VERSION 5.8 ;
BUSBITCHARS "[]" ;
DIVIDERCHAR "/" ;
UNITS
    DATABASE MICRONS 1000 ;
END UNITS

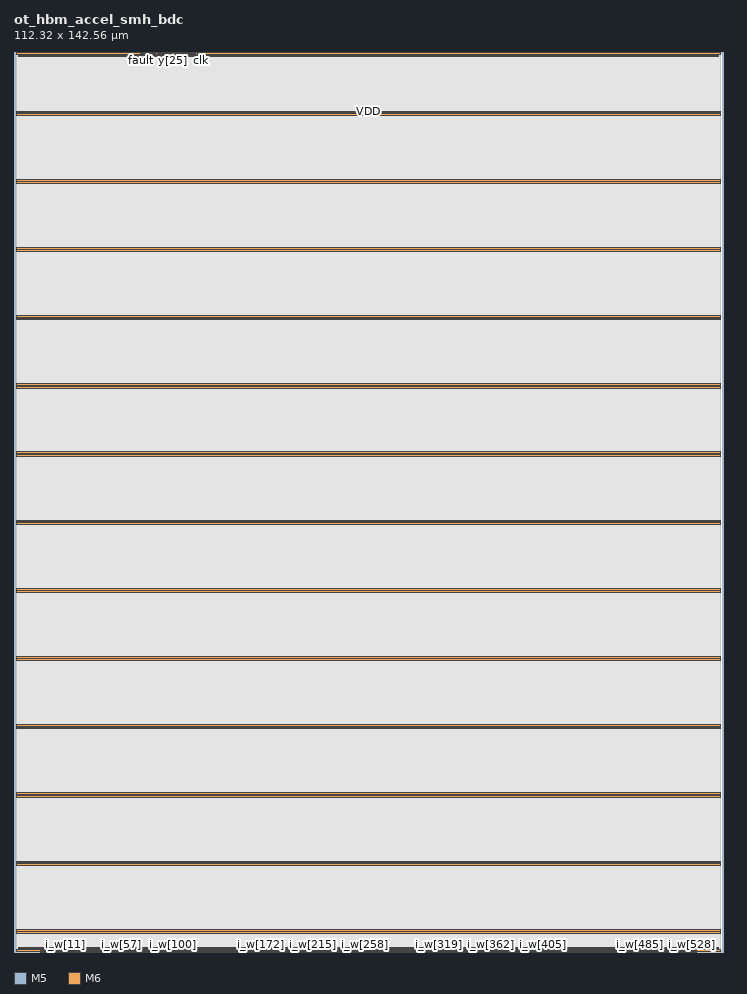
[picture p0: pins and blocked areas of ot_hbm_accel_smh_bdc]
MACRO ot_hbm_accel_smh_bdc
  FOREIGN ot_hbm_accel_smh_bdc 0 0 ;
  CLASS BLOCK ;
  SIZE 112.32 BY 142.56 ;
  PIN clk
    DIRECTION INPUT ;
    USE SIGNAL ;
    PORT
      LAYER M5 ;
        RECT  29.568 142.368 29.592 142.56 ;
    END
  END clk
  PIN fault
    DIRECTION OUTPUT ;
    USE SIGNAL ;
    PORT
      LAYER M5 ;
        RECT  20.16 142.368 20.184 142.56 ;
    END
  END fault
  PIN i_first
    DIRECTION INPUT ;
    USE SIGNAL ;
    PORT
      LAYER M5 ;
        RECT  4.224 0 4.248 0.192 ;
    END
  END i_first
  PIN i_fp4
    DIRECTION INPUT ;
    USE SIGNAL ;
    PORT
      LAYER M5 ;
        RECT  4.416 0 4.44 0.192 ;
    END
  END i_fp4
  PIN i_last
    DIRECTION INPUT ;
    USE SIGNAL ;
    PORT
      LAYER M5 ;
        RECT  4.32 0 4.344 0.192 ;
    END
  END i_last
  PIN i_tag[0]
    DIRECTION INPUT ;
    USE SIGNAL ;
    PORT
      LAYER M5 ;
        RECT  4.512 0 4.536 0.192 ;
    END
  END i_tag[0]
  PIN i_tag[10]
    DIRECTION INPUT ;
    USE SIGNAL ;
    PORT
      LAYER M5 ;
        RECT  5.472 0 5.496 0.192 ;
    END
  END i_tag[10]
  PIN i_tag[11]
    DIRECTION INPUT ;
    USE SIGNAL ;
    PORT
      LAYER M5 ;
        RECT  5.568 0 5.592 0.192 ;
    END
  END i_tag[11]
  PIN i_tag[12]
    DIRECTION INPUT ;
    USE SIGNAL ;
    PORT
      LAYER M5 ;
        RECT  5.664 0 5.688 0.192 ;
    END
  END i_tag[12]
  PIN i_tag[13]
    DIRECTION INPUT ;
    USE SIGNAL ;
    PORT
      LAYER M5 ;
        RECT  5.76 0 5.784 0.192 ;
    END
  END i_tag[13]
  PIN i_tag[14]
    DIRECTION INPUT ;
    USE SIGNAL ;
    PORT
      LAYER M5 ;
        RECT  5.856 0 5.88 0.192 ;
    END
  END i_tag[14]
  PIN i_tag[15]
    DIRECTION INPUT ;
    USE SIGNAL ;
    PORT
      LAYER M5 ;
        RECT  5.952 0 5.976 0.192 ;
    END
  END i_tag[15]
  PIN i_tag[1]
    DIRECTION INPUT ;
    USE SIGNAL ;
    PORT
      LAYER M5 ;
        RECT  4.608 0 4.632 0.192 ;
    END
  END i_tag[1]
  PIN i_tag[2]
    DIRECTION INPUT ;
    USE SIGNAL ;
    PORT
      LAYER M5 ;
        RECT  4.704 0 4.728 0.192 ;
    END
  END i_tag[2]
  PIN i_tag[3]
    DIRECTION INPUT ;
    USE SIGNAL ;
    PORT
      LAYER M5 ;
        RECT  4.8 0 4.824 0.192 ;
    END
  END i_tag[3]
  PIN i_tag[4]
    DIRECTION INPUT ;
    USE SIGNAL ;
    PORT
      LAYER M5 ;
        RECT  4.896 0 4.92 0.192 ;
    END
  END i_tag[4]
  PIN i_tag[5]
    DIRECTION INPUT ;
    USE SIGNAL ;
    PORT
      LAYER M5 ;
        RECT  4.992 0 5.016 0.192 ;
    END
  END i_tag[5]
  PIN i_tag[6]
    DIRECTION INPUT ;
    USE SIGNAL ;
    PORT
      LAYER M5 ;
        RECT  5.088 0 5.112 0.192 ;
    END
  END i_tag[6]
  PIN i_tag[7]
    DIRECTION INPUT ;
    USE SIGNAL ;
    PORT
      LAYER M5 ;
        RECT  5.184 0 5.208 0.192 ;
    END
  END i_tag[7]
  PIN i_tag[8]
    DIRECTION INPUT ;
    USE SIGNAL ;
    PORT
      LAYER M5 ;
        RECT  5.28 0 5.304 0.192 ;
    END
  END i_tag[8]
  PIN i_tag[9]
    DIRECTION INPUT ;
    USE SIGNAL ;
    PORT
      LAYER M5 ;
        RECT  5.376 0 5.4 0.192 ;
    END
  END i_tag[9]
  PIN i_v
    DIRECTION INPUT ;
    USE SIGNAL ;
    PORT
      LAYER M5 ;
        RECT  4.128 0 4.152 0.192 ;
    END
  END i_v
  PIN i_w[0]
    DIRECTION INPUT ;
    USE SIGNAL ;
    PORT
      LAYER M5 ;
        RECT  6.048 0 6.072 0.192 ;
    END
  END i_w[0]
  PIN i_w[100]
    DIRECTION INPUT ;
    USE SIGNAL ;
    PORT
      LAYER M5 ;
        RECT  25.248 0 25.272 0.192 ;
    END
  END i_w[100]
  PIN i_w[101]
    DIRECTION INPUT ;
    USE SIGNAL ;
    PORT
      LAYER M5 ;
        RECT  25.44 0 25.464 0.192 ;
    END
  END i_w[101]
  PIN i_w[102]
    DIRECTION INPUT ;
    USE SIGNAL ;
    PORT
      LAYER M5 ;
        RECT  25.632 0 25.656 0.192 ;
    END
  END i_w[102]
  PIN i_w[103]
    DIRECTION INPUT ;
    USE SIGNAL ;
    PORT
      LAYER M5 ;
        RECT  25.824 0 25.848 0.192 ;
    END
  END i_w[103]
  PIN i_w[104]
    DIRECTION INPUT ;
    USE SIGNAL ;
    PORT
      LAYER M5 ;
        RECT  26.016 0 26.04 0.192 ;
    END
  END i_w[104]
  PIN i_w[105]
    DIRECTION INPUT ;
    USE SIGNAL ;
    PORT
      LAYER M5 ;
        RECT  26.208 0 26.232 0.192 ;
    END
  END i_w[105]
  PIN i_w[106]
    DIRECTION INPUT ;
    USE SIGNAL ;
    PORT
      LAYER M5 ;
        RECT  26.4 0 26.424 0.192 ;
    END
  END i_w[106]
  PIN i_w[107]
    DIRECTION INPUT ;
    USE SIGNAL ;
    PORT
      LAYER M5 ;
        RECT  26.592 0 26.616 0.192 ;
    END
  END i_w[107]
  PIN i_w[108]
    DIRECTION INPUT ;
    USE SIGNAL ;
    PORT
      LAYER M5 ;
        RECT  26.784 0 26.808 0.192 ;
    END
  END i_w[108]
  PIN i_w[109]
    DIRECTION INPUT ;
    USE SIGNAL ;
    PORT
      LAYER M5 ;
        RECT  26.976 0 27 0.192 ;
    END
  END i_w[109]
  PIN i_w[10]
    DIRECTION INPUT ;
    USE SIGNAL ;
    PORT
      LAYER M5 ;
        RECT  7.968 0 7.992 0.192 ;
    END
  END i_w[10]
  PIN i_w[110]
    DIRECTION INPUT ;
    USE SIGNAL ;
    PORT
      LAYER M5 ;
        RECT  27.168 0 27.192 0.192 ;
    END
  END i_w[110]
  PIN i_w[111]
    DIRECTION INPUT ;
    USE SIGNAL ;
    PORT
      LAYER M5 ;
        RECT  27.36 0 27.384 0.192 ;
    END
  END i_w[111]
  PIN i_w[112]
    DIRECTION INPUT ;
    USE SIGNAL ;
    PORT
      LAYER M5 ;
        RECT  27.552 0 27.576 0.192 ;
    END
  END i_w[112]
  PIN i_w[113]
    DIRECTION INPUT ;
    USE SIGNAL ;
    PORT
      LAYER M5 ;
        RECT  27.744 0 27.768 0.192 ;
    END
  END i_w[113]
  PIN i_w[114]
    DIRECTION INPUT ;
    USE SIGNAL ;
    PORT
      LAYER M5 ;
        RECT  27.936 0 27.96 0.192 ;
    END
  END i_w[114]
  PIN i_w[115]
    DIRECTION INPUT ;
    USE SIGNAL ;
    PORT
      LAYER M5 ;
        RECT  28.128 0 28.152 0.192 ;
    END
  END i_w[115]
  PIN i_w[116]
    DIRECTION INPUT ;
    USE SIGNAL ;
    PORT
      LAYER M5 ;
        RECT  28.32 0 28.344 0.192 ;
    END
  END i_w[116]
  PIN i_w[117]
    DIRECTION INPUT ;
    USE SIGNAL ;
    PORT
      LAYER M5 ;
        RECT  28.512 0 28.536 0.192 ;
    END
  END i_w[117]
  PIN i_w[118]
    DIRECTION INPUT ;
    USE SIGNAL ;
    PORT
      LAYER M5 ;
        RECT  28.704 0 28.728 0.192 ;
    END
  END i_w[118]
  PIN i_w[119]
    DIRECTION INPUT ;
    USE SIGNAL ;
    PORT
      LAYER M5 ;
        RECT  28.896 0 28.92 0.192 ;
    END
  END i_w[119]
  PIN i_w[11]
    DIRECTION INPUT ;
    USE SIGNAL ;
    PORT
      LAYER M5 ;
        RECT  8.16 0 8.184 0.192 ;
    END
  END i_w[11]
  PIN i_w[120]
    DIRECTION INPUT ;
    USE SIGNAL ;
    PORT
      LAYER M5 ;
        RECT  29.088 0 29.112 0.192 ;
    END
  END i_w[120]
  PIN i_w[121]
    DIRECTION INPUT ;
    USE SIGNAL ;
    PORT
      LAYER M5 ;
        RECT  29.28 0 29.304 0.192 ;
    END
  END i_w[121]
  PIN i_w[122]
    DIRECTION INPUT ;
    USE SIGNAL ;
    PORT
      LAYER M5 ;
        RECT  29.472 0 29.496 0.192 ;
    END
  END i_w[122]
  PIN i_w[123]
    DIRECTION INPUT ;
    USE SIGNAL ;
    PORT
      LAYER M5 ;
        RECT  29.664 0 29.688 0.192 ;
    END
  END i_w[123]
  PIN i_w[124]
    DIRECTION INPUT ;
    USE SIGNAL ;
    PORT
      LAYER M5 ;
        RECT  29.856 0 29.88 0.192 ;
    END
  END i_w[124]
  PIN i_w[125]
    DIRECTION INPUT ;
    USE SIGNAL ;
    PORT
      LAYER M5 ;
        RECT  30.048 0 30.072 0.192 ;
    END
  END i_w[125]
  PIN i_w[126]
    DIRECTION INPUT ;
    USE SIGNAL ;
    PORT
      LAYER M5 ;
        RECT  30.24 0 30.264 0.192 ;
    END
  END i_w[126]
  PIN i_w[127]
    DIRECTION INPUT ;
    USE SIGNAL ;
    PORT
      LAYER M5 ;
        RECT  30.432 0 30.456 0.192 ;
    END
  END i_w[127]
  PIN i_w[128]
    DIRECTION INPUT ;
    USE SIGNAL ;
    PORT
      LAYER M5 ;
        RECT  30.624 0 30.648 0.192 ;
    END
  END i_w[128]
  PIN i_w[129]
    DIRECTION INPUT ;
    USE SIGNAL ;
    PORT
      LAYER M5 ;
        RECT  30.816 0 30.84 0.192 ;
    END
  END i_w[129]
  PIN i_w[12]
    DIRECTION INPUT ;
    USE SIGNAL ;
    PORT
      LAYER M5 ;
        RECT  8.352 0 8.376 0.192 ;
    END
  END i_w[12]
  PIN i_w[130]
    DIRECTION INPUT ;
    USE SIGNAL ;
    PORT
      LAYER M5 ;
        RECT  31.008 0 31.032 0.192 ;
    END
  END i_w[130]
  PIN i_w[131]
    DIRECTION INPUT ;
    USE SIGNAL ;
    PORT
      LAYER M5 ;
        RECT  31.2 0 31.224 0.192 ;
    END
  END i_w[131]
  PIN i_w[132]
    DIRECTION INPUT ;
    USE SIGNAL ;
    PORT
      LAYER M5 ;
        RECT  31.392 0 31.416 0.192 ;
    END
  END i_w[132]
  PIN i_w[133]
    DIRECTION INPUT ;
    USE SIGNAL ;
    PORT
      LAYER M5 ;
        RECT  31.584 0 31.608 0.192 ;
    END
  END i_w[133]
  PIN i_w[134]
    DIRECTION INPUT ;
    USE SIGNAL ;
    PORT
      LAYER M5 ;
        RECT  31.776 0 31.8 0.192 ;
    END
  END i_w[134]
  PIN i_w[135]
    DIRECTION INPUT ;
    USE SIGNAL ;
    PORT
      LAYER M5 ;
        RECT  31.968 0 31.992 0.192 ;
    END
  END i_w[135]
  PIN i_w[136]
    DIRECTION INPUT ;
    USE SIGNAL ;
    PORT
      LAYER M5 ;
        RECT  32.16 0 32.184 0.192 ;
    END
  END i_w[136]
  PIN i_w[137]
    DIRECTION INPUT ;
    USE SIGNAL ;
    PORT
      LAYER M5 ;
        RECT  32.352 0 32.376 0.192 ;
    END
  END i_w[137]
  PIN i_w[138]
    DIRECTION INPUT ;
    USE SIGNAL ;
    PORT
      LAYER M5 ;
        RECT  32.544 0 32.568 0.192 ;
    END
  END i_w[138]
  PIN i_w[139]
    DIRECTION INPUT ;
    USE SIGNAL ;
    PORT
      LAYER M5 ;
        RECT  32.736 0 32.76 0.192 ;
    END
  END i_w[139]
  PIN i_w[13]
    DIRECTION INPUT ;
    USE SIGNAL ;
    PORT
      LAYER M5 ;
        RECT  8.544 0 8.568 0.192 ;
    END
  END i_w[13]
  PIN i_w[140]
    DIRECTION INPUT ;
    USE SIGNAL ;
    PORT
      LAYER M5 ;
        RECT  32.928 0 32.952 0.192 ;
    END
  END i_w[140]
  PIN i_w[141]
    DIRECTION INPUT ;
    USE SIGNAL ;
    PORT
      LAYER M5 ;
        RECT  33.12 0 33.144 0.192 ;
    END
  END i_w[141]
  PIN i_w[142]
    DIRECTION INPUT ;
    USE SIGNAL ;
    PORT
      LAYER M5 ;
        RECT  33.312 0 33.336 0.192 ;
    END
  END i_w[142]
  PIN i_w[143]
    DIRECTION INPUT ;
    USE SIGNAL ;
    PORT
      LAYER M5 ;
        RECT  33.504 0 33.528 0.192 ;
    END
  END i_w[143]
  PIN i_w[144]
    DIRECTION INPUT ;
    USE SIGNAL ;
    PORT
      LAYER M5 ;
        RECT  33.696 0 33.72 0.192 ;
    END
  END i_w[144]
  PIN i_w[145]
    DIRECTION INPUT ;
    USE SIGNAL ;
    PORT
      LAYER M5 ;
        RECT  33.888 0 33.912 0.192 ;
    END
  END i_w[145]
  PIN i_w[146]
    DIRECTION INPUT ;
    USE SIGNAL ;
    PORT
      LAYER M5 ;
        RECT  34.08 0 34.104 0.192 ;
    END
  END i_w[146]
  PIN i_w[147]
    DIRECTION INPUT ;
    USE SIGNAL ;
    PORT
      LAYER M5 ;
        RECT  34.272 0 34.296 0.192 ;
    END
  END i_w[147]
  PIN i_w[148]
    DIRECTION INPUT ;
    USE SIGNAL ;
    PORT
      LAYER M5 ;
        RECT  34.464 0 34.488 0.192 ;
    END
  END i_w[148]
  PIN i_w[149]
    DIRECTION INPUT ;
    USE SIGNAL ;
    PORT
      LAYER M5 ;
        RECT  34.656 0 34.68 0.192 ;
    END
  END i_w[149]
  PIN i_w[14]
    DIRECTION INPUT ;
    USE SIGNAL ;
    PORT
      LAYER M5 ;
        RECT  8.736 0 8.76 0.192 ;
    END
  END i_w[14]
  PIN i_w[150]
    DIRECTION INPUT ;
    USE SIGNAL ;
    PORT
      LAYER M5 ;
        RECT  34.848 0 34.872 0.192 ;
    END
  END i_w[150]
  PIN i_w[151]
    DIRECTION INPUT ;
    USE SIGNAL ;
    PORT
      LAYER M5 ;
        RECT  35.04 0 35.064 0.192 ;
    END
  END i_w[151]
  PIN i_w[152]
    DIRECTION INPUT ;
    USE SIGNAL ;
    PORT
      LAYER M5 ;
        RECT  35.232 0 35.256 0.192 ;
    END
  END i_w[152]
  PIN i_w[153]
    DIRECTION INPUT ;
    USE SIGNAL ;
    PORT
      LAYER M5 ;
        RECT  35.424 0 35.448 0.192 ;
    END
  END i_w[153]
  PIN i_w[154]
    DIRECTION INPUT ;
    USE SIGNAL ;
    PORT
      LAYER M5 ;
        RECT  35.616 0 35.64 0.192 ;
    END
  END i_w[154]
  PIN i_w[155]
    DIRECTION INPUT ;
    USE SIGNAL ;
    PORT
      LAYER M5 ;
        RECT  35.808 0 35.832 0.192 ;
    END
  END i_w[155]
  PIN i_w[156]
    DIRECTION INPUT ;
    USE SIGNAL ;
    PORT
      LAYER M5 ;
        RECT  36 0 36.024 0.192 ;
    END
  END i_w[156]
  PIN i_w[157]
    DIRECTION INPUT ;
    USE SIGNAL ;
    PORT
      LAYER M5 ;
        RECT  36.192 0 36.216 0.192 ;
    END
  END i_w[157]
  PIN i_w[158]
    DIRECTION INPUT ;
    USE SIGNAL ;
    PORT
      LAYER M5 ;
        RECT  36.384 0 36.408 0.192 ;
    END
  END i_w[158]
  PIN i_w[159]
    DIRECTION INPUT ;
    USE SIGNAL ;
    PORT
      LAYER M5 ;
        RECT  36.576 0 36.6 0.192 ;
    END
  END i_w[159]
  PIN i_w[15]
    DIRECTION INPUT ;
    USE SIGNAL ;
    PORT
      LAYER M5 ;
        RECT  8.928 0 8.952 0.192 ;
    END
  END i_w[15]
  PIN i_w[160]
    DIRECTION INPUT ;
    USE SIGNAL ;
    PORT
      LAYER M5 ;
        RECT  36.768 0 36.792 0.192 ;
    END
  END i_w[160]
  PIN i_w[161]
    DIRECTION INPUT ;
    USE SIGNAL ;
    PORT
      LAYER M5 ;
        RECT  36.96 0 36.984 0.192 ;
    END
  END i_w[161]
  PIN i_w[162]
    DIRECTION INPUT ;
    USE SIGNAL ;
    PORT
      LAYER M5 ;
        RECT  37.152 0 37.176 0.192 ;
    END
  END i_w[162]
  PIN i_w[163]
    DIRECTION INPUT ;
    USE SIGNAL ;
    PORT
      LAYER M5 ;
        RECT  37.344 0 37.368 0.192 ;
    END
  END i_w[163]
  PIN i_w[164]
    DIRECTION INPUT ;
    USE SIGNAL ;
    PORT
      LAYER M5 ;
        RECT  37.536 0 37.56 0.192 ;
    END
  END i_w[164]
  PIN i_w[165]
    DIRECTION INPUT ;
    USE SIGNAL ;
    PORT
      LAYER M5 ;
        RECT  37.728 0 37.752 0.192 ;
    END
  END i_w[165]
  PIN i_w[166]
    DIRECTION INPUT ;
    USE SIGNAL ;
    PORT
      LAYER M5 ;
        RECT  37.92 0 37.944 0.192 ;
    END
  END i_w[166]
  PIN i_w[167]
    DIRECTION INPUT ;
    USE SIGNAL ;
    PORT
      LAYER M5 ;
        RECT  38.112 0 38.136 0.192 ;
    END
  END i_w[167]
  PIN i_w[168]
    DIRECTION INPUT ;
    USE SIGNAL ;
    PORT
      LAYER M5 ;
        RECT  38.304 0 38.328 0.192 ;
    END
  END i_w[168]
  PIN i_w[169]
    DIRECTION INPUT ;
    USE SIGNAL ;
    PORT
      LAYER M5 ;
        RECT  38.496 0 38.52 0.192 ;
    END
  END i_w[169]
  PIN i_w[16]
    DIRECTION INPUT ;
    USE SIGNAL ;
    PORT
      LAYER M5 ;
        RECT  9.12 0 9.144 0.192 ;
    END
  END i_w[16]
  PIN i_w[170]
    DIRECTION INPUT ;
    USE SIGNAL ;
    PORT
      LAYER M5 ;
        RECT  38.688 0 38.712 0.192 ;
    END
  END i_w[170]
  PIN i_w[171]
    DIRECTION INPUT ;
    USE SIGNAL ;
    PORT
      LAYER M5 ;
        RECT  38.88 0 38.904 0.192 ;
    END
  END i_w[171]
  PIN i_w[172]
    DIRECTION INPUT ;
    USE SIGNAL ;
    PORT
      LAYER M5 ;
        RECT  39.072 0 39.096 0.192 ;
    END
  END i_w[172]
  PIN i_w[173]
    DIRECTION INPUT ;
    USE SIGNAL ;
    PORT
      LAYER M5 ;
        RECT  39.264 0 39.288 0.192 ;
    END
  END i_w[173]
  PIN i_w[174]
    DIRECTION INPUT ;
    USE SIGNAL ;
    PORT
      LAYER M5 ;
        RECT  39.456 0 39.48 0.192 ;
    END
  END i_w[174]
  PIN i_w[175]
    DIRECTION INPUT ;
    USE SIGNAL ;
    PORT
      LAYER M5 ;
        RECT  39.648 0 39.672 0.192 ;
    END
  END i_w[175]
  PIN i_w[176]
    DIRECTION INPUT ;
    USE SIGNAL ;
    PORT
      LAYER M5 ;
        RECT  39.84 0 39.864 0.192 ;
    END
  END i_w[176]
  PIN i_w[177]
    DIRECTION INPUT ;
    USE SIGNAL ;
    PORT
      LAYER M5 ;
        RECT  40.032 0 40.056 0.192 ;
    END
  END i_w[177]
  PIN i_w[178]
    DIRECTION INPUT ;
    USE SIGNAL ;
    PORT
      LAYER M5 ;
        RECT  40.224 0 40.248 0.192 ;
    END
  END i_w[178]
  PIN i_w[179]
    DIRECTION INPUT ;
    USE SIGNAL ;
    PORT
      LAYER M5 ;
        RECT  40.416 0 40.44 0.192 ;
    END
  END i_w[179]
  PIN i_w[17]
    DIRECTION INPUT ;
    USE SIGNAL ;
    PORT
      LAYER M5 ;
        RECT  9.312 0 9.336 0.192 ;
    END
  END i_w[17]
  PIN i_w[180]
    DIRECTION INPUT ;
    USE SIGNAL ;
    PORT
      LAYER M5 ;
        RECT  40.608 0 40.632 0.192 ;
    END
  END i_w[180]
  PIN i_w[181]
    DIRECTION INPUT ;
    USE SIGNAL ;
    PORT
      LAYER M5 ;
        RECT  40.8 0 40.824 0.192 ;
    END
  END i_w[181]
  PIN i_w[182]
    DIRECTION INPUT ;
    USE SIGNAL ;
    PORT
      LAYER M5 ;
        RECT  40.992 0 41.016 0.192 ;
    END
  END i_w[182]
  PIN i_w[183]
    DIRECTION INPUT ;
    USE SIGNAL ;
    PORT
      LAYER M5 ;
        RECT  41.184 0 41.208 0.192 ;
    END
  END i_w[183]
  PIN i_w[184]
    DIRECTION INPUT ;
    USE SIGNAL ;
    PORT
      LAYER M5 ;
        RECT  41.376 0 41.4 0.192 ;
    END
  END i_w[184]
  PIN i_w[185]
    DIRECTION INPUT ;
    USE SIGNAL ;
    PORT
      LAYER M5 ;
        RECT  41.568 0 41.592 0.192 ;
    END
  END i_w[185]
  PIN i_w[186]
    DIRECTION INPUT ;
    USE SIGNAL ;
    PORT
      LAYER M5 ;
        RECT  41.76 0 41.784 0.192 ;
    END
  END i_w[186]
  PIN i_w[187]
    DIRECTION INPUT ;
    USE SIGNAL ;
    PORT
      LAYER M5 ;
        RECT  41.952 0 41.976 0.192 ;
    END
  END i_w[187]
  PIN i_w[188]
    DIRECTION INPUT ;
    USE SIGNAL ;
    PORT
      LAYER M5 ;
        RECT  42.144 0 42.168 0.192 ;
    END
  END i_w[188]
  PIN i_w[189]
    DIRECTION INPUT ;
    USE SIGNAL ;
    PORT
      LAYER M5 ;
        RECT  42.336 0 42.36 0.192 ;
    END
  END i_w[189]
  PIN i_w[18]
    DIRECTION INPUT ;
    USE SIGNAL ;
    PORT
      LAYER M5 ;
        RECT  9.504 0 9.528 0.192 ;
    END
  END i_w[18]
  PIN i_w[190]
    DIRECTION INPUT ;
    USE SIGNAL ;
    PORT
      LAYER M5 ;
        RECT  42.528 0 42.552 0.192 ;
    END
  END i_w[190]
  PIN i_w[191]
    DIRECTION INPUT ;
    USE SIGNAL ;
    PORT
      LAYER M5 ;
        RECT  42.72 0 42.744 0.192 ;
    END
  END i_w[191]
  PIN i_w[192]
    DIRECTION INPUT ;
    USE SIGNAL ;
    PORT
      LAYER M5 ;
        RECT  42.912 0 42.936 0.192 ;
    END
  END i_w[192]
  PIN i_w[193]
    DIRECTION INPUT ;
    USE SIGNAL ;
    PORT
      LAYER M5 ;
        RECT  43.104 0 43.128 0.192 ;
    END
  END i_w[193]
  PIN i_w[194]
    DIRECTION INPUT ;
    USE SIGNAL ;
    PORT
      LAYER M5 ;
        RECT  43.296 0 43.32 0.192 ;
    END
  END i_w[194]
  PIN i_w[195]
    DIRECTION INPUT ;
    USE SIGNAL ;
    PORT
      LAYER M5 ;
        RECT  43.488 0 43.512 0.192 ;
    END
  END i_w[195]
  PIN i_w[196]
    DIRECTION INPUT ;
    USE SIGNAL ;
    PORT
      LAYER M5 ;
        RECT  43.68 0 43.704 0.192 ;
    END
  END i_w[196]
  PIN i_w[197]
    DIRECTION INPUT ;
    USE SIGNAL ;
    PORT
      LAYER M5 ;
        RECT  43.872 0 43.896 0.192 ;
    END
  END i_w[197]
  PIN i_w[198]
    DIRECTION INPUT ;
    USE SIGNAL ;
    PORT
      LAYER M5 ;
        RECT  44.064 0 44.088 0.192 ;
    END
  END i_w[198]
  PIN i_w[199]
    DIRECTION INPUT ;
    USE SIGNAL ;
    PORT
      LAYER M5 ;
        RECT  44.256 0 44.28 0.192 ;
    END
  END i_w[199]
  PIN i_w[19]
    DIRECTION INPUT ;
    USE SIGNAL ;
    PORT
      LAYER M5 ;
        RECT  9.696 0 9.72 0.192 ;
    END
  END i_w[19]
  PIN i_w[1]
    DIRECTION INPUT ;
    USE SIGNAL ;
    PORT
      LAYER M5 ;
        RECT  6.24 0 6.264 0.192 ;
    END
  END i_w[1]
  PIN i_w[200]
    DIRECTION INPUT ;
    USE SIGNAL ;
    PORT
      LAYER M5 ;
        RECT  44.448 0 44.472 0.192 ;
    END
  END i_w[200]
  PIN i_w[201]
    DIRECTION INPUT ;
    USE SIGNAL ;
    PORT
      LAYER M5 ;
        RECT  44.64 0 44.664 0.192 ;
    END
  END i_w[201]
  PIN i_w[202]
    DIRECTION INPUT ;
    USE SIGNAL ;
    PORT
      LAYER M5 ;
        RECT  44.832 0 44.856 0.192 ;
    END
  END i_w[202]
  PIN i_w[203]
    DIRECTION INPUT ;
    USE SIGNAL ;
    PORT
      LAYER M5 ;
        RECT  45.024 0 45.048 0.192 ;
    END
  END i_w[203]
  PIN i_w[204]
    DIRECTION INPUT ;
    USE SIGNAL ;
    PORT
      LAYER M5 ;
        RECT  45.216 0 45.24 0.192 ;
    END
  END i_w[204]
  PIN i_w[205]
    DIRECTION INPUT ;
    USE SIGNAL ;
    PORT
      LAYER M5 ;
        RECT  45.408 0 45.432 0.192 ;
    END
  END i_w[205]
  PIN i_w[206]
    DIRECTION INPUT ;
    USE SIGNAL ;
    PORT
      LAYER M5 ;
        RECT  45.6 0 45.624 0.192 ;
    END
  END i_w[206]
  PIN i_w[207]
    DIRECTION INPUT ;
    USE SIGNAL ;
    PORT
      LAYER M5 ;
        RECT  45.792 0 45.816 0.192 ;
    END
  END i_w[207]
  PIN i_w[208]
    DIRECTION INPUT ;
    USE SIGNAL ;
    PORT
      LAYER M5 ;
        RECT  45.984 0 46.008 0.192 ;
    END
  END i_w[208]
  PIN i_w[209]
    DIRECTION INPUT ;
    USE SIGNAL ;
    PORT
      LAYER M5 ;
        RECT  46.176 0 46.2 0.192 ;
    END
  END i_w[209]
  PIN i_w[20]
    DIRECTION INPUT ;
    USE SIGNAL ;
    PORT
      LAYER M5 ;
        RECT  9.888 0 9.912 0.192 ;
    END
  END i_w[20]
  PIN i_w[210]
    DIRECTION INPUT ;
    USE SIGNAL ;
    PORT
      LAYER M5 ;
        RECT  46.368 0 46.392 0.192 ;
    END
  END i_w[210]
  PIN i_w[211]
    DIRECTION INPUT ;
    USE SIGNAL ;
    PORT
      LAYER M5 ;
        RECT  46.56 0 46.584 0.192 ;
    END
  END i_w[211]
  PIN i_w[212]
    DIRECTION INPUT ;
    USE SIGNAL ;
    PORT
      LAYER M5 ;
        RECT  46.752 0 46.776 0.192 ;
    END
  END i_w[212]
  PIN i_w[213]
    DIRECTION INPUT ;
    USE SIGNAL ;
    PORT
      LAYER M5 ;
        RECT  46.944 0 46.968 0.192 ;
    END
  END i_w[213]
  PIN i_w[214]
    DIRECTION INPUT ;
    USE SIGNAL ;
    PORT
      LAYER M5 ;
        RECT  47.136 0 47.16 0.192 ;
    END
  END i_w[214]
  PIN i_w[215]
    DIRECTION INPUT ;
    USE SIGNAL ;
    PORT
      LAYER M5 ;
        RECT  47.328 0 47.352 0.192 ;
    END
  END i_w[215]
  PIN i_w[216]
    DIRECTION INPUT ;
    USE SIGNAL ;
    PORT
      LAYER M5 ;
        RECT  47.52 0 47.544 0.192 ;
    END
  END i_w[216]
  PIN i_w[217]
    DIRECTION INPUT ;
    USE SIGNAL ;
    PORT
      LAYER M5 ;
        RECT  47.712 0 47.736 0.192 ;
    END
  END i_w[217]
  PIN i_w[218]
    DIRECTION INPUT ;
    USE SIGNAL ;
    PORT
      LAYER M5 ;
        RECT  47.904 0 47.928 0.192 ;
    END
  END i_w[218]
  PIN i_w[219]
    DIRECTION INPUT ;
    USE SIGNAL ;
    PORT
      LAYER M5 ;
        RECT  48.096 0 48.12 0.192 ;
    END
  END i_w[219]
  PIN i_w[21]
    DIRECTION INPUT ;
    USE SIGNAL ;
    PORT
      LAYER M5 ;
        RECT  10.08 0 10.104 0.192 ;
    END
  END i_w[21]
  PIN i_w[220]
    DIRECTION INPUT ;
    USE SIGNAL ;
    PORT
      LAYER M5 ;
        RECT  48.288 0 48.312 0.192 ;
    END
  END i_w[220]
  PIN i_w[221]
    DIRECTION INPUT ;
    USE SIGNAL ;
    PORT
      LAYER M5 ;
        RECT  48.48 0 48.504 0.192 ;
    END
  END i_w[221]
  PIN i_w[222]
    DIRECTION INPUT ;
    USE SIGNAL ;
    PORT
      LAYER M5 ;
        RECT  48.672 0 48.696 0.192 ;
    END
  END i_w[222]
  PIN i_w[223]
    DIRECTION INPUT ;
    USE SIGNAL ;
    PORT
      LAYER M5 ;
        RECT  48.864 0 48.888 0.192 ;
    END
  END i_w[223]
  PIN i_w[224]
    DIRECTION INPUT ;
    USE SIGNAL ;
    PORT
      LAYER M5 ;
        RECT  49.056 0 49.08 0.192 ;
    END
  END i_w[224]
  PIN i_w[225]
    DIRECTION INPUT ;
    USE SIGNAL ;
    PORT
      LAYER M5 ;
        RECT  49.248 0 49.272 0.192 ;
    END
  END i_w[225]
  PIN i_w[226]
    DIRECTION INPUT ;
    USE SIGNAL ;
    PORT
      LAYER M5 ;
        RECT  49.44 0 49.464 0.192 ;
    END
  END i_w[226]
  PIN i_w[227]
    DIRECTION INPUT ;
    USE SIGNAL ;
    PORT
      LAYER M5 ;
        RECT  49.632 0 49.656 0.192 ;
    END
  END i_w[227]
  PIN i_w[228]
    DIRECTION INPUT ;
    USE SIGNAL ;
    PORT
      LAYER M5 ;
        RECT  49.824 0 49.848 0.192 ;
    END
  END i_w[228]
  PIN i_w[229]
    DIRECTION INPUT ;
    USE SIGNAL ;
    PORT
      LAYER M5 ;
        RECT  50.016 0 50.04 0.192 ;
    END
  END i_w[229]
  PIN i_w[22]
    DIRECTION INPUT ;
    USE SIGNAL ;
    PORT
      LAYER M5 ;
        RECT  10.272 0 10.296 0.192 ;
    END
  END i_w[22]
  PIN i_w[230]
    DIRECTION INPUT ;
    USE SIGNAL ;
    PORT
      LAYER M5 ;
        RECT  50.208 0 50.232 0.192 ;
    END
  END i_w[230]
  PIN i_w[231]
    DIRECTION INPUT ;
    USE SIGNAL ;
    PORT
      LAYER M5 ;
        RECT  50.4 0 50.424 0.192 ;
    END
  END i_w[231]
  PIN i_w[232]
    DIRECTION INPUT ;
    USE SIGNAL ;
    PORT
      LAYER M5 ;
        RECT  50.592 0 50.616 0.192 ;
    END
  END i_w[232]
  PIN i_w[233]
    DIRECTION INPUT ;
    USE SIGNAL ;
    PORT
      LAYER M5 ;
        RECT  50.784 0 50.808 0.192 ;
    END
  END i_w[233]
  PIN i_w[234]
    DIRECTION INPUT ;
    USE SIGNAL ;
    PORT
      LAYER M5 ;
        RECT  50.976 0 51 0.192 ;
    END
  END i_w[234]
  PIN i_w[235]
    DIRECTION INPUT ;
    USE SIGNAL ;
    PORT
      LAYER M5 ;
        RECT  51.168 0 51.192 0.192 ;
    END
  END i_w[235]
  PIN i_w[236]
    DIRECTION INPUT ;
    USE SIGNAL ;
    PORT
      LAYER M5 ;
        RECT  51.36 0 51.384 0.192 ;
    END
  END i_w[236]
  PIN i_w[237]
    DIRECTION INPUT ;
    USE SIGNAL ;
    PORT
      LAYER M5 ;
        RECT  51.552 0 51.576 0.192 ;
    END
  END i_w[237]
  PIN i_w[238]
    DIRECTION INPUT ;
    USE SIGNAL ;
    PORT
      LAYER M5 ;
        RECT  51.744 0 51.768 0.192 ;
    END
  END i_w[238]
  PIN i_w[239]
    DIRECTION INPUT ;
    USE SIGNAL ;
    PORT
      LAYER M5 ;
        RECT  51.936 0 51.96 0.192 ;
    END
  END i_w[239]
  PIN i_w[23]
    DIRECTION INPUT ;
    USE SIGNAL ;
    PORT
      LAYER M5 ;
        RECT  10.464 0 10.488 0.192 ;
    END
  END i_w[23]
  PIN i_w[240]
    DIRECTION INPUT ;
    USE SIGNAL ;
    PORT
      LAYER M5 ;
        RECT  52.128 0 52.152 0.192 ;
    END
  END i_w[240]
  PIN i_w[241]
    DIRECTION INPUT ;
    USE SIGNAL ;
    PORT
      LAYER M5 ;
        RECT  52.32 0 52.344 0.192 ;
    END
  END i_w[241]
  PIN i_w[242]
    DIRECTION INPUT ;
    USE SIGNAL ;
    PORT
      LAYER M5 ;
        RECT  52.512 0 52.536 0.192 ;
    END
  END i_w[242]
  PIN i_w[243]
    DIRECTION INPUT ;
    USE SIGNAL ;
    PORT
      LAYER M5 ;
        RECT  52.704 0 52.728 0.192 ;
    END
  END i_w[243]
  PIN i_w[244]
    DIRECTION INPUT ;
    USE SIGNAL ;
    PORT
      LAYER M5 ;
        RECT  52.896 0 52.92 0.192 ;
    END
  END i_w[244]
  PIN i_w[245]
    DIRECTION INPUT ;
    USE SIGNAL ;
    PORT
      LAYER M5 ;
        RECT  53.088 0 53.112 0.192 ;
    END
  END i_w[245]
  PIN i_w[246]
    DIRECTION INPUT ;
    USE SIGNAL ;
    PORT
      LAYER M5 ;
        RECT  53.28 0 53.304 0.192 ;
    END
  END i_w[246]
  PIN i_w[247]
    DIRECTION INPUT ;
    USE SIGNAL ;
    PORT
      LAYER M5 ;
        RECT  53.472 0 53.496 0.192 ;
    END
  END i_w[247]
  PIN i_w[248]
    DIRECTION INPUT ;
    USE SIGNAL ;
    PORT
      LAYER M5 ;
        RECT  53.664 0 53.688 0.192 ;
    END
  END i_w[248]
  PIN i_w[249]
    DIRECTION INPUT ;
    USE SIGNAL ;
    PORT
      LAYER M5 ;
        RECT  53.856 0 53.88 0.192 ;
    END
  END i_w[249]
  PIN i_w[24]
    DIRECTION INPUT ;
    USE SIGNAL ;
    PORT
      LAYER M5 ;
        RECT  10.656 0 10.68 0.192 ;
    END
  END i_w[24]
  PIN i_w[250]
    DIRECTION INPUT ;
    USE SIGNAL ;
    PORT
      LAYER M5 ;
        RECT  54.048 0 54.072 0.192 ;
    END
  END i_w[250]
  PIN i_w[251]
    DIRECTION INPUT ;
    USE SIGNAL ;
    PORT
      LAYER M5 ;
        RECT  54.24 0 54.264 0.192 ;
    END
  END i_w[251]
  PIN i_w[252]
    DIRECTION INPUT ;
    USE SIGNAL ;
    PORT
      LAYER M5 ;
        RECT  54.432 0 54.456 0.192 ;
    END
  END i_w[252]
  PIN i_w[253]
    DIRECTION INPUT ;
    USE SIGNAL ;
    PORT
      LAYER M5 ;
        RECT  54.624 0 54.648 0.192 ;
    END
  END i_w[253]
  PIN i_w[254]
    DIRECTION INPUT ;
    USE SIGNAL ;
    PORT
      LAYER M5 ;
        RECT  54.816 0 54.84 0.192 ;
    END
  END i_w[254]
  PIN i_w[255]
    DIRECTION INPUT ;
    USE SIGNAL ;
    PORT
      LAYER M5 ;
        RECT  55.008 0 55.032 0.192 ;
    END
  END i_w[255]
  PIN i_w[256]
    DIRECTION INPUT ;
    USE SIGNAL ;
    PORT
      LAYER M5 ;
        RECT  55.2 0 55.224 0.192 ;
    END
  END i_w[256]
  PIN i_w[257]
    DIRECTION INPUT ;
    USE SIGNAL ;
    PORT
      LAYER M5 ;
        RECT  55.392 0 55.416 0.192 ;
    END
  END i_w[257]
  PIN i_w[258]
    DIRECTION INPUT ;
    USE SIGNAL ;
    PORT
      LAYER M5 ;
        RECT  55.584 0 55.608 0.192 ;
    END
  END i_w[258]
  PIN i_w[259]
    DIRECTION INPUT ;
    USE SIGNAL ;
    PORT
      LAYER M5 ;
        RECT  55.776 0 55.8 0.192 ;
    END
  END i_w[259]
  PIN i_w[25]
    DIRECTION INPUT ;
    USE SIGNAL ;
    PORT
      LAYER M5 ;
        RECT  10.848 0 10.872 0.192 ;
    END
  END i_w[25]
  PIN i_w[260]
    DIRECTION INPUT ;
    USE SIGNAL ;
    PORT
      LAYER M5 ;
        RECT  55.968 0 55.992 0.192 ;
    END
  END i_w[260]
  PIN i_w[261]
    DIRECTION INPUT ;
    USE SIGNAL ;
    PORT
      LAYER M5 ;
        RECT  56.16 0 56.184 0.192 ;
    END
  END i_w[261]
  PIN i_w[262]
    DIRECTION INPUT ;
    USE SIGNAL ;
    PORT
      LAYER M5 ;
        RECT  56.352 0 56.376 0.192 ;
    END
  END i_w[262]
  PIN i_w[263]
    DIRECTION INPUT ;
    USE SIGNAL ;
    PORT
      LAYER M5 ;
        RECT  56.544 0 56.568 0.192 ;
    END
  END i_w[263]
  PIN i_w[264]
    DIRECTION INPUT ;
    USE SIGNAL ;
    PORT
      LAYER M5 ;
        RECT  56.736 0 56.76 0.192 ;
    END
  END i_w[264]
  PIN i_w[265]
    DIRECTION INPUT ;
    USE SIGNAL ;
    PORT
      LAYER M5 ;
        RECT  56.928 0 56.952 0.192 ;
    END
  END i_w[265]
  PIN i_w[266]
    DIRECTION INPUT ;
    USE SIGNAL ;
    PORT
      LAYER M5 ;
        RECT  57.12 0 57.144 0.192 ;
    END
  END i_w[266]
  PIN i_w[267]
    DIRECTION INPUT ;
    USE SIGNAL ;
    PORT
      LAYER M5 ;
        RECT  57.312 0 57.336 0.192 ;
    END
  END i_w[267]
  PIN i_w[268]
    DIRECTION INPUT ;
    USE SIGNAL ;
    PORT
      LAYER M5 ;
        RECT  57.504 0 57.528 0.192 ;
    END
  END i_w[268]
  PIN i_w[269]
    DIRECTION INPUT ;
    USE SIGNAL ;
    PORT
      LAYER M5 ;
        RECT  57.696 0 57.72 0.192 ;
    END
  END i_w[269]
  PIN i_w[26]
    DIRECTION INPUT ;
    USE SIGNAL ;
    PORT
      LAYER M5 ;
        RECT  11.04 0 11.064 0.192 ;
    END
  END i_w[26]
  PIN i_w[270]
    DIRECTION INPUT ;
    USE SIGNAL ;
    PORT
      LAYER M5 ;
        RECT  57.888 0 57.912 0.192 ;
    END
  END i_w[270]
  PIN i_w[271]
    DIRECTION INPUT ;
    USE SIGNAL ;
    PORT
      LAYER M5 ;
        RECT  58.08 0 58.104 0.192 ;
    END
  END i_w[271]
  PIN i_w[272]
    DIRECTION INPUT ;
    USE SIGNAL ;
    PORT
      LAYER M5 ;
        RECT  58.272 0 58.296 0.192 ;
    END
  END i_w[272]
  PIN i_w[273]
    DIRECTION INPUT ;
    USE SIGNAL ;
    PORT
      LAYER M5 ;
        RECT  58.464 0 58.488 0.192 ;
    END
  END i_w[273]
  PIN i_w[274]
    DIRECTION INPUT ;
    USE SIGNAL ;
    PORT
      LAYER M5 ;
        RECT  58.656 0 58.68 0.192 ;
    END
  END i_w[274]
  PIN i_w[275]
    DIRECTION INPUT ;
    USE SIGNAL ;
    PORT
      LAYER M5 ;
        RECT  58.848 0 58.872 0.192 ;
    END
  END i_w[275]
  PIN i_w[276]
    DIRECTION INPUT ;
    USE SIGNAL ;
    PORT
      LAYER M5 ;
        RECT  59.04 0 59.064 0.192 ;
    END
  END i_w[276]
  PIN i_w[277]
    DIRECTION INPUT ;
    USE SIGNAL ;
    PORT
      LAYER M5 ;
        RECT  59.232 0 59.256 0.192 ;
    END
  END i_w[277]
  PIN i_w[278]
    DIRECTION INPUT ;
    USE SIGNAL ;
    PORT
      LAYER M5 ;
        RECT  59.424 0 59.448 0.192 ;
    END
  END i_w[278]
  PIN i_w[279]
    DIRECTION INPUT ;
    USE SIGNAL ;
    PORT
      LAYER M5 ;
        RECT  59.616 0 59.64 0.192 ;
    END
  END i_w[279]
  PIN i_w[27]
    DIRECTION INPUT ;
    USE SIGNAL ;
    PORT
      LAYER M5 ;
        RECT  11.232 0 11.256 0.192 ;
    END
  END i_w[27]
  PIN i_w[280]
    DIRECTION INPUT ;
    USE SIGNAL ;
    PORT
      LAYER M5 ;
        RECT  59.808 0 59.832 0.192 ;
    END
  END i_w[280]
  PIN i_w[281]
    DIRECTION INPUT ;
    USE SIGNAL ;
    PORT
      LAYER M5 ;
        RECT  60 0 60.024 0.192 ;
    END
  END i_w[281]
  PIN i_w[282]
    DIRECTION INPUT ;
    USE SIGNAL ;
    PORT
      LAYER M5 ;
        RECT  60.192 0 60.216 0.192 ;
    END
  END i_w[282]
  PIN i_w[283]
    DIRECTION INPUT ;
    USE SIGNAL ;
    PORT
      LAYER M5 ;
        RECT  60.384 0 60.408 0.192 ;
    END
  END i_w[283]
  PIN i_w[284]
    DIRECTION INPUT ;
    USE SIGNAL ;
    PORT
      LAYER M5 ;
        RECT  60.576 0 60.6 0.192 ;
    END
  END i_w[284]
  PIN i_w[285]
    DIRECTION INPUT ;
    USE SIGNAL ;
    PORT
      LAYER M5 ;
        RECT  60.768 0 60.792 0.192 ;
    END
  END i_w[285]
  PIN i_w[286]
    DIRECTION INPUT ;
    USE SIGNAL ;
    PORT
      LAYER M5 ;
        RECT  60.96 0 60.984 0.192 ;
    END
  END i_w[286]
  PIN i_w[287]
    DIRECTION INPUT ;
    USE SIGNAL ;
    PORT
      LAYER M5 ;
        RECT  61.152 0 61.176 0.192 ;
    END
  END i_w[287]
  PIN i_w[288]
    DIRECTION INPUT ;
    USE SIGNAL ;
    PORT
      LAYER M5 ;
        RECT  61.344 0 61.368 0.192 ;
    END
  END i_w[288]
  PIN i_w[289]
    DIRECTION INPUT ;
    USE SIGNAL ;
    PORT
      LAYER M5 ;
        RECT  61.536 0 61.56 0.192 ;
    END
  END i_w[289]
  PIN i_w[28]
    DIRECTION INPUT ;
    USE SIGNAL ;
    PORT
      LAYER M5 ;
        RECT  11.424 0 11.448 0.192 ;
    END
  END i_w[28]
  PIN i_w[290]
    DIRECTION INPUT ;
    USE SIGNAL ;
    PORT
      LAYER M5 ;
        RECT  61.728 0 61.752 0.192 ;
    END
  END i_w[290]
  PIN i_w[291]
    DIRECTION INPUT ;
    USE SIGNAL ;
    PORT
      LAYER M5 ;
        RECT  61.92 0 61.944 0.192 ;
    END
  END i_w[291]
  PIN i_w[292]
    DIRECTION INPUT ;
    USE SIGNAL ;
    PORT
      LAYER M5 ;
        RECT  62.112 0 62.136 0.192 ;
    END
  END i_w[292]
  PIN i_w[293]
    DIRECTION INPUT ;
    USE SIGNAL ;
    PORT
      LAYER M5 ;
        RECT  62.304 0 62.328 0.192 ;
    END
  END i_w[293]
  PIN i_w[294]
    DIRECTION INPUT ;
    USE SIGNAL ;
    PORT
      LAYER M5 ;
        RECT  62.496 0 62.52 0.192 ;
    END
  END i_w[294]
  PIN i_w[295]
    DIRECTION INPUT ;
    USE SIGNAL ;
    PORT
      LAYER M5 ;
        RECT  62.688 0 62.712 0.192 ;
    END
  END i_w[295]
  PIN i_w[296]
    DIRECTION INPUT ;
    USE SIGNAL ;
    PORT
      LAYER M5 ;
        RECT  62.88 0 62.904 0.192 ;
    END
  END i_w[296]
  PIN i_w[297]
    DIRECTION INPUT ;
    USE SIGNAL ;
    PORT
      LAYER M5 ;
        RECT  63.072 0 63.096 0.192 ;
    END
  END i_w[297]
  PIN i_w[298]
    DIRECTION INPUT ;
    USE SIGNAL ;
    PORT
      LAYER M5 ;
        RECT  63.264 0 63.288 0.192 ;
    END
  END i_w[298]
  PIN i_w[299]
    DIRECTION INPUT ;
    USE SIGNAL ;
    PORT
      LAYER M5 ;
        RECT  63.456 0 63.48 0.192 ;
    END
  END i_w[299]
  PIN i_w[29]
    DIRECTION INPUT ;
    USE SIGNAL ;
    PORT
      LAYER M5 ;
        RECT  11.616 0 11.64 0.192 ;
    END
  END i_w[29]
  PIN i_w[2]
    DIRECTION INPUT ;
    USE SIGNAL ;
    PORT
      LAYER M5 ;
        RECT  6.432 0 6.456 0.192 ;
    END
  END i_w[2]
  PIN i_w[300]
    DIRECTION INPUT ;
    USE SIGNAL ;
    PORT
      LAYER M5 ;
        RECT  63.648 0 63.672 0.192 ;
    END
  END i_w[300]
  PIN i_w[301]
    DIRECTION INPUT ;
    USE SIGNAL ;
    PORT
      LAYER M5 ;
        RECT  63.84 0 63.864 0.192 ;
    END
  END i_w[301]
  PIN i_w[302]
    DIRECTION INPUT ;
    USE SIGNAL ;
    PORT
      LAYER M5 ;
        RECT  64.032 0 64.056 0.192 ;
    END
  END i_w[302]
  PIN i_w[303]
    DIRECTION INPUT ;
    USE SIGNAL ;
    PORT
      LAYER M5 ;
        RECT  64.224 0 64.248 0.192 ;
    END
  END i_w[303]
  PIN i_w[304]
    DIRECTION INPUT ;
    USE SIGNAL ;
    PORT
      LAYER M5 ;
        RECT  64.416 0 64.44 0.192 ;
    END
  END i_w[304]
  PIN i_w[305]
    DIRECTION INPUT ;
    USE SIGNAL ;
    PORT
      LAYER M5 ;
        RECT  64.608 0 64.632 0.192 ;
    END
  END i_w[305]
  PIN i_w[306]
    DIRECTION INPUT ;
    USE SIGNAL ;
    PORT
      LAYER M5 ;
        RECT  64.8 0 64.824 0.192 ;
    END
  END i_w[306]
  PIN i_w[307]
    DIRECTION INPUT ;
    USE SIGNAL ;
    PORT
      LAYER M5 ;
        RECT  64.992 0 65.016 0.192 ;
    END
  END i_w[307]
  PIN i_w[308]
    DIRECTION INPUT ;
    USE SIGNAL ;
    PORT
      LAYER M5 ;
        RECT  65.184 0 65.208 0.192 ;
    END
  END i_w[308]
  PIN i_w[309]
    DIRECTION INPUT ;
    USE SIGNAL ;
    PORT
      LAYER M5 ;
        RECT  65.376 0 65.4 0.192 ;
    END
  END i_w[309]
  PIN i_w[30]
    DIRECTION INPUT ;
    USE SIGNAL ;
    PORT
      LAYER M5 ;
        RECT  11.808 0 11.832 0.192 ;
    END
  END i_w[30]
  PIN i_w[310]
    DIRECTION INPUT ;
    USE SIGNAL ;
    PORT
      LAYER M5 ;
        RECT  65.568 0 65.592 0.192 ;
    END
  END i_w[310]
  PIN i_w[311]
    DIRECTION INPUT ;
    USE SIGNAL ;
    PORT
      LAYER M5 ;
        RECT  65.76 0 65.784 0.192 ;
    END
  END i_w[311]
  PIN i_w[312]
    DIRECTION INPUT ;
    USE SIGNAL ;
    PORT
      LAYER M5 ;
        RECT  65.952 0 65.976 0.192 ;
    END
  END i_w[312]
  PIN i_w[313]
    DIRECTION INPUT ;
    USE SIGNAL ;
    PORT
      LAYER M5 ;
        RECT  66.144 0 66.168 0.192 ;
    END
  END i_w[313]
  PIN i_w[314]
    DIRECTION INPUT ;
    USE SIGNAL ;
    PORT
      LAYER M5 ;
        RECT  66.336 0 66.36 0.192 ;
    END
  END i_w[314]
  PIN i_w[315]
    DIRECTION INPUT ;
    USE SIGNAL ;
    PORT
      LAYER M5 ;
        RECT  66.528 0 66.552 0.192 ;
    END
  END i_w[315]
  PIN i_w[316]
    DIRECTION INPUT ;
    USE SIGNAL ;
    PORT
      LAYER M5 ;
        RECT  66.72 0 66.744 0.192 ;
    END
  END i_w[316]
  PIN i_w[317]
    DIRECTION INPUT ;
    USE SIGNAL ;
    PORT
      LAYER M5 ;
        RECT  66.912 0 66.936 0.192 ;
    END
  END i_w[317]
  PIN i_w[318]
    DIRECTION INPUT ;
    USE SIGNAL ;
    PORT
      LAYER M5 ;
        RECT  67.104 0 67.128 0.192 ;
    END
  END i_w[318]
  PIN i_w[319]
    DIRECTION INPUT ;
    USE SIGNAL ;
    PORT
      LAYER M5 ;
        RECT  67.296 0 67.32 0.192 ;
    END
  END i_w[319]
  PIN i_w[31]
    DIRECTION INPUT ;
    USE SIGNAL ;
    PORT
      LAYER M5 ;
        RECT  12 0 12.024 0.192 ;
    END
  END i_w[31]
  PIN i_w[320]
    DIRECTION INPUT ;
    USE SIGNAL ;
    PORT
      LAYER M5 ;
        RECT  67.488 0 67.512 0.192 ;
    END
  END i_w[320]
  PIN i_w[321]
    DIRECTION INPUT ;
    USE SIGNAL ;
    PORT
      LAYER M5 ;
        RECT  67.68 0 67.704 0.192 ;
    END
  END i_w[321]
  PIN i_w[322]
    DIRECTION INPUT ;
    USE SIGNAL ;
    PORT
      LAYER M5 ;
        RECT  67.872 0 67.896 0.192 ;
    END
  END i_w[322]
  PIN i_w[323]
    DIRECTION INPUT ;
    USE SIGNAL ;
    PORT
      LAYER M5 ;
        RECT  68.064 0 68.088 0.192 ;
    END
  END i_w[323]
  PIN i_w[324]
    DIRECTION INPUT ;
    USE SIGNAL ;
    PORT
      LAYER M5 ;
        RECT  68.256 0 68.28 0.192 ;
    END
  END i_w[324]
  PIN i_w[325]
    DIRECTION INPUT ;
    USE SIGNAL ;
    PORT
      LAYER M5 ;
        RECT  68.448 0 68.472 0.192 ;
    END
  END i_w[325]
  PIN i_w[326]
    DIRECTION INPUT ;
    USE SIGNAL ;
    PORT
      LAYER M5 ;
        RECT  68.64 0 68.664 0.192 ;
    END
  END i_w[326]
  PIN i_w[327]
    DIRECTION INPUT ;
    USE SIGNAL ;
    PORT
      LAYER M5 ;
        RECT  68.832 0 68.856 0.192 ;
    END
  END i_w[327]
  PIN i_w[328]
    DIRECTION INPUT ;
    USE SIGNAL ;
    PORT
      LAYER M5 ;
        RECT  69.024 0 69.048 0.192 ;
    END
  END i_w[328]
  PIN i_w[329]
    DIRECTION INPUT ;
    USE SIGNAL ;
    PORT
      LAYER M5 ;
        RECT  69.216 0 69.24 0.192 ;
    END
  END i_w[329]
  PIN i_w[32]
    DIRECTION INPUT ;
    USE SIGNAL ;
    PORT
      LAYER M5 ;
        RECT  12.192 0 12.216 0.192 ;
    END
  END i_w[32]
  PIN i_w[330]
    DIRECTION INPUT ;
    USE SIGNAL ;
    PORT
      LAYER M5 ;
        RECT  69.408 0 69.432 0.192 ;
    END
  END i_w[330]
  PIN i_w[331]
    DIRECTION INPUT ;
    USE SIGNAL ;
    PORT
      LAYER M5 ;
        RECT  69.6 0 69.624 0.192 ;
    END
  END i_w[331]
  PIN i_w[332]
    DIRECTION INPUT ;
    USE SIGNAL ;
    PORT
      LAYER M5 ;
        RECT  69.792 0 69.816 0.192 ;
    END
  END i_w[332]
  PIN i_w[333]
    DIRECTION INPUT ;
    USE SIGNAL ;
    PORT
      LAYER M5 ;
        RECT  69.984 0 70.008 0.192 ;
    END
  END i_w[333]
  PIN i_w[334]
    DIRECTION INPUT ;
    USE SIGNAL ;
    PORT
      LAYER M5 ;
        RECT  70.176 0 70.2 0.192 ;
    END
  END i_w[334]
  PIN i_w[335]
    DIRECTION INPUT ;
    USE SIGNAL ;
    PORT
      LAYER M5 ;
        RECT  70.368 0 70.392 0.192 ;
    END
  END i_w[335]
  PIN i_w[336]
    DIRECTION INPUT ;
    USE SIGNAL ;
    PORT
      LAYER M5 ;
        RECT  70.56 0 70.584 0.192 ;
    END
  END i_w[336]
  PIN i_w[337]
    DIRECTION INPUT ;
    USE SIGNAL ;
    PORT
      LAYER M5 ;
        RECT  70.752 0 70.776 0.192 ;
    END
  END i_w[337]
  PIN i_w[338]
    DIRECTION INPUT ;
    USE SIGNAL ;
    PORT
      LAYER M5 ;
        RECT  70.944 0 70.968 0.192 ;
    END
  END i_w[338]
  PIN i_w[339]
    DIRECTION INPUT ;
    USE SIGNAL ;
    PORT
      LAYER M5 ;
        RECT  71.136 0 71.16 0.192 ;
    END
  END i_w[339]
  PIN i_w[33]
    DIRECTION INPUT ;
    USE SIGNAL ;
    PORT
      LAYER M5 ;
        RECT  12.384 0 12.408 0.192 ;
    END
  END i_w[33]
  PIN i_w[340]
    DIRECTION INPUT ;
    USE SIGNAL ;
    PORT
      LAYER M5 ;
        RECT  71.328 0 71.352 0.192 ;
    END
  END i_w[340]
  PIN i_w[341]
    DIRECTION INPUT ;
    USE SIGNAL ;
    PORT
      LAYER M5 ;
        RECT  71.52 0 71.544 0.192 ;
    END
  END i_w[341]
  PIN i_w[342]
    DIRECTION INPUT ;
    USE SIGNAL ;
    PORT
      LAYER M5 ;
        RECT  71.712 0 71.736 0.192 ;
    END
  END i_w[342]
  PIN i_w[343]
    DIRECTION INPUT ;
    USE SIGNAL ;
    PORT
      LAYER M5 ;
        RECT  71.904 0 71.928 0.192 ;
    END
  END i_w[343]
  PIN i_w[344]
    DIRECTION INPUT ;
    USE SIGNAL ;
    PORT
      LAYER M5 ;
        RECT  72.096 0 72.12 0.192 ;
    END
  END i_w[344]
  PIN i_w[345]
    DIRECTION INPUT ;
    USE SIGNAL ;
    PORT
      LAYER M5 ;
        RECT  72.288 0 72.312 0.192 ;
    END
  END i_w[345]
  PIN i_w[346]
    DIRECTION INPUT ;
    USE SIGNAL ;
    PORT
      LAYER M5 ;
        RECT  72.48 0 72.504 0.192 ;
    END
  END i_w[346]
  PIN i_w[347]
    DIRECTION INPUT ;
    USE SIGNAL ;
    PORT
      LAYER M5 ;
        RECT  72.672 0 72.696 0.192 ;
    END
  END i_w[347]
  PIN i_w[348]
    DIRECTION INPUT ;
    USE SIGNAL ;
    PORT
      LAYER M5 ;
        RECT  72.864 0 72.888 0.192 ;
    END
  END i_w[348]
  PIN i_w[349]
    DIRECTION INPUT ;
    USE SIGNAL ;
    PORT
      LAYER M5 ;
        RECT  73.056 0 73.08 0.192 ;
    END
  END i_w[349]
  PIN i_w[34]
    DIRECTION INPUT ;
    USE SIGNAL ;
    PORT
      LAYER M5 ;
        RECT  12.576 0 12.6 0.192 ;
    END
  END i_w[34]
  PIN i_w[350]
    DIRECTION INPUT ;
    USE SIGNAL ;
    PORT
      LAYER M5 ;
        RECT  73.248 0 73.272 0.192 ;
    END
  END i_w[350]
  PIN i_w[351]
    DIRECTION INPUT ;
    USE SIGNAL ;
    PORT
      LAYER M5 ;
        RECT  73.44 0 73.464 0.192 ;
    END
  END i_w[351]
  PIN i_w[352]
    DIRECTION INPUT ;
    USE SIGNAL ;
    PORT
      LAYER M5 ;
        RECT  73.632 0 73.656 0.192 ;
    END
  END i_w[352]
  PIN i_w[353]
    DIRECTION INPUT ;
    USE SIGNAL ;
    PORT
      LAYER M5 ;
        RECT  73.824 0 73.848 0.192 ;
    END
  END i_w[353]
  PIN i_w[354]
    DIRECTION INPUT ;
    USE SIGNAL ;
    PORT
      LAYER M5 ;
        RECT  74.016 0 74.04 0.192 ;
    END
  END i_w[354]
  PIN i_w[355]
    DIRECTION INPUT ;
    USE SIGNAL ;
    PORT
      LAYER M5 ;
        RECT  74.208 0 74.232 0.192 ;
    END
  END i_w[355]
  PIN i_w[356]
    DIRECTION INPUT ;
    USE SIGNAL ;
    PORT
      LAYER M5 ;
        RECT  74.4 0 74.424 0.192 ;
    END
  END i_w[356]
  PIN i_w[357]
    DIRECTION INPUT ;
    USE SIGNAL ;
    PORT
      LAYER M5 ;
        RECT  74.592 0 74.616 0.192 ;
    END
  END i_w[357]
  PIN i_w[358]
    DIRECTION INPUT ;
    USE SIGNAL ;
    PORT
      LAYER M5 ;
        RECT  74.784 0 74.808 0.192 ;
    END
  END i_w[358]
  PIN i_w[359]
    DIRECTION INPUT ;
    USE SIGNAL ;
    PORT
      LAYER M5 ;
        RECT  74.976 0 75 0.192 ;
    END
  END i_w[359]
  PIN i_w[35]
    DIRECTION INPUT ;
    USE SIGNAL ;
    PORT
      LAYER M5 ;
        RECT  12.768 0 12.792 0.192 ;
    END
  END i_w[35]
  PIN i_w[360]
    DIRECTION INPUT ;
    USE SIGNAL ;
    PORT
      LAYER M5 ;
        RECT  75.168 0 75.192 0.192 ;
    END
  END i_w[360]
  PIN i_w[361]
    DIRECTION INPUT ;
    USE SIGNAL ;
    PORT
      LAYER M5 ;
        RECT  75.36 0 75.384 0.192 ;
    END
  END i_w[361]
  PIN i_w[362]
    DIRECTION INPUT ;
    USE SIGNAL ;
    PORT
      LAYER M5 ;
        RECT  75.552 0 75.576 0.192 ;
    END
  END i_w[362]
  PIN i_w[363]
    DIRECTION INPUT ;
    USE SIGNAL ;
    PORT
      LAYER M5 ;
        RECT  75.744 0 75.768 0.192 ;
    END
  END i_w[363]
  PIN i_w[364]
    DIRECTION INPUT ;
    USE SIGNAL ;
    PORT
      LAYER M5 ;
        RECT  75.936 0 75.96 0.192 ;
    END
  END i_w[364]
  PIN i_w[365]
    DIRECTION INPUT ;
    USE SIGNAL ;
    PORT
      LAYER M5 ;
        RECT  76.128 0 76.152 0.192 ;
    END
  END i_w[365]
  PIN i_w[366]
    DIRECTION INPUT ;
    USE SIGNAL ;
    PORT
      LAYER M5 ;
        RECT  76.32 0 76.344 0.192 ;
    END
  END i_w[366]
  PIN i_w[367]
    DIRECTION INPUT ;
    USE SIGNAL ;
    PORT
      LAYER M5 ;
        RECT  76.512 0 76.536 0.192 ;
    END
  END i_w[367]
  PIN i_w[368]
    DIRECTION INPUT ;
    USE SIGNAL ;
    PORT
      LAYER M5 ;
        RECT  76.704 0 76.728 0.192 ;
    END
  END i_w[368]
  PIN i_w[369]
    DIRECTION INPUT ;
    USE SIGNAL ;
    PORT
      LAYER M5 ;
        RECT  76.896 0 76.92 0.192 ;
    END
  END i_w[369]
  PIN i_w[36]
    DIRECTION INPUT ;
    USE SIGNAL ;
    PORT
      LAYER M5 ;
        RECT  12.96 0 12.984 0.192 ;
    END
  END i_w[36]
  PIN i_w[370]
    DIRECTION INPUT ;
    USE SIGNAL ;
    PORT
      LAYER M5 ;
        RECT  77.088 0 77.112 0.192 ;
    END
  END i_w[370]
  PIN i_w[371]
    DIRECTION INPUT ;
    USE SIGNAL ;
    PORT
      LAYER M5 ;
        RECT  77.28 0 77.304 0.192 ;
    END
  END i_w[371]
  PIN i_w[372]
    DIRECTION INPUT ;
    USE SIGNAL ;
    PORT
      LAYER M5 ;
        RECT  77.472 0 77.496 0.192 ;
    END
  END i_w[372]
  PIN i_w[373]
    DIRECTION INPUT ;
    USE SIGNAL ;
    PORT
      LAYER M5 ;
        RECT  77.664 0 77.688 0.192 ;
    END
  END i_w[373]
  PIN i_w[374]
    DIRECTION INPUT ;
    USE SIGNAL ;
    PORT
      LAYER M5 ;
        RECT  77.856 0 77.88 0.192 ;
    END
  END i_w[374]
  PIN i_w[375]
    DIRECTION INPUT ;
    USE SIGNAL ;
    PORT
      LAYER M5 ;
        RECT  78.048 0 78.072 0.192 ;
    END
  END i_w[375]
  PIN i_w[376]
    DIRECTION INPUT ;
    USE SIGNAL ;
    PORT
      LAYER M5 ;
        RECT  78.24 0 78.264 0.192 ;
    END
  END i_w[376]
  PIN i_w[377]
    DIRECTION INPUT ;
    USE SIGNAL ;
    PORT
      LAYER M5 ;
        RECT  78.432 0 78.456 0.192 ;
    END
  END i_w[377]
  PIN i_w[378]
    DIRECTION INPUT ;
    USE SIGNAL ;
    PORT
      LAYER M5 ;
        RECT  78.624 0 78.648 0.192 ;
    END
  END i_w[378]
  PIN i_w[379]
    DIRECTION INPUT ;
    USE SIGNAL ;
    PORT
      LAYER M5 ;
        RECT  78.816 0 78.84 0.192 ;
    END
  END i_w[379]
  PIN i_w[37]
    DIRECTION INPUT ;
    USE SIGNAL ;
    PORT
      LAYER M5 ;
        RECT  13.152 0 13.176 0.192 ;
    END
  END i_w[37]
  PIN i_w[380]
    DIRECTION INPUT ;
    USE SIGNAL ;
    PORT
      LAYER M5 ;
        RECT  79.008 0 79.032 0.192 ;
    END
  END i_w[380]
  PIN i_w[381]
    DIRECTION INPUT ;
    USE SIGNAL ;
    PORT
      LAYER M5 ;
        RECT  79.2 0 79.224 0.192 ;
    END
  END i_w[381]
  PIN i_w[382]
    DIRECTION INPUT ;
    USE SIGNAL ;
    PORT
      LAYER M5 ;
        RECT  79.392 0 79.416 0.192 ;
    END
  END i_w[382]
  PIN i_w[383]
    DIRECTION INPUT ;
    USE SIGNAL ;
    PORT
      LAYER M5 ;
        RECT  79.584 0 79.608 0.192 ;
    END
  END i_w[383]
  PIN i_w[384]
    DIRECTION INPUT ;
    USE SIGNAL ;
    PORT
      LAYER M5 ;
        RECT  79.776 0 79.8 0.192 ;
    END
  END i_w[384]
  PIN i_w[385]
    DIRECTION INPUT ;
    USE SIGNAL ;
    PORT
      LAYER M5 ;
        RECT  79.968 0 79.992 0.192 ;
    END
  END i_w[385]
  PIN i_w[386]
    DIRECTION INPUT ;
    USE SIGNAL ;
    PORT
      LAYER M5 ;
        RECT  80.16 0 80.184 0.192 ;
    END
  END i_w[386]
  PIN i_w[387]
    DIRECTION INPUT ;
    USE SIGNAL ;
    PORT
      LAYER M5 ;
        RECT  80.352 0 80.376 0.192 ;
    END
  END i_w[387]
  PIN i_w[388]
    DIRECTION INPUT ;
    USE SIGNAL ;
    PORT
      LAYER M5 ;
        RECT  80.544 0 80.568 0.192 ;
    END
  END i_w[388]
  PIN i_w[389]
    DIRECTION INPUT ;
    USE SIGNAL ;
    PORT
      LAYER M5 ;
        RECT  80.736 0 80.76 0.192 ;
    END
  END i_w[389]
  PIN i_w[38]
    DIRECTION INPUT ;
    USE SIGNAL ;
    PORT
      LAYER M5 ;
        RECT  13.344 0 13.368 0.192 ;
    END
  END i_w[38]
  PIN i_w[390]
    DIRECTION INPUT ;
    USE SIGNAL ;
    PORT
      LAYER M5 ;
        RECT  80.928 0 80.952 0.192 ;
    END
  END i_w[390]
  PIN i_w[391]
    DIRECTION INPUT ;
    USE SIGNAL ;
    PORT
      LAYER M5 ;
        RECT  81.12 0 81.144 0.192 ;
    END
  END i_w[391]
  PIN i_w[392]
    DIRECTION INPUT ;
    USE SIGNAL ;
    PORT
      LAYER M5 ;
        RECT  81.312 0 81.336 0.192 ;
    END
  END i_w[392]
  PIN i_w[393]
    DIRECTION INPUT ;
    USE SIGNAL ;
    PORT
      LAYER M5 ;
        RECT  81.504 0 81.528 0.192 ;
    END
  END i_w[393]
  PIN i_w[394]
    DIRECTION INPUT ;
    USE SIGNAL ;
    PORT
      LAYER M5 ;
        RECT  81.696 0 81.72 0.192 ;
    END
  END i_w[394]
  PIN i_w[395]
    DIRECTION INPUT ;
    USE SIGNAL ;
    PORT
      LAYER M5 ;
        RECT  81.888 0 81.912 0.192 ;
    END
  END i_w[395]
  PIN i_w[396]
    DIRECTION INPUT ;
    USE SIGNAL ;
    PORT
      LAYER M5 ;
        RECT  82.08 0 82.104 0.192 ;
    END
  END i_w[396]
  PIN i_w[397]
    DIRECTION INPUT ;
    USE SIGNAL ;
    PORT
      LAYER M5 ;
        RECT  82.272 0 82.296 0.192 ;
    END
  END i_w[397]
  PIN i_w[398]
    DIRECTION INPUT ;
    USE SIGNAL ;
    PORT
      LAYER M5 ;
        RECT  82.464 0 82.488 0.192 ;
    END
  END i_w[398]
  PIN i_w[399]
    DIRECTION INPUT ;
    USE SIGNAL ;
    PORT
      LAYER M5 ;
        RECT  82.656 0 82.68 0.192 ;
    END
  END i_w[399]
  PIN i_w[39]
    DIRECTION INPUT ;
    USE SIGNAL ;
    PORT
      LAYER M5 ;
        RECT  13.536 0 13.56 0.192 ;
    END
  END i_w[39]
  PIN i_w[3]
    DIRECTION INPUT ;
    USE SIGNAL ;
    PORT
      LAYER M5 ;
        RECT  6.624 0 6.648 0.192 ;
    END
  END i_w[3]
  PIN i_w[400]
    DIRECTION INPUT ;
    USE SIGNAL ;
    PORT
      LAYER M5 ;
        RECT  82.848 0 82.872 0.192 ;
    END
  END i_w[400]
  PIN i_w[401]
    DIRECTION INPUT ;
    USE SIGNAL ;
    PORT
      LAYER M5 ;
        RECT  83.04 0 83.064 0.192 ;
    END
  END i_w[401]
  PIN i_w[402]
    DIRECTION INPUT ;
    USE SIGNAL ;
    PORT
      LAYER M5 ;
        RECT  83.232 0 83.256 0.192 ;
    END
  END i_w[402]
  PIN i_w[403]
    DIRECTION INPUT ;
    USE SIGNAL ;
    PORT
      LAYER M5 ;
        RECT  83.424 0 83.448 0.192 ;
    END
  END i_w[403]
  PIN i_w[404]
    DIRECTION INPUT ;
    USE SIGNAL ;
    PORT
      LAYER M5 ;
        RECT  83.616 0 83.64 0.192 ;
    END
  END i_w[404]
  PIN i_w[405]
    DIRECTION INPUT ;
    USE SIGNAL ;
    PORT
      LAYER M5 ;
        RECT  83.808 0 83.832 0.192 ;
    END
  END i_w[405]
  PIN i_w[406]
    DIRECTION INPUT ;
    USE SIGNAL ;
    PORT
      LAYER M5 ;
        RECT  84 0 84.024 0.192 ;
    END
  END i_w[406]
  PIN i_w[407]
    DIRECTION INPUT ;
    USE SIGNAL ;
    PORT
      LAYER M5 ;
        RECT  84.192 0 84.216 0.192 ;
    END
  END i_w[407]
  PIN i_w[408]
    DIRECTION INPUT ;
    USE SIGNAL ;
    PORT
      LAYER M5 ;
        RECT  84.384 0 84.408 0.192 ;
    END
  END i_w[408]
  PIN i_w[409]
    DIRECTION INPUT ;
    USE SIGNAL ;
    PORT
      LAYER M5 ;
        RECT  84.576 0 84.6 0.192 ;
    END
  END i_w[409]
  PIN i_w[40]
    DIRECTION INPUT ;
    USE SIGNAL ;
    PORT
      LAYER M5 ;
        RECT  13.728 0 13.752 0.192 ;
    END
  END i_w[40]
  PIN i_w[410]
    DIRECTION INPUT ;
    USE SIGNAL ;
    PORT
      LAYER M5 ;
        RECT  84.768 0 84.792 0.192 ;
    END
  END i_w[410]
  PIN i_w[411]
    DIRECTION INPUT ;
    USE SIGNAL ;
    PORT
      LAYER M5 ;
        RECT  84.96 0 84.984 0.192 ;
    END
  END i_w[411]
  PIN i_w[412]
    DIRECTION INPUT ;
    USE SIGNAL ;
    PORT
      LAYER M5 ;
        RECT  85.152 0 85.176 0.192 ;
    END
  END i_w[412]
  PIN i_w[413]
    DIRECTION INPUT ;
    USE SIGNAL ;
    PORT
      LAYER M5 ;
        RECT  85.344 0 85.368 0.192 ;
    END
  END i_w[413]
  PIN i_w[414]
    DIRECTION INPUT ;
    USE SIGNAL ;
    PORT
      LAYER M5 ;
        RECT  85.536 0 85.56 0.192 ;
    END
  END i_w[414]
  PIN i_w[415]
    DIRECTION INPUT ;
    USE SIGNAL ;
    PORT
      LAYER M5 ;
        RECT  85.728 0 85.752 0.192 ;
    END
  END i_w[415]
  PIN i_w[416]
    DIRECTION INPUT ;
    USE SIGNAL ;
    PORT
      LAYER M5 ;
        RECT  85.92 0 85.944 0.192 ;
    END
  END i_w[416]
  PIN i_w[417]
    DIRECTION INPUT ;
    USE SIGNAL ;
    PORT
      LAYER M5 ;
        RECT  86.112 0 86.136 0.192 ;
    END
  END i_w[417]
  PIN i_w[418]
    DIRECTION INPUT ;
    USE SIGNAL ;
    PORT
      LAYER M5 ;
        RECT  86.304 0 86.328 0.192 ;
    END
  END i_w[418]
  PIN i_w[419]
    DIRECTION INPUT ;
    USE SIGNAL ;
    PORT
      LAYER M5 ;
        RECT  86.496 0 86.52 0.192 ;
    END
  END i_w[419]
  PIN i_w[41]
    DIRECTION INPUT ;
    USE SIGNAL ;
    PORT
      LAYER M5 ;
        RECT  13.92 0 13.944 0.192 ;
    END
  END i_w[41]
  PIN i_w[420]
    DIRECTION INPUT ;
    USE SIGNAL ;
    PORT
      LAYER M5 ;
        RECT  86.688 0 86.712 0.192 ;
    END
  END i_w[420]
  PIN i_w[421]
    DIRECTION INPUT ;
    USE SIGNAL ;
    PORT
      LAYER M5 ;
        RECT  86.88 0 86.904 0.192 ;
    END
  END i_w[421]
  PIN i_w[422]
    DIRECTION INPUT ;
    USE SIGNAL ;
    PORT
      LAYER M5 ;
        RECT  87.072 0 87.096 0.192 ;
    END
  END i_w[422]
  PIN i_w[423]
    DIRECTION INPUT ;
    USE SIGNAL ;
    PORT
      LAYER M5 ;
        RECT  87.264 0 87.288 0.192 ;
    END
  END i_w[423]
  PIN i_w[424]
    DIRECTION INPUT ;
    USE SIGNAL ;
    PORT
      LAYER M5 ;
        RECT  87.456 0 87.48 0.192 ;
    END
  END i_w[424]
  PIN i_w[425]
    DIRECTION INPUT ;
    USE SIGNAL ;
    PORT
      LAYER M5 ;
        RECT  87.648 0 87.672 0.192 ;
    END
  END i_w[425]
  PIN i_w[426]
    DIRECTION INPUT ;
    USE SIGNAL ;
    PORT
      LAYER M5 ;
        RECT  87.84 0 87.864 0.192 ;
    END
  END i_w[426]
  PIN i_w[427]
    DIRECTION INPUT ;
    USE SIGNAL ;
    PORT
      LAYER M5 ;
        RECT  88.032 0 88.056 0.192 ;
    END
  END i_w[427]
  PIN i_w[428]
    DIRECTION INPUT ;
    USE SIGNAL ;
    PORT
      LAYER M5 ;
        RECT  88.224 0 88.248 0.192 ;
    END
  END i_w[428]
  PIN i_w[429]
    DIRECTION INPUT ;
    USE SIGNAL ;
    PORT
      LAYER M5 ;
        RECT  88.416 0 88.44 0.192 ;
    END
  END i_w[429]
  PIN i_w[42]
    DIRECTION INPUT ;
    USE SIGNAL ;
    PORT
      LAYER M5 ;
        RECT  14.112 0 14.136 0.192 ;
    END
  END i_w[42]
  PIN i_w[430]
    DIRECTION INPUT ;
    USE SIGNAL ;
    PORT
      LAYER M5 ;
        RECT  88.608 0 88.632 0.192 ;
    END
  END i_w[430]
  PIN i_w[431]
    DIRECTION INPUT ;
    USE SIGNAL ;
    PORT
      LAYER M5 ;
        RECT  88.8 0 88.824 0.192 ;
    END
  END i_w[431]
  PIN i_w[432]
    DIRECTION INPUT ;
    USE SIGNAL ;
    PORT
      LAYER M5 ;
        RECT  88.992 0 89.016 0.192 ;
    END
  END i_w[432]
  PIN i_w[433]
    DIRECTION INPUT ;
    USE SIGNAL ;
    PORT
      LAYER M5 ;
        RECT  89.184 0 89.208 0.192 ;
    END
  END i_w[433]
  PIN i_w[434]
    DIRECTION INPUT ;
    USE SIGNAL ;
    PORT
      LAYER M5 ;
        RECT  89.376 0 89.4 0.192 ;
    END
  END i_w[434]
  PIN i_w[435]
    DIRECTION INPUT ;
    USE SIGNAL ;
    PORT
      LAYER M5 ;
        RECT  89.568 0 89.592 0.192 ;
    END
  END i_w[435]
  PIN i_w[436]
    DIRECTION INPUT ;
    USE SIGNAL ;
    PORT
      LAYER M5 ;
        RECT  89.76 0 89.784 0.192 ;
    END
  END i_w[436]
  PIN i_w[437]
    DIRECTION INPUT ;
    USE SIGNAL ;
    PORT
      LAYER M5 ;
        RECT  89.952 0 89.976 0.192 ;
    END
  END i_w[437]
  PIN i_w[438]
    DIRECTION INPUT ;
    USE SIGNAL ;
    PORT
      LAYER M5 ;
        RECT  90.144 0 90.168 0.192 ;
    END
  END i_w[438]
  PIN i_w[439]
    DIRECTION INPUT ;
    USE SIGNAL ;
    PORT
      LAYER M5 ;
        RECT  90.336 0 90.36 0.192 ;
    END
  END i_w[439]
  PIN i_w[43]
    DIRECTION INPUT ;
    USE SIGNAL ;
    PORT
      LAYER M5 ;
        RECT  14.304 0 14.328 0.192 ;
    END
  END i_w[43]
  PIN i_w[440]
    DIRECTION INPUT ;
    USE SIGNAL ;
    PORT
      LAYER M5 ;
        RECT  90.528 0 90.552 0.192 ;
    END
  END i_w[440]
  PIN i_w[441]
    DIRECTION INPUT ;
    USE SIGNAL ;
    PORT
      LAYER M5 ;
        RECT  90.72 0 90.744 0.192 ;
    END
  END i_w[441]
  PIN i_w[442]
    DIRECTION INPUT ;
    USE SIGNAL ;
    PORT
      LAYER M5 ;
        RECT  90.912 0 90.936 0.192 ;
    END
  END i_w[442]
  PIN i_w[443]
    DIRECTION INPUT ;
    USE SIGNAL ;
    PORT
      LAYER M5 ;
        RECT  91.104 0 91.128 0.192 ;
    END
  END i_w[443]
  PIN i_w[444]
    DIRECTION INPUT ;
    USE SIGNAL ;
    PORT
      LAYER M5 ;
        RECT  91.296 0 91.32 0.192 ;
    END
  END i_w[444]
  PIN i_w[445]
    DIRECTION INPUT ;
    USE SIGNAL ;
    PORT
      LAYER M5 ;
        RECT  91.488 0 91.512 0.192 ;
    END
  END i_w[445]
  PIN i_w[446]
    DIRECTION INPUT ;
    USE SIGNAL ;
    PORT
      LAYER M5 ;
        RECT  91.68 0 91.704 0.192 ;
    END
  END i_w[446]
  PIN i_w[447]
    DIRECTION INPUT ;
    USE SIGNAL ;
    PORT
      LAYER M5 ;
        RECT  91.872 0 91.896 0.192 ;
    END
  END i_w[447]
  PIN i_w[448]
    DIRECTION INPUT ;
    USE SIGNAL ;
    PORT
      LAYER M5 ;
        RECT  92.064 0 92.088 0.192 ;
    END
  END i_w[448]
  PIN i_w[449]
    DIRECTION INPUT ;
    USE SIGNAL ;
    PORT
      LAYER M5 ;
        RECT  92.256 0 92.28 0.192 ;
    END
  END i_w[449]
  PIN i_w[44]
    DIRECTION INPUT ;
    USE SIGNAL ;
    PORT
      LAYER M5 ;
        RECT  14.496 0 14.52 0.192 ;
    END
  END i_w[44]
  PIN i_w[450]
    DIRECTION INPUT ;
    USE SIGNAL ;
    PORT
      LAYER M5 ;
        RECT  92.448 0 92.472 0.192 ;
    END
  END i_w[450]
  PIN i_w[451]
    DIRECTION INPUT ;
    USE SIGNAL ;
    PORT
      LAYER M5 ;
        RECT  92.64 0 92.664 0.192 ;
    END
  END i_w[451]
  PIN i_w[452]
    DIRECTION INPUT ;
    USE SIGNAL ;
    PORT
      LAYER M5 ;
        RECT  92.832 0 92.856 0.192 ;
    END
  END i_w[452]
  PIN i_w[453]
    DIRECTION INPUT ;
    USE SIGNAL ;
    PORT
      LAYER M5 ;
        RECT  93.024 0 93.048 0.192 ;
    END
  END i_w[453]
  PIN i_w[454]
    DIRECTION INPUT ;
    USE SIGNAL ;
    PORT
      LAYER M5 ;
        RECT  93.216 0 93.24 0.192 ;
    END
  END i_w[454]
  PIN i_w[455]
    DIRECTION INPUT ;
    USE SIGNAL ;
    PORT
      LAYER M5 ;
        RECT  93.408 0 93.432 0.192 ;
    END
  END i_w[455]
  PIN i_w[456]
    DIRECTION INPUT ;
    USE SIGNAL ;
    PORT
      LAYER M5 ;
        RECT  93.6 0 93.624 0.192 ;
    END
  END i_w[456]
  PIN i_w[457]
    DIRECTION INPUT ;
    USE SIGNAL ;
    PORT
      LAYER M5 ;
        RECT  93.792 0 93.816 0.192 ;
    END
  END i_w[457]
  PIN i_w[458]
    DIRECTION INPUT ;
    USE SIGNAL ;
    PORT
      LAYER M5 ;
        RECT  93.984 0 94.008 0.192 ;
    END
  END i_w[458]
  PIN i_w[459]
    DIRECTION INPUT ;
    USE SIGNAL ;
    PORT
      LAYER M5 ;
        RECT  94.176 0 94.2 0.192 ;
    END
  END i_w[459]
  PIN i_w[45]
    DIRECTION INPUT ;
    USE SIGNAL ;
    PORT
      LAYER M5 ;
        RECT  14.688 0 14.712 0.192 ;
    END
  END i_w[45]
  PIN i_w[460]
    DIRECTION INPUT ;
    USE SIGNAL ;
    PORT
      LAYER M5 ;
        RECT  94.368 0 94.392 0.192 ;
    END
  END i_w[460]
  PIN i_w[461]
    DIRECTION INPUT ;
    USE SIGNAL ;
    PORT
      LAYER M5 ;
        RECT  94.56 0 94.584 0.192 ;
    END
  END i_w[461]
  PIN i_w[462]
    DIRECTION INPUT ;
    USE SIGNAL ;
    PORT
      LAYER M5 ;
        RECT  94.752 0 94.776 0.192 ;
    END
  END i_w[462]
  PIN i_w[463]
    DIRECTION INPUT ;
    USE SIGNAL ;
    PORT
      LAYER M5 ;
        RECT  94.944 0 94.968 0.192 ;
    END
  END i_w[463]
  PIN i_w[464]
    DIRECTION INPUT ;
    USE SIGNAL ;
    PORT
      LAYER M5 ;
        RECT  95.136 0 95.16 0.192 ;
    END
  END i_w[464]
  PIN i_w[465]
    DIRECTION INPUT ;
    USE SIGNAL ;
    PORT
      LAYER M5 ;
        RECT  95.328 0 95.352 0.192 ;
    END
  END i_w[465]
  PIN i_w[466]
    DIRECTION INPUT ;
    USE SIGNAL ;
    PORT
      LAYER M5 ;
        RECT  95.52 0 95.544 0.192 ;
    END
  END i_w[466]
  PIN i_w[467]
    DIRECTION INPUT ;
    USE SIGNAL ;
    PORT
      LAYER M5 ;
        RECT  95.712 0 95.736 0.192 ;
    END
  END i_w[467]
  PIN i_w[468]
    DIRECTION INPUT ;
    USE SIGNAL ;
    PORT
      LAYER M5 ;
        RECT  95.904 0 95.928 0.192 ;
    END
  END i_w[468]
  PIN i_w[469]
    DIRECTION INPUT ;
    USE SIGNAL ;
    PORT
      LAYER M5 ;
        RECT  96.096 0 96.12 0.192 ;
    END
  END i_w[469]
  PIN i_w[46]
    DIRECTION INPUT ;
    USE SIGNAL ;
    PORT
      LAYER M5 ;
        RECT  14.88 0 14.904 0.192 ;
    END
  END i_w[46]
  PIN i_w[470]
    DIRECTION INPUT ;
    USE SIGNAL ;
    PORT
      LAYER M5 ;
        RECT  96.288 0 96.312 0.192 ;
    END
  END i_w[470]
  PIN i_w[471]
    DIRECTION INPUT ;
    USE SIGNAL ;
    PORT
      LAYER M5 ;
        RECT  96.48 0 96.504 0.192 ;
    END
  END i_w[471]
  PIN i_w[472]
    DIRECTION INPUT ;
    USE SIGNAL ;
    PORT
      LAYER M5 ;
        RECT  96.672 0 96.696 0.192 ;
    END
  END i_w[472]
  PIN i_w[473]
    DIRECTION INPUT ;
    USE SIGNAL ;
    PORT
      LAYER M5 ;
        RECT  96.864 0 96.888 0.192 ;
    END
  END i_w[473]
  PIN i_w[474]
    DIRECTION INPUT ;
    USE SIGNAL ;
    PORT
      LAYER M5 ;
        RECT  97.056 0 97.08 0.192 ;
    END
  END i_w[474]
  PIN i_w[475]
    DIRECTION INPUT ;
    USE SIGNAL ;
    PORT
      LAYER M5 ;
        RECT  97.248 0 97.272 0.192 ;
    END
  END i_w[475]
  PIN i_w[476]
    DIRECTION INPUT ;
    USE SIGNAL ;
    PORT
      LAYER M5 ;
        RECT  97.44 0 97.464 0.192 ;
    END
  END i_w[476]
  PIN i_w[477]
    DIRECTION INPUT ;
    USE SIGNAL ;
    PORT
      LAYER M5 ;
        RECT  97.632 0 97.656 0.192 ;
    END
  END i_w[477]
  PIN i_w[478]
    DIRECTION INPUT ;
    USE SIGNAL ;
    PORT
      LAYER M5 ;
        RECT  97.824 0 97.848 0.192 ;
    END
  END i_w[478]
  PIN i_w[479]
    DIRECTION INPUT ;
    USE SIGNAL ;
    PORT
      LAYER M5 ;
        RECT  98.016 0 98.04 0.192 ;
    END
  END i_w[479]
  PIN i_w[47]
    DIRECTION INPUT ;
    USE SIGNAL ;
    PORT
      LAYER M5 ;
        RECT  15.072 0 15.096 0.192 ;
    END
  END i_w[47]
  PIN i_w[480]
    DIRECTION INPUT ;
    USE SIGNAL ;
    PORT
      LAYER M5 ;
        RECT  98.208 0 98.232 0.192 ;
    END
  END i_w[480]
  PIN i_w[481]
    DIRECTION INPUT ;
    USE SIGNAL ;
    PORT
      LAYER M5 ;
        RECT  98.4 0 98.424 0.192 ;
    END
  END i_w[481]
  PIN i_w[482]
    DIRECTION INPUT ;
    USE SIGNAL ;
    PORT
      LAYER M5 ;
        RECT  98.592 0 98.616 0.192 ;
    END
  END i_w[482]
  PIN i_w[483]
    DIRECTION INPUT ;
    USE SIGNAL ;
    PORT
      LAYER M5 ;
        RECT  98.784 0 98.808 0.192 ;
    END
  END i_w[483]
  PIN i_w[484]
    DIRECTION INPUT ;
    USE SIGNAL ;
    PORT
      LAYER M5 ;
        RECT  98.976 0 99 0.192 ;
    END
  END i_w[484]
  PIN i_w[485]
    DIRECTION INPUT ;
    USE SIGNAL ;
    PORT
      LAYER M5 ;
        RECT  99.168 0 99.192 0.192 ;
    END
  END i_w[485]
  PIN i_w[486]
    DIRECTION INPUT ;
    USE SIGNAL ;
    PORT
      LAYER M5 ;
        RECT  99.36 0 99.384 0.192 ;
    END
  END i_w[486]
  PIN i_w[487]
    DIRECTION INPUT ;
    USE SIGNAL ;
    PORT
      LAYER M5 ;
        RECT  99.552 0 99.576 0.192 ;
    END
  END i_w[487]
  PIN i_w[488]
    DIRECTION INPUT ;
    USE SIGNAL ;
    PORT
      LAYER M5 ;
        RECT  99.744 0 99.768 0.192 ;
    END
  END i_w[488]
  PIN i_w[489]
    DIRECTION INPUT ;
    USE SIGNAL ;
    PORT
      LAYER M5 ;
        RECT  99.936 0 99.96 0.192 ;
    END
  END i_w[489]
  PIN i_w[48]
    DIRECTION INPUT ;
    USE SIGNAL ;
    PORT
      LAYER M5 ;
        RECT  15.264 0 15.288 0.192 ;
    END
  END i_w[48]
  PIN i_w[490]
    DIRECTION INPUT ;
    USE SIGNAL ;
    PORT
      LAYER M5 ;
        RECT  100.128 0 100.152 0.192 ;
    END
  END i_w[490]
  PIN i_w[491]
    DIRECTION INPUT ;
    USE SIGNAL ;
    PORT
      LAYER M5 ;
        RECT  100.32 0 100.344 0.192 ;
    END
  END i_w[491]
  PIN i_w[492]
    DIRECTION INPUT ;
    USE SIGNAL ;
    PORT
      LAYER M5 ;
        RECT  100.512 0 100.536 0.192 ;
    END
  END i_w[492]
  PIN i_w[493]
    DIRECTION INPUT ;
    USE SIGNAL ;
    PORT
      LAYER M5 ;
        RECT  100.704 0 100.728 0.192 ;
    END
  END i_w[493]
  PIN i_w[494]
    DIRECTION INPUT ;
    USE SIGNAL ;
    PORT
      LAYER M5 ;
        RECT  100.896 0 100.92 0.192 ;
    END
  END i_w[494]
  PIN i_w[495]
    DIRECTION INPUT ;
    USE SIGNAL ;
    PORT
      LAYER M5 ;
        RECT  101.088 0 101.112 0.192 ;
    END
  END i_w[495]
  PIN i_w[496]
    DIRECTION INPUT ;
    USE SIGNAL ;
    PORT
      LAYER M5 ;
        RECT  101.28 0 101.304 0.192 ;
    END
  END i_w[496]
  PIN i_w[497]
    DIRECTION INPUT ;
    USE SIGNAL ;
    PORT
      LAYER M5 ;
        RECT  101.472 0 101.496 0.192 ;
    END
  END i_w[497]
  PIN i_w[498]
    DIRECTION INPUT ;
    USE SIGNAL ;
    PORT
      LAYER M5 ;
        RECT  101.664 0 101.688 0.192 ;
    END
  END i_w[498]
  PIN i_w[499]
    DIRECTION INPUT ;
    USE SIGNAL ;
    PORT
      LAYER M5 ;
        RECT  101.856 0 101.88 0.192 ;
    END
  END i_w[499]
  PIN i_w[49]
    DIRECTION INPUT ;
    USE SIGNAL ;
    PORT
      LAYER M5 ;
        RECT  15.456 0 15.48 0.192 ;
    END
  END i_w[49]
  PIN i_w[4]
    DIRECTION INPUT ;
    USE SIGNAL ;
    PORT
      LAYER M5 ;
        RECT  6.816 0 6.84 0.192 ;
    END
  END i_w[4]
  PIN i_w[500]
    DIRECTION INPUT ;
    USE SIGNAL ;
    PORT
      LAYER M5 ;
        RECT  102.048 0 102.072 0.192 ;
    END
  END i_w[500]
  PIN i_w[501]
    DIRECTION INPUT ;
    USE SIGNAL ;
    PORT
      LAYER M5 ;
        RECT  102.24 0 102.264 0.192 ;
    END
  END i_w[501]
  PIN i_w[502]
    DIRECTION INPUT ;
    USE SIGNAL ;
    PORT
      LAYER M5 ;
        RECT  102.432 0 102.456 0.192 ;
    END
  END i_w[502]
  PIN i_w[503]
    DIRECTION INPUT ;
    USE SIGNAL ;
    PORT
      LAYER M5 ;
        RECT  102.624 0 102.648 0.192 ;
    END
  END i_w[503]
  PIN i_w[504]
    DIRECTION INPUT ;
    USE SIGNAL ;
    PORT
      LAYER M5 ;
        RECT  102.816 0 102.84 0.192 ;
    END
  END i_w[504]
  PIN i_w[505]
    DIRECTION INPUT ;
    USE SIGNAL ;
    PORT
      LAYER M5 ;
        RECT  103.008 0 103.032 0.192 ;
    END
  END i_w[505]
  PIN i_w[506]
    DIRECTION INPUT ;
    USE SIGNAL ;
    PORT
      LAYER M5 ;
        RECT  103.2 0 103.224 0.192 ;
    END
  END i_w[506]
  PIN i_w[507]
    DIRECTION INPUT ;
    USE SIGNAL ;
    PORT
      LAYER M5 ;
        RECT  103.392 0 103.416 0.192 ;
    END
  END i_w[507]
  PIN i_w[508]
    DIRECTION INPUT ;
    USE SIGNAL ;
    PORT
      LAYER M5 ;
        RECT  103.584 0 103.608 0.192 ;
    END
  END i_w[508]
  PIN i_w[509]
    DIRECTION INPUT ;
    USE SIGNAL ;
    PORT
      LAYER M5 ;
        RECT  103.776 0 103.8 0.192 ;
    END
  END i_w[509]
  PIN i_w[50]
    DIRECTION INPUT ;
    USE SIGNAL ;
    PORT
      LAYER M5 ;
        RECT  15.648 0 15.672 0.192 ;
    END
  END i_w[50]
  PIN i_w[510]
    DIRECTION INPUT ;
    USE SIGNAL ;
    PORT
      LAYER M5 ;
        RECT  103.968 0 103.992 0.192 ;
    END
  END i_w[510]
  PIN i_w[511]
    DIRECTION INPUT ;
    USE SIGNAL ;
    PORT
      LAYER M5 ;
        RECT  104.16 0 104.184 0.192 ;
    END
  END i_w[511]
  PIN i_w[512]
    DIRECTION INPUT ;
    USE SIGNAL ;
    PORT
      LAYER M5 ;
        RECT  104.352 0 104.376 0.192 ;
    END
  END i_w[512]
  PIN i_w[513]
    DIRECTION INPUT ;
    USE SIGNAL ;
    PORT
      LAYER M5 ;
        RECT  104.544 0 104.568 0.192 ;
    END
  END i_w[513]
  PIN i_w[514]
    DIRECTION INPUT ;
    USE SIGNAL ;
    PORT
      LAYER M5 ;
        RECT  104.736 0 104.76 0.192 ;
    END
  END i_w[514]
  PIN i_w[515]
    DIRECTION INPUT ;
    USE SIGNAL ;
    PORT
      LAYER M5 ;
        RECT  104.928 0 104.952 0.192 ;
    END
  END i_w[515]
  PIN i_w[516]
    DIRECTION INPUT ;
    USE SIGNAL ;
    PORT
      LAYER M5 ;
        RECT  105.12 0 105.144 0.192 ;
    END
  END i_w[516]
  PIN i_w[517]
    DIRECTION INPUT ;
    USE SIGNAL ;
    PORT
      LAYER M5 ;
        RECT  105.312 0 105.336 0.192 ;
    END
  END i_w[517]
  PIN i_w[518]
    DIRECTION INPUT ;
    USE SIGNAL ;
    PORT
      LAYER M5 ;
        RECT  105.504 0 105.528 0.192 ;
    END
  END i_w[518]
  PIN i_w[519]
    DIRECTION INPUT ;
    USE SIGNAL ;
    PORT
      LAYER M5 ;
        RECT  105.696 0 105.72 0.192 ;
    END
  END i_w[519]
  PIN i_w[51]
    DIRECTION INPUT ;
    USE SIGNAL ;
    PORT
      LAYER M5 ;
        RECT  15.84 0 15.864 0.192 ;
    END
  END i_w[51]
  PIN i_w[520]
    DIRECTION INPUT ;
    USE SIGNAL ;
    PORT
      LAYER M5 ;
        RECT  105.888 0 105.912 0.192 ;
    END
  END i_w[520]
  PIN i_w[521]
    DIRECTION INPUT ;
    USE SIGNAL ;
    PORT
      LAYER M5 ;
        RECT  106.08 0 106.104 0.192 ;
    END
  END i_w[521]
  PIN i_w[522]
    DIRECTION INPUT ;
    USE SIGNAL ;
    PORT
      LAYER M5 ;
        RECT  106.272 0 106.296 0.192 ;
    END
  END i_w[522]
  PIN i_w[523]
    DIRECTION INPUT ;
    USE SIGNAL ;
    PORT
      LAYER M5 ;
        RECT  106.464 0 106.488 0.192 ;
    END
  END i_w[523]
  PIN i_w[524]
    DIRECTION INPUT ;
    USE SIGNAL ;
    PORT
      LAYER M5 ;
        RECT  106.656 0 106.68 0.192 ;
    END
  END i_w[524]
  PIN i_w[525]
    DIRECTION INPUT ;
    USE SIGNAL ;
    PORT
      LAYER M5 ;
        RECT  106.848 0 106.872 0.192 ;
    END
  END i_w[525]
  PIN i_w[526]
    DIRECTION INPUT ;
    USE SIGNAL ;
    PORT
      LAYER M5 ;
        RECT  107.04 0 107.064 0.192 ;
    END
  END i_w[526]
  PIN i_w[527]
    DIRECTION INPUT ;
    USE SIGNAL ;
    PORT
      LAYER M5 ;
        RECT  107.232 0 107.256 0.192 ;
    END
  END i_w[527]
  PIN i_w[528]
    DIRECTION INPUT ;
    USE SIGNAL ;
    PORT
      LAYER M5 ;
        RECT  107.424 0 107.448 0.192 ;
    END
  END i_w[528]
  PIN i_w[529]
    DIRECTION INPUT ;
    USE SIGNAL ;
    PORT
      LAYER M5 ;
        RECT  107.616 0 107.64 0.192 ;
    END
  END i_w[529]
  PIN i_w[52]
    DIRECTION INPUT ;
    USE SIGNAL ;
    PORT
      LAYER M5 ;
        RECT  16.032 0 16.056 0.192 ;
    END
  END i_w[52]
  PIN i_w[530]
    DIRECTION INPUT ;
    USE SIGNAL ;
    PORT
      LAYER M5 ;
        RECT  107.808 0 107.832 0.192 ;
    END
  END i_w[530]
  PIN i_w[531]
    DIRECTION INPUT ;
    USE SIGNAL ;
    PORT
      LAYER M5 ;
        RECT  108 0 108.024 0.192 ;
    END
  END i_w[531]
  PIN i_w[53]
    DIRECTION INPUT ;
    USE SIGNAL ;
    PORT
      LAYER M5 ;
        RECT  16.224 0 16.248 0.192 ;
    END
  END i_w[53]
  PIN i_w[54]
    DIRECTION INPUT ;
    USE SIGNAL ;
    PORT
      LAYER M5 ;
        RECT  16.416 0 16.44 0.192 ;
    END
  END i_w[54]
  PIN i_w[55]
    DIRECTION INPUT ;
    USE SIGNAL ;
    PORT
      LAYER M5 ;
        RECT  16.608 0 16.632 0.192 ;
    END
  END i_w[55]
  PIN i_w[56]
    DIRECTION INPUT ;
    USE SIGNAL ;
    PORT
      LAYER M5 ;
        RECT  16.8 0 16.824 0.192 ;
    END
  END i_w[56]
  PIN i_w[57]
    DIRECTION INPUT ;
    USE SIGNAL ;
    PORT
      LAYER M5 ;
        RECT  16.992 0 17.016 0.192 ;
    END
  END i_w[57]
  PIN i_w[58]
    DIRECTION INPUT ;
    USE SIGNAL ;
    PORT
      LAYER M5 ;
        RECT  17.184 0 17.208 0.192 ;
    END
  END i_w[58]
  PIN i_w[59]
    DIRECTION INPUT ;
    USE SIGNAL ;
    PORT
      LAYER M5 ;
        RECT  17.376 0 17.4 0.192 ;
    END
  END i_w[59]
  PIN i_w[5]
    DIRECTION INPUT ;
    USE SIGNAL ;
    PORT
      LAYER M5 ;
        RECT  7.008 0 7.032 0.192 ;
    END
  END i_w[5]
  PIN i_w[60]
    DIRECTION INPUT ;
    USE SIGNAL ;
    PORT
      LAYER M5 ;
        RECT  17.568 0 17.592 0.192 ;
    END
  END i_w[60]
  PIN i_w[61]
    DIRECTION INPUT ;
    USE SIGNAL ;
    PORT
      LAYER M5 ;
        RECT  17.76 0 17.784 0.192 ;
    END
  END i_w[61]
  PIN i_w[62]
    DIRECTION INPUT ;
    USE SIGNAL ;
    PORT
      LAYER M5 ;
        RECT  17.952 0 17.976 0.192 ;
    END
  END i_w[62]
  PIN i_w[63]
    DIRECTION INPUT ;
    USE SIGNAL ;
    PORT
      LAYER M5 ;
        RECT  18.144 0 18.168 0.192 ;
    END
  END i_w[63]
  PIN i_w[64]
    DIRECTION INPUT ;
    USE SIGNAL ;
    PORT
      LAYER M5 ;
        RECT  18.336 0 18.36 0.192 ;
    END
  END i_w[64]
  PIN i_w[65]
    DIRECTION INPUT ;
    USE SIGNAL ;
    PORT
      LAYER M5 ;
        RECT  18.528 0 18.552 0.192 ;
    END
  END i_w[65]
  PIN i_w[66]
    DIRECTION INPUT ;
    USE SIGNAL ;
    PORT
      LAYER M5 ;
        RECT  18.72 0 18.744 0.192 ;
    END
  END i_w[66]
  PIN i_w[67]
    DIRECTION INPUT ;
    USE SIGNAL ;
    PORT
      LAYER M5 ;
        RECT  18.912 0 18.936 0.192 ;
    END
  END i_w[67]
  PIN i_w[68]
    DIRECTION INPUT ;
    USE SIGNAL ;
    PORT
      LAYER M5 ;
        RECT  19.104 0 19.128 0.192 ;
    END
  END i_w[68]
  PIN i_w[69]
    DIRECTION INPUT ;
    USE SIGNAL ;
    PORT
      LAYER M5 ;
        RECT  19.296 0 19.32 0.192 ;
    END
  END i_w[69]
  PIN i_w[6]
    DIRECTION INPUT ;
    USE SIGNAL ;
    PORT
      LAYER M5 ;
        RECT  7.2 0 7.224 0.192 ;
    END
  END i_w[6]
  PIN i_w[70]
    DIRECTION INPUT ;
    USE SIGNAL ;
    PORT
      LAYER M5 ;
        RECT  19.488 0 19.512 0.192 ;
    END
  END i_w[70]
  PIN i_w[71]
    DIRECTION INPUT ;
    USE SIGNAL ;
    PORT
      LAYER M5 ;
        RECT  19.68 0 19.704 0.192 ;
    END
  END i_w[71]
  PIN i_w[72]
    DIRECTION INPUT ;
    USE SIGNAL ;
    PORT
      LAYER M5 ;
        RECT  19.872 0 19.896 0.192 ;
    END
  END i_w[72]
  PIN i_w[73]
    DIRECTION INPUT ;
    USE SIGNAL ;
    PORT
      LAYER M5 ;
        RECT  20.064 0 20.088 0.192 ;
    END
  END i_w[73]
  PIN i_w[74]
    DIRECTION INPUT ;
    USE SIGNAL ;
    PORT
      LAYER M5 ;
        RECT  20.256 0 20.28 0.192 ;
    END
  END i_w[74]
  PIN i_w[75]
    DIRECTION INPUT ;
    USE SIGNAL ;
    PORT
      LAYER M5 ;
        RECT  20.448 0 20.472 0.192 ;
    END
  END i_w[75]
  PIN i_w[76]
    DIRECTION INPUT ;
    USE SIGNAL ;
    PORT
      LAYER M5 ;
        RECT  20.64 0 20.664 0.192 ;
    END
  END i_w[76]
  PIN i_w[77]
    DIRECTION INPUT ;
    USE SIGNAL ;
    PORT
      LAYER M5 ;
        RECT  20.832 0 20.856 0.192 ;
    END
  END i_w[77]
  PIN i_w[78]
    DIRECTION INPUT ;
    USE SIGNAL ;
    PORT
      LAYER M5 ;
        RECT  21.024 0 21.048 0.192 ;
    END
  END i_w[78]
  PIN i_w[79]
    DIRECTION INPUT ;
    USE SIGNAL ;
    PORT
      LAYER M5 ;
        RECT  21.216 0 21.24 0.192 ;
    END
  END i_w[79]
  PIN i_w[7]
    DIRECTION INPUT ;
    USE SIGNAL ;
    PORT
      LAYER M5 ;
        RECT  7.392 0 7.416 0.192 ;
    END
  END i_w[7]
  PIN i_w[80]
    DIRECTION INPUT ;
    USE SIGNAL ;
    PORT
      LAYER M5 ;
        RECT  21.408 0 21.432 0.192 ;
    END
  END i_w[80]
  PIN i_w[81]
    DIRECTION INPUT ;
    USE SIGNAL ;
    PORT
      LAYER M5 ;
        RECT  21.6 0 21.624 0.192 ;
    END
  END i_w[81]
  PIN i_w[82]
    DIRECTION INPUT ;
    USE SIGNAL ;
    PORT
      LAYER M5 ;
        RECT  21.792 0 21.816 0.192 ;
    END
  END i_w[82]
  PIN i_w[83]
    DIRECTION INPUT ;
    USE SIGNAL ;
    PORT
      LAYER M5 ;
        RECT  21.984 0 22.008 0.192 ;
    END
  END i_w[83]
  PIN i_w[84]
    DIRECTION INPUT ;
    USE SIGNAL ;
    PORT
      LAYER M5 ;
        RECT  22.176 0 22.2 0.192 ;
    END
  END i_w[84]
  PIN i_w[85]
    DIRECTION INPUT ;
    USE SIGNAL ;
    PORT
      LAYER M5 ;
        RECT  22.368 0 22.392 0.192 ;
    END
  END i_w[85]
  PIN i_w[86]
    DIRECTION INPUT ;
    USE SIGNAL ;
    PORT
      LAYER M5 ;
        RECT  22.56 0 22.584 0.192 ;
    END
  END i_w[86]
  PIN i_w[87]
    DIRECTION INPUT ;
    USE SIGNAL ;
    PORT
      LAYER M5 ;
        RECT  22.752 0 22.776 0.192 ;
    END
  END i_w[87]
  PIN i_w[88]
    DIRECTION INPUT ;
    USE SIGNAL ;
    PORT
      LAYER M5 ;
        RECT  22.944 0 22.968 0.192 ;
    END
  END i_w[88]
  PIN i_w[89]
    DIRECTION INPUT ;
    USE SIGNAL ;
    PORT
      LAYER M5 ;
        RECT  23.136 0 23.16 0.192 ;
    END
  END i_w[89]
  PIN i_w[8]
    DIRECTION INPUT ;
    USE SIGNAL ;
    PORT
      LAYER M5 ;
        RECT  7.584 0 7.608 0.192 ;
    END
  END i_w[8]
  PIN i_w[90]
    DIRECTION INPUT ;
    USE SIGNAL ;
    PORT
      LAYER M5 ;
        RECT  23.328 0 23.352 0.192 ;
    END
  END i_w[90]
  PIN i_w[91]
    DIRECTION INPUT ;
    USE SIGNAL ;
    PORT
      LAYER M5 ;
        RECT  23.52 0 23.544 0.192 ;
    END
  END i_w[91]
  PIN i_w[92]
    DIRECTION INPUT ;
    USE SIGNAL ;
    PORT
      LAYER M5 ;
        RECT  23.712 0 23.736 0.192 ;
    END
  END i_w[92]
  PIN i_w[93]
    DIRECTION INPUT ;
    USE SIGNAL ;
    PORT
      LAYER M5 ;
        RECT  23.904 0 23.928 0.192 ;
    END
  END i_w[93]
  PIN i_w[94]
    DIRECTION INPUT ;
    USE SIGNAL ;
    PORT
      LAYER M5 ;
        RECT  24.096 0 24.12 0.192 ;
    END
  END i_w[94]
  PIN i_w[95]
    DIRECTION INPUT ;
    USE SIGNAL ;
    PORT
      LAYER M5 ;
        RECT  24.288 0 24.312 0.192 ;
    END
  END i_w[95]
  PIN i_w[96]
    DIRECTION INPUT ;
    USE SIGNAL ;
    PORT
      LAYER M5 ;
        RECT  24.48 0 24.504 0.192 ;
    END
  END i_w[96]
  PIN i_w[97]
    DIRECTION INPUT ;
    USE SIGNAL ;
    PORT
      LAYER M5 ;
        RECT  24.672 0 24.696 0.192 ;
    END
  END i_w[97]
  PIN i_w[98]
    DIRECTION INPUT ;
    USE SIGNAL ;
    PORT
      LAYER M5 ;
        RECT  24.864 0 24.888 0.192 ;
    END
  END i_w[98]
  PIN i_w[99]
    DIRECTION INPUT ;
    USE SIGNAL ;
    PORT
      LAYER M5 ;
        RECT  25.056 0 25.08 0.192 ;
    END
  END i_w[99]
  PIN i_w[9]
    DIRECTION INPUT ;
    USE SIGNAL ;
    PORT
      LAYER M5 ;
        RECT  7.776 0 7.8 0.192 ;
    END
  END i_w[9]
  PIN i_x[0]
    DIRECTION INPUT ;
    USE SIGNAL ;
    PORT
      LAYER M5 ;
        RECT  6.144 0 6.168 0.192 ;
    END
  END i_x[0]
  PIN i_x[100]
    DIRECTION INPUT ;
    USE SIGNAL ;
    PORT
      LAYER M5 ;
        RECT  25.344 0 25.368 0.192 ;
    END
  END i_x[100]
  PIN i_x[101]
    DIRECTION INPUT ;
    USE SIGNAL ;
    PORT
      LAYER M5 ;
        RECT  25.536 0 25.56 0.192 ;
    END
  END i_x[101]
  PIN i_x[102]
    DIRECTION INPUT ;
    USE SIGNAL ;
    PORT
      LAYER M5 ;
        RECT  25.728 0 25.752 0.192 ;
    END
  END i_x[102]
  PIN i_x[103]
    DIRECTION INPUT ;
    USE SIGNAL ;
    PORT
      LAYER M5 ;
        RECT  25.92 0 25.944 0.192 ;
    END
  END i_x[103]
  PIN i_x[104]
    DIRECTION INPUT ;
    USE SIGNAL ;
    PORT
      LAYER M5 ;
        RECT  26.112 0 26.136 0.192 ;
    END
  END i_x[104]
  PIN i_x[105]
    DIRECTION INPUT ;
    USE SIGNAL ;
    PORT
      LAYER M5 ;
        RECT  26.304 0 26.328 0.192 ;
    END
  END i_x[105]
  PIN i_x[106]
    DIRECTION INPUT ;
    USE SIGNAL ;
    PORT
      LAYER M5 ;
        RECT  26.496 0 26.52 0.192 ;
    END
  END i_x[106]
  PIN i_x[107]
    DIRECTION INPUT ;
    USE SIGNAL ;
    PORT
      LAYER M5 ;
        RECT  26.688 0 26.712 0.192 ;
    END
  END i_x[107]
  PIN i_x[108]
    DIRECTION INPUT ;
    USE SIGNAL ;
    PORT
      LAYER M5 ;
        RECT  26.88 0 26.904 0.192 ;
    END
  END i_x[108]
  PIN i_x[109]
    DIRECTION INPUT ;
    USE SIGNAL ;
    PORT
      LAYER M5 ;
        RECT  27.072 0 27.096 0.192 ;
    END
  END i_x[109]
  PIN i_x[10]
    DIRECTION INPUT ;
    USE SIGNAL ;
    PORT
      LAYER M5 ;
        RECT  8.064 0 8.088 0.192 ;
    END
  END i_x[10]
  PIN i_x[110]
    DIRECTION INPUT ;
    USE SIGNAL ;
    PORT
      LAYER M5 ;
        RECT  27.264 0 27.288 0.192 ;
    END
  END i_x[110]
  PIN i_x[111]
    DIRECTION INPUT ;
    USE SIGNAL ;
    PORT
      LAYER M5 ;
        RECT  27.456 0 27.48 0.192 ;
    END
  END i_x[111]
  PIN i_x[112]
    DIRECTION INPUT ;
    USE SIGNAL ;
    PORT
      LAYER M5 ;
        RECT  27.648 0 27.672 0.192 ;
    END
  END i_x[112]
  PIN i_x[113]
    DIRECTION INPUT ;
    USE SIGNAL ;
    PORT
      LAYER M5 ;
        RECT  27.84 0 27.864 0.192 ;
    END
  END i_x[113]
  PIN i_x[114]
    DIRECTION INPUT ;
    USE SIGNAL ;
    PORT
      LAYER M5 ;
        RECT  28.032 0 28.056 0.192 ;
    END
  END i_x[114]
  PIN i_x[115]
    DIRECTION INPUT ;
    USE SIGNAL ;
    PORT
      LAYER M5 ;
        RECT  28.224 0 28.248 0.192 ;
    END
  END i_x[115]
  PIN i_x[116]
    DIRECTION INPUT ;
    USE SIGNAL ;
    PORT
      LAYER M5 ;
        RECT  28.416 0 28.44 0.192 ;
    END
  END i_x[116]
  PIN i_x[117]
    DIRECTION INPUT ;
    USE SIGNAL ;
    PORT
      LAYER M5 ;
        RECT  28.608 0 28.632 0.192 ;
    END
  END i_x[117]
  PIN i_x[118]
    DIRECTION INPUT ;
    USE SIGNAL ;
    PORT
      LAYER M5 ;
        RECT  28.8 0 28.824 0.192 ;
    END
  END i_x[118]
  PIN i_x[119]
    DIRECTION INPUT ;
    USE SIGNAL ;
    PORT
      LAYER M5 ;
        RECT  28.992 0 29.016 0.192 ;
    END
  END i_x[119]
  PIN i_x[11]
    DIRECTION INPUT ;
    USE SIGNAL ;
    PORT
      LAYER M5 ;
        RECT  8.256 0 8.28 0.192 ;
    END
  END i_x[11]
  PIN i_x[120]
    DIRECTION INPUT ;
    USE SIGNAL ;
    PORT
      LAYER M5 ;
        RECT  29.184 0 29.208 0.192 ;
    END
  END i_x[120]
  PIN i_x[121]
    DIRECTION INPUT ;
    USE SIGNAL ;
    PORT
      LAYER M5 ;
        RECT  29.376 0 29.4 0.192 ;
    END
  END i_x[121]
  PIN i_x[122]
    DIRECTION INPUT ;
    USE SIGNAL ;
    PORT
      LAYER M5 ;
        RECT  29.568 0 29.592 0.192 ;
    END
  END i_x[122]
  PIN i_x[123]
    DIRECTION INPUT ;
    USE SIGNAL ;
    PORT
      LAYER M5 ;
        RECT  29.76 0 29.784 0.192 ;
    END
  END i_x[123]
  PIN i_x[124]
    DIRECTION INPUT ;
    USE SIGNAL ;
    PORT
      LAYER M5 ;
        RECT  29.952 0 29.976 0.192 ;
    END
  END i_x[124]
  PIN i_x[125]
    DIRECTION INPUT ;
    USE SIGNAL ;
    PORT
      LAYER M5 ;
        RECT  30.144 0 30.168 0.192 ;
    END
  END i_x[125]
  PIN i_x[126]
    DIRECTION INPUT ;
    USE SIGNAL ;
    PORT
      LAYER M5 ;
        RECT  30.336 0 30.36 0.192 ;
    END
  END i_x[126]
  PIN i_x[127]
    DIRECTION INPUT ;
    USE SIGNAL ;
    PORT
      LAYER M5 ;
        RECT  30.528 0 30.552 0.192 ;
    END
  END i_x[127]
  PIN i_x[128]
    DIRECTION INPUT ;
    USE SIGNAL ;
    PORT
      LAYER M5 ;
        RECT  30.72 0 30.744 0.192 ;
    END
  END i_x[128]
  PIN i_x[129]
    DIRECTION INPUT ;
    USE SIGNAL ;
    PORT
      LAYER M5 ;
        RECT  30.912 0 30.936 0.192 ;
    END
  END i_x[129]
  PIN i_x[12]
    DIRECTION INPUT ;
    USE SIGNAL ;
    PORT
      LAYER M5 ;
        RECT  8.448 0 8.472 0.192 ;
    END
  END i_x[12]
  PIN i_x[130]
    DIRECTION INPUT ;
    USE SIGNAL ;
    PORT
      LAYER M5 ;
        RECT  31.104 0 31.128 0.192 ;
    END
  END i_x[130]
  PIN i_x[131]
    DIRECTION INPUT ;
    USE SIGNAL ;
    PORT
      LAYER M5 ;
        RECT  31.296 0 31.32 0.192 ;
    END
  END i_x[131]
  PIN i_x[132]
    DIRECTION INPUT ;
    USE SIGNAL ;
    PORT
      LAYER M5 ;
        RECT  31.488 0 31.512 0.192 ;
    END
  END i_x[132]
  PIN i_x[133]
    DIRECTION INPUT ;
    USE SIGNAL ;
    PORT
      LAYER M5 ;
        RECT  31.68 0 31.704 0.192 ;
    END
  END i_x[133]
  PIN i_x[134]
    DIRECTION INPUT ;
    USE SIGNAL ;
    PORT
      LAYER M5 ;
        RECT  31.872 0 31.896 0.192 ;
    END
  END i_x[134]
  PIN i_x[135]
    DIRECTION INPUT ;
    USE SIGNAL ;
    PORT
      LAYER M5 ;
        RECT  32.064 0 32.088 0.192 ;
    END
  END i_x[135]
  PIN i_x[136]
    DIRECTION INPUT ;
    USE SIGNAL ;
    PORT
      LAYER M5 ;
        RECT  32.256 0 32.28 0.192 ;
    END
  END i_x[136]
  PIN i_x[137]
    DIRECTION INPUT ;
    USE SIGNAL ;
    PORT
      LAYER M5 ;
        RECT  32.448 0 32.472 0.192 ;
    END
  END i_x[137]
  PIN i_x[138]
    DIRECTION INPUT ;
    USE SIGNAL ;
    PORT
      LAYER M5 ;
        RECT  32.64 0 32.664 0.192 ;
    END
  END i_x[138]
  PIN i_x[139]
    DIRECTION INPUT ;
    USE SIGNAL ;
    PORT
      LAYER M5 ;
        RECT  32.832 0 32.856 0.192 ;
    END
  END i_x[139]
  PIN i_x[13]
    DIRECTION INPUT ;
    USE SIGNAL ;
    PORT
      LAYER M5 ;
        RECT  8.64 0 8.664 0.192 ;
    END
  END i_x[13]
  PIN i_x[140]
    DIRECTION INPUT ;
    USE SIGNAL ;
    PORT
      LAYER M5 ;
        RECT  33.024 0 33.048 0.192 ;
    END
  END i_x[140]
  PIN i_x[141]
    DIRECTION INPUT ;
    USE SIGNAL ;
    PORT
      LAYER M5 ;
        RECT  33.216 0 33.24 0.192 ;
    END
  END i_x[141]
  PIN i_x[142]
    DIRECTION INPUT ;
    USE SIGNAL ;
    PORT
      LAYER M5 ;
        RECT  33.408 0 33.432 0.192 ;
    END
  END i_x[142]
  PIN i_x[143]
    DIRECTION INPUT ;
    USE SIGNAL ;
    PORT
      LAYER M5 ;
        RECT  33.6 0 33.624 0.192 ;
    END
  END i_x[143]
  PIN i_x[144]
    DIRECTION INPUT ;
    USE SIGNAL ;
    PORT
      LAYER M5 ;
        RECT  33.792 0 33.816 0.192 ;
    END
  END i_x[144]
  PIN i_x[145]
    DIRECTION INPUT ;
    USE SIGNAL ;
    PORT
      LAYER M5 ;
        RECT  33.984 0 34.008 0.192 ;
    END
  END i_x[145]
  PIN i_x[146]
    DIRECTION INPUT ;
    USE SIGNAL ;
    PORT
      LAYER M5 ;
        RECT  34.176 0 34.2 0.192 ;
    END
  END i_x[146]
  PIN i_x[147]
    DIRECTION INPUT ;
    USE SIGNAL ;
    PORT
      LAYER M5 ;
        RECT  34.368 0 34.392 0.192 ;
    END
  END i_x[147]
  PIN i_x[148]
    DIRECTION INPUT ;
    USE SIGNAL ;
    PORT
      LAYER M5 ;
        RECT  34.56 0 34.584 0.192 ;
    END
  END i_x[148]
  PIN i_x[149]
    DIRECTION INPUT ;
    USE SIGNAL ;
    PORT
      LAYER M5 ;
        RECT  34.752 0 34.776 0.192 ;
    END
  END i_x[149]
  PIN i_x[14]
    DIRECTION INPUT ;
    USE SIGNAL ;
    PORT
      LAYER M5 ;
        RECT  8.832 0 8.856 0.192 ;
    END
  END i_x[14]
  PIN i_x[150]
    DIRECTION INPUT ;
    USE SIGNAL ;
    PORT
      LAYER M5 ;
        RECT  34.944 0 34.968 0.192 ;
    END
  END i_x[150]
  PIN i_x[151]
    DIRECTION INPUT ;
    USE SIGNAL ;
    PORT
      LAYER M5 ;
        RECT  35.136 0 35.16 0.192 ;
    END
  END i_x[151]
  PIN i_x[152]
    DIRECTION INPUT ;
    USE SIGNAL ;
    PORT
      LAYER M5 ;
        RECT  35.328 0 35.352 0.192 ;
    END
  END i_x[152]
  PIN i_x[153]
    DIRECTION INPUT ;
    USE SIGNAL ;
    PORT
      LAYER M5 ;
        RECT  35.52 0 35.544 0.192 ;
    END
  END i_x[153]
  PIN i_x[154]
    DIRECTION INPUT ;
    USE SIGNAL ;
    PORT
      LAYER M5 ;
        RECT  35.712 0 35.736 0.192 ;
    END
  END i_x[154]
  PIN i_x[155]
    DIRECTION INPUT ;
    USE SIGNAL ;
    PORT
      LAYER M5 ;
        RECT  35.904 0 35.928 0.192 ;
    END
  END i_x[155]
  PIN i_x[156]
    DIRECTION INPUT ;
    USE SIGNAL ;
    PORT
      LAYER M5 ;
        RECT  36.096 0 36.12 0.192 ;
    END
  END i_x[156]
  PIN i_x[157]
    DIRECTION INPUT ;
    USE SIGNAL ;
    PORT
      LAYER M5 ;
        RECT  36.288 0 36.312 0.192 ;
    END
  END i_x[157]
  PIN i_x[158]
    DIRECTION INPUT ;
    USE SIGNAL ;
    PORT
      LAYER M5 ;
        RECT  36.48 0 36.504 0.192 ;
    END
  END i_x[158]
  PIN i_x[159]
    DIRECTION INPUT ;
    USE SIGNAL ;
    PORT
      LAYER M5 ;
        RECT  36.672 0 36.696 0.192 ;
    END
  END i_x[159]
  PIN i_x[15]
    DIRECTION INPUT ;
    USE SIGNAL ;
    PORT
      LAYER M5 ;
        RECT  9.024 0 9.048 0.192 ;
    END
  END i_x[15]
  PIN i_x[160]
    DIRECTION INPUT ;
    USE SIGNAL ;
    PORT
      LAYER M5 ;
        RECT  36.864 0 36.888 0.192 ;
    END
  END i_x[160]
  PIN i_x[161]
    DIRECTION INPUT ;
    USE SIGNAL ;
    PORT
      LAYER M5 ;
        RECT  37.056 0 37.08 0.192 ;
    END
  END i_x[161]
  PIN i_x[162]
    DIRECTION INPUT ;
    USE SIGNAL ;
    PORT
      LAYER M5 ;
        RECT  37.248 0 37.272 0.192 ;
    END
  END i_x[162]
  PIN i_x[163]
    DIRECTION INPUT ;
    USE SIGNAL ;
    PORT
      LAYER M5 ;
        RECT  37.44 0 37.464 0.192 ;
    END
  END i_x[163]
  PIN i_x[164]
    DIRECTION INPUT ;
    USE SIGNAL ;
    PORT
      LAYER M5 ;
        RECT  37.632 0 37.656 0.192 ;
    END
  END i_x[164]
  PIN i_x[165]
    DIRECTION INPUT ;
    USE SIGNAL ;
    PORT
      LAYER M5 ;
        RECT  37.824 0 37.848 0.192 ;
    END
  END i_x[165]
  PIN i_x[166]
    DIRECTION INPUT ;
    USE SIGNAL ;
    PORT
      LAYER M5 ;
        RECT  38.016 0 38.04 0.192 ;
    END
  END i_x[166]
  PIN i_x[167]
    DIRECTION INPUT ;
    USE SIGNAL ;
    PORT
      LAYER M5 ;
        RECT  38.208 0 38.232 0.192 ;
    END
  END i_x[167]
  PIN i_x[168]
    DIRECTION INPUT ;
    USE SIGNAL ;
    PORT
      LAYER M5 ;
        RECT  38.4 0 38.424 0.192 ;
    END
  END i_x[168]
  PIN i_x[169]
    DIRECTION INPUT ;
    USE SIGNAL ;
    PORT
      LAYER M5 ;
        RECT  38.592 0 38.616 0.192 ;
    END
  END i_x[169]
  PIN i_x[16]
    DIRECTION INPUT ;
    USE SIGNAL ;
    PORT
      LAYER M5 ;
        RECT  9.216 0 9.24 0.192 ;
    END
  END i_x[16]
  PIN i_x[170]
    DIRECTION INPUT ;
    USE SIGNAL ;
    PORT
      LAYER M5 ;
        RECT  38.784 0 38.808 0.192 ;
    END
  END i_x[170]
  PIN i_x[171]
    DIRECTION INPUT ;
    USE SIGNAL ;
    PORT
      LAYER M5 ;
        RECT  38.976 0 39 0.192 ;
    END
  END i_x[171]
  PIN i_x[172]
    DIRECTION INPUT ;
    USE SIGNAL ;
    PORT
      LAYER M5 ;
        RECT  39.168 0 39.192 0.192 ;
    END
  END i_x[172]
  PIN i_x[173]
    DIRECTION INPUT ;
    USE SIGNAL ;
    PORT
      LAYER M5 ;
        RECT  39.36 0 39.384 0.192 ;
    END
  END i_x[173]
  PIN i_x[174]
    DIRECTION INPUT ;
    USE SIGNAL ;
    PORT
      LAYER M5 ;
        RECT  39.552 0 39.576 0.192 ;
    END
  END i_x[174]
  PIN i_x[175]
    DIRECTION INPUT ;
    USE SIGNAL ;
    PORT
      LAYER M5 ;
        RECT  39.744 0 39.768 0.192 ;
    END
  END i_x[175]
  PIN i_x[176]
    DIRECTION INPUT ;
    USE SIGNAL ;
    PORT
      LAYER M5 ;
        RECT  39.936 0 39.96 0.192 ;
    END
  END i_x[176]
  PIN i_x[177]
    DIRECTION INPUT ;
    USE SIGNAL ;
    PORT
      LAYER M5 ;
        RECT  40.128 0 40.152 0.192 ;
    END
  END i_x[177]
  PIN i_x[178]
    DIRECTION INPUT ;
    USE SIGNAL ;
    PORT
      LAYER M5 ;
        RECT  40.32 0 40.344 0.192 ;
    END
  END i_x[178]
  PIN i_x[179]
    DIRECTION INPUT ;
    USE SIGNAL ;
    PORT
      LAYER M5 ;
        RECT  40.512 0 40.536 0.192 ;
    END
  END i_x[179]
  PIN i_x[17]
    DIRECTION INPUT ;
    USE SIGNAL ;
    PORT
      LAYER M5 ;
        RECT  9.408 0 9.432 0.192 ;
    END
  END i_x[17]
  PIN i_x[180]
    DIRECTION INPUT ;
    USE SIGNAL ;
    PORT
      LAYER M5 ;
        RECT  40.704 0 40.728 0.192 ;
    END
  END i_x[180]
  PIN i_x[181]
    DIRECTION INPUT ;
    USE SIGNAL ;
    PORT
      LAYER M5 ;
        RECT  40.896 0 40.92 0.192 ;
    END
  END i_x[181]
  PIN i_x[182]
    DIRECTION INPUT ;
    USE SIGNAL ;
    PORT
      LAYER M5 ;
        RECT  41.088 0 41.112 0.192 ;
    END
  END i_x[182]
  PIN i_x[183]
    DIRECTION INPUT ;
    USE SIGNAL ;
    PORT
      LAYER M5 ;
        RECT  41.28 0 41.304 0.192 ;
    END
  END i_x[183]
  PIN i_x[184]
    DIRECTION INPUT ;
    USE SIGNAL ;
    PORT
      LAYER M5 ;
        RECT  41.472 0 41.496 0.192 ;
    END
  END i_x[184]
  PIN i_x[185]
    DIRECTION INPUT ;
    USE SIGNAL ;
    PORT
      LAYER M5 ;
        RECT  41.664 0 41.688 0.192 ;
    END
  END i_x[185]
  PIN i_x[186]
    DIRECTION INPUT ;
    USE SIGNAL ;
    PORT
      LAYER M5 ;
        RECT  41.856 0 41.88 0.192 ;
    END
  END i_x[186]
  PIN i_x[187]
    DIRECTION INPUT ;
    USE SIGNAL ;
    PORT
      LAYER M5 ;
        RECT  42.048 0 42.072 0.192 ;
    END
  END i_x[187]
  PIN i_x[188]
    DIRECTION INPUT ;
    USE SIGNAL ;
    PORT
      LAYER M5 ;
        RECT  42.24 0 42.264 0.192 ;
    END
  END i_x[188]
  PIN i_x[189]
    DIRECTION INPUT ;
    USE SIGNAL ;
    PORT
      LAYER M5 ;
        RECT  42.432 0 42.456 0.192 ;
    END
  END i_x[189]
  PIN i_x[18]
    DIRECTION INPUT ;
    USE SIGNAL ;
    PORT
      LAYER M5 ;
        RECT  9.6 0 9.624 0.192 ;
    END
  END i_x[18]
  PIN i_x[190]
    DIRECTION INPUT ;
    USE SIGNAL ;
    PORT
      LAYER M5 ;
        RECT  42.624 0 42.648 0.192 ;
    END
  END i_x[190]
  PIN i_x[191]
    DIRECTION INPUT ;
    USE SIGNAL ;
    PORT
      LAYER M5 ;
        RECT  42.816 0 42.84 0.192 ;
    END
  END i_x[191]
  PIN i_x[192]
    DIRECTION INPUT ;
    USE SIGNAL ;
    PORT
      LAYER M5 ;
        RECT  43.008 0 43.032 0.192 ;
    END
  END i_x[192]
  PIN i_x[193]
    DIRECTION INPUT ;
    USE SIGNAL ;
    PORT
      LAYER M5 ;
        RECT  43.2 0 43.224 0.192 ;
    END
  END i_x[193]
  PIN i_x[194]
    DIRECTION INPUT ;
    USE SIGNAL ;
    PORT
      LAYER M5 ;
        RECT  43.392 0 43.416 0.192 ;
    END
  END i_x[194]
  PIN i_x[195]
    DIRECTION INPUT ;
    USE SIGNAL ;
    PORT
      LAYER M5 ;
        RECT  43.584 0 43.608 0.192 ;
    END
  END i_x[195]
  PIN i_x[196]
    DIRECTION INPUT ;
    USE SIGNAL ;
    PORT
      LAYER M5 ;
        RECT  43.776 0 43.8 0.192 ;
    END
  END i_x[196]
  PIN i_x[197]
    DIRECTION INPUT ;
    USE SIGNAL ;
    PORT
      LAYER M5 ;
        RECT  43.968 0 43.992 0.192 ;
    END
  END i_x[197]
  PIN i_x[198]
    DIRECTION INPUT ;
    USE SIGNAL ;
    PORT
      LAYER M5 ;
        RECT  44.16 0 44.184 0.192 ;
    END
  END i_x[198]
  PIN i_x[199]
    DIRECTION INPUT ;
    USE SIGNAL ;
    PORT
      LAYER M5 ;
        RECT  44.352 0 44.376 0.192 ;
    END
  END i_x[199]
  PIN i_x[19]
    DIRECTION INPUT ;
    USE SIGNAL ;
    PORT
      LAYER M5 ;
        RECT  9.792 0 9.816 0.192 ;
    END
  END i_x[19]
  PIN i_x[1]
    DIRECTION INPUT ;
    USE SIGNAL ;
    PORT
      LAYER M5 ;
        RECT  6.336 0 6.36 0.192 ;
    END
  END i_x[1]
  PIN i_x[200]
    DIRECTION INPUT ;
    USE SIGNAL ;
    PORT
      LAYER M5 ;
        RECT  44.544 0 44.568 0.192 ;
    END
  END i_x[200]
  PIN i_x[201]
    DIRECTION INPUT ;
    USE SIGNAL ;
    PORT
      LAYER M5 ;
        RECT  44.736 0 44.76 0.192 ;
    END
  END i_x[201]
  PIN i_x[202]
    DIRECTION INPUT ;
    USE SIGNAL ;
    PORT
      LAYER M5 ;
        RECT  44.928 0 44.952 0.192 ;
    END
  END i_x[202]
  PIN i_x[203]
    DIRECTION INPUT ;
    USE SIGNAL ;
    PORT
      LAYER M5 ;
        RECT  45.12 0 45.144 0.192 ;
    END
  END i_x[203]
  PIN i_x[204]
    DIRECTION INPUT ;
    USE SIGNAL ;
    PORT
      LAYER M5 ;
        RECT  45.312 0 45.336 0.192 ;
    END
  END i_x[204]
  PIN i_x[205]
    DIRECTION INPUT ;
    USE SIGNAL ;
    PORT
      LAYER M5 ;
        RECT  45.504 0 45.528 0.192 ;
    END
  END i_x[205]
  PIN i_x[206]
    DIRECTION INPUT ;
    USE SIGNAL ;
    PORT
      LAYER M5 ;
        RECT  45.696 0 45.72 0.192 ;
    END
  END i_x[206]
  PIN i_x[207]
    DIRECTION INPUT ;
    USE SIGNAL ;
    PORT
      LAYER M5 ;
        RECT  45.888 0 45.912 0.192 ;
    END
  END i_x[207]
  PIN i_x[208]
    DIRECTION INPUT ;
    USE SIGNAL ;
    PORT
      LAYER M5 ;
        RECT  46.08 0 46.104 0.192 ;
    END
  END i_x[208]
  PIN i_x[209]
    DIRECTION INPUT ;
    USE SIGNAL ;
    PORT
      LAYER M5 ;
        RECT  46.272 0 46.296 0.192 ;
    END
  END i_x[209]
  PIN i_x[20]
    DIRECTION INPUT ;
    USE SIGNAL ;
    PORT
      LAYER M5 ;
        RECT  9.984 0 10.008 0.192 ;
    END
  END i_x[20]
  PIN i_x[210]
    DIRECTION INPUT ;
    USE SIGNAL ;
    PORT
      LAYER M5 ;
        RECT  46.464 0 46.488 0.192 ;
    END
  END i_x[210]
  PIN i_x[211]
    DIRECTION INPUT ;
    USE SIGNAL ;
    PORT
      LAYER M5 ;
        RECT  46.656 0 46.68 0.192 ;
    END
  END i_x[211]
  PIN i_x[212]
    DIRECTION INPUT ;
    USE SIGNAL ;
    PORT
      LAYER M5 ;
        RECT  46.848 0 46.872 0.192 ;
    END
  END i_x[212]
  PIN i_x[213]
    DIRECTION INPUT ;
    USE SIGNAL ;
    PORT
      LAYER M5 ;
        RECT  47.04 0 47.064 0.192 ;
    END
  END i_x[213]
  PIN i_x[214]
    DIRECTION INPUT ;
    USE SIGNAL ;
    PORT
      LAYER M5 ;
        RECT  47.232 0 47.256 0.192 ;
    END
  END i_x[214]
  PIN i_x[215]
    DIRECTION INPUT ;
    USE SIGNAL ;
    PORT
      LAYER M5 ;
        RECT  47.424 0 47.448 0.192 ;
    END
  END i_x[215]
  PIN i_x[216]
    DIRECTION INPUT ;
    USE SIGNAL ;
    PORT
      LAYER M5 ;
        RECT  47.616 0 47.64 0.192 ;
    END
  END i_x[216]
  PIN i_x[217]
    DIRECTION INPUT ;
    USE SIGNAL ;
    PORT
      LAYER M5 ;
        RECT  47.808 0 47.832 0.192 ;
    END
  END i_x[217]
  PIN i_x[218]
    DIRECTION INPUT ;
    USE SIGNAL ;
    PORT
      LAYER M5 ;
        RECT  48 0 48.024 0.192 ;
    END
  END i_x[218]
  PIN i_x[219]
    DIRECTION INPUT ;
    USE SIGNAL ;
    PORT
      LAYER M5 ;
        RECT  48.192 0 48.216 0.192 ;
    END
  END i_x[219]
  PIN i_x[21]
    DIRECTION INPUT ;
    USE SIGNAL ;
    PORT
      LAYER M5 ;
        RECT  10.176 0 10.2 0.192 ;
    END
  END i_x[21]
  PIN i_x[220]
    DIRECTION INPUT ;
    USE SIGNAL ;
    PORT
      LAYER M5 ;
        RECT  48.384 0 48.408 0.192 ;
    END
  END i_x[220]
  PIN i_x[221]
    DIRECTION INPUT ;
    USE SIGNAL ;
    PORT
      LAYER M5 ;
        RECT  48.576 0 48.6 0.192 ;
    END
  END i_x[221]
  PIN i_x[222]
    DIRECTION INPUT ;
    USE SIGNAL ;
    PORT
      LAYER M5 ;
        RECT  48.768 0 48.792 0.192 ;
    END
  END i_x[222]
  PIN i_x[223]
    DIRECTION INPUT ;
    USE SIGNAL ;
    PORT
      LAYER M5 ;
        RECT  48.96 0 48.984 0.192 ;
    END
  END i_x[223]
  PIN i_x[224]
    DIRECTION INPUT ;
    USE SIGNAL ;
    PORT
      LAYER M5 ;
        RECT  49.152 0 49.176 0.192 ;
    END
  END i_x[224]
  PIN i_x[225]
    DIRECTION INPUT ;
    USE SIGNAL ;
    PORT
      LAYER M5 ;
        RECT  49.344 0 49.368 0.192 ;
    END
  END i_x[225]
  PIN i_x[226]
    DIRECTION INPUT ;
    USE SIGNAL ;
    PORT
      LAYER M5 ;
        RECT  49.536 0 49.56 0.192 ;
    END
  END i_x[226]
  PIN i_x[227]
    DIRECTION INPUT ;
    USE SIGNAL ;
    PORT
      LAYER M5 ;
        RECT  49.728 0 49.752 0.192 ;
    END
  END i_x[227]
  PIN i_x[228]
    DIRECTION INPUT ;
    USE SIGNAL ;
    PORT
      LAYER M5 ;
        RECT  49.92 0 49.944 0.192 ;
    END
  END i_x[228]
  PIN i_x[229]
    DIRECTION INPUT ;
    USE SIGNAL ;
    PORT
      LAYER M5 ;
        RECT  50.112 0 50.136 0.192 ;
    END
  END i_x[229]
  PIN i_x[22]
    DIRECTION INPUT ;
    USE SIGNAL ;
    PORT
      LAYER M5 ;
        RECT  10.368 0 10.392 0.192 ;
    END
  END i_x[22]
  PIN i_x[230]
    DIRECTION INPUT ;
    USE SIGNAL ;
    PORT
      LAYER M5 ;
        RECT  50.304 0 50.328 0.192 ;
    END
  END i_x[230]
  PIN i_x[231]
    DIRECTION INPUT ;
    USE SIGNAL ;
    PORT
      LAYER M5 ;
        RECT  50.496 0 50.52 0.192 ;
    END
  END i_x[231]
  PIN i_x[232]
    DIRECTION INPUT ;
    USE SIGNAL ;
    PORT
      LAYER M5 ;
        RECT  50.688 0 50.712 0.192 ;
    END
  END i_x[232]
  PIN i_x[233]
    DIRECTION INPUT ;
    USE SIGNAL ;
    PORT
      LAYER M5 ;
        RECT  50.88 0 50.904 0.192 ;
    END
  END i_x[233]
  PIN i_x[234]
    DIRECTION INPUT ;
    USE SIGNAL ;
    PORT
      LAYER M5 ;
        RECT  51.072 0 51.096 0.192 ;
    END
  END i_x[234]
  PIN i_x[235]
    DIRECTION INPUT ;
    USE SIGNAL ;
    PORT
      LAYER M5 ;
        RECT  51.264 0 51.288 0.192 ;
    END
  END i_x[235]
  PIN i_x[236]
    DIRECTION INPUT ;
    USE SIGNAL ;
    PORT
      LAYER M5 ;
        RECT  51.456 0 51.48 0.192 ;
    END
  END i_x[236]
  PIN i_x[237]
    DIRECTION INPUT ;
    USE SIGNAL ;
    PORT
      LAYER M5 ;
        RECT  51.648 0 51.672 0.192 ;
    END
  END i_x[237]
  PIN i_x[238]
    DIRECTION INPUT ;
    USE SIGNAL ;
    PORT
      LAYER M5 ;
        RECT  51.84 0 51.864 0.192 ;
    END
  END i_x[238]
  PIN i_x[239]
    DIRECTION INPUT ;
    USE SIGNAL ;
    PORT
      LAYER M5 ;
        RECT  52.032 0 52.056 0.192 ;
    END
  END i_x[239]
  PIN i_x[23]
    DIRECTION INPUT ;
    USE SIGNAL ;
    PORT
      LAYER M5 ;
        RECT  10.56 0 10.584 0.192 ;
    END
  END i_x[23]
  PIN i_x[240]
    DIRECTION INPUT ;
    USE SIGNAL ;
    PORT
      LAYER M5 ;
        RECT  52.224 0 52.248 0.192 ;
    END
  END i_x[240]
  PIN i_x[241]
    DIRECTION INPUT ;
    USE SIGNAL ;
    PORT
      LAYER M5 ;
        RECT  52.416 0 52.44 0.192 ;
    END
  END i_x[241]
  PIN i_x[242]
    DIRECTION INPUT ;
    USE SIGNAL ;
    PORT
      LAYER M5 ;
        RECT  52.608 0 52.632 0.192 ;
    END
  END i_x[242]
  PIN i_x[243]
    DIRECTION INPUT ;
    USE SIGNAL ;
    PORT
      LAYER M5 ;
        RECT  52.8 0 52.824 0.192 ;
    END
  END i_x[243]
  PIN i_x[244]
    DIRECTION INPUT ;
    USE SIGNAL ;
    PORT
      LAYER M5 ;
        RECT  52.992 0 53.016 0.192 ;
    END
  END i_x[244]
  PIN i_x[245]
    DIRECTION INPUT ;
    USE SIGNAL ;
    PORT
      LAYER M5 ;
        RECT  53.184 0 53.208 0.192 ;
    END
  END i_x[245]
  PIN i_x[246]
    DIRECTION INPUT ;
    USE SIGNAL ;
    PORT
      LAYER M5 ;
        RECT  53.376 0 53.4 0.192 ;
    END
  END i_x[246]
  PIN i_x[247]
    DIRECTION INPUT ;
    USE SIGNAL ;
    PORT
      LAYER M5 ;
        RECT  53.568 0 53.592 0.192 ;
    END
  END i_x[247]
  PIN i_x[248]
    DIRECTION INPUT ;
    USE SIGNAL ;
    PORT
      LAYER M5 ;
        RECT  53.76 0 53.784 0.192 ;
    END
  END i_x[248]
  PIN i_x[249]
    DIRECTION INPUT ;
    USE SIGNAL ;
    PORT
      LAYER M5 ;
        RECT  53.952 0 53.976 0.192 ;
    END
  END i_x[249]
  PIN i_x[24]
    DIRECTION INPUT ;
    USE SIGNAL ;
    PORT
      LAYER M5 ;
        RECT  10.752 0 10.776 0.192 ;
    END
  END i_x[24]
  PIN i_x[250]
    DIRECTION INPUT ;
    USE SIGNAL ;
    PORT
      LAYER M5 ;
        RECT  54.144 0 54.168 0.192 ;
    END
  END i_x[250]
  PIN i_x[251]
    DIRECTION INPUT ;
    USE SIGNAL ;
    PORT
      LAYER M5 ;
        RECT  54.336 0 54.36 0.192 ;
    END
  END i_x[251]
  PIN i_x[252]
    DIRECTION INPUT ;
    USE SIGNAL ;
    PORT
      LAYER M5 ;
        RECT  54.528 0 54.552 0.192 ;
    END
  END i_x[252]
  PIN i_x[253]
    DIRECTION INPUT ;
    USE SIGNAL ;
    PORT
      LAYER M5 ;
        RECT  54.72 0 54.744 0.192 ;
    END
  END i_x[253]
  PIN i_x[254]
    DIRECTION INPUT ;
    USE SIGNAL ;
    PORT
      LAYER M5 ;
        RECT  54.912 0 54.936 0.192 ;
    END
  END i_x[254]
  PIN i_x[255]
    DIRECTION INPUT ;
    USE SIGNAL ;
    PORT
      LAYER M5 ;
        RECT  55.104 0 55.128 0.192 ;
    END
  END i_x[255]
  PIN i_x[256]
    DIRECTION INPUT ;
    USE SIGNAL ;
    PORT
      LAYER M5 ;
        RECT  55.296 0 55.32 0.192 ;
    END
  END i_x[256]
  PIN i_x[257]
    DIRECTION INPUT ;
    USE SIGNAL ;
    PORT
      LAYER M5 ;
        RECT  55.488 0 55.512 0.192 ;
    END
  END i_x[257]
  PIN i_x[258]
    DIRECTION INPUT ;
    USE SIGNAL ;
    PORT
      LAYER M5 ;
        RECT  55.68 0 55.704 0.192 ;
    END
  END i_x[258]
  PIN i_x[259]
    DIRECTION INPUT ;
    USE SIGNAL ;
    PORT
      LAYER M5 ;
        RECT  55.872 0 55.896 0.192 ;
    END
  END i_x[259]
  PIN i_x[25]
    DIRECTION INPUT ;
    USE SIGNAL ;
    PORT
      LAYER M5 ;
        RECT  10.944 0 10.968 0.192 ;
    END
  END i_x[25]
  PIN i_x[260]
    DIRECTION INPUT ;
    USE SIGNAL ;
    PORT
      LAYER M5 ;
        RECT  56.064 0 56.088 0.192 ;
    END
  END i_x[260]
  PIN i_x[261]
    DIRECTION INPUT ;
    USE SIGNAL ;
    PORT
      LAYER M5 ;
        RECT  56.256 0 56.28 0.192 ;
    END
  END i_x[261]
  PIN i_x[262]
    DIRECTION INPUT ;
    USE SIGNAL ;
    PORT
      LAYER M5 ;
        RECT  56.448 0 56.472 0.192 ;
    END
  END i_x[262]
  PIN i_x[263]
    DIRECTION INPUT ;
    USE SIGNAL ;
    PORT
      LAYER M5 ;
        RECT  56.64 0 56.664 0.192 ;
    END
  END i_x[263]
  PIN i_x[264]
    DIRECTION INPUT ;
    USE SIGNAL ;
    PORT
      LAYER M5 ;
        RECT  56.832 0 56.856 0.192 ;
    END
  END i_x[264]
  PIN i_x[265]
    DIRECTION INPUT ;
    USE SIGNAL ;
    PORT
      LAYER M5 ;
        RECT  57.024 0 57.048 0.192 ;
    END
  END i_x[265]
  PIN i_x[266]
    DIRECTION INPUT ;
    USE SIGNAL ;
    PORT
      LAYER M5 ;
        RECT  57.216 0 57.24 0.192 ;
    END
  END i_x[266]
  PIN i_x[267]
    DIRECTION INPUT ;
    USE SIGNAL ;
    PORT
      LAYER M5 ;
        RECT  57.408 0 57.432 0.192 ;
    END
  END i_x[267]
  PIN i_x[268]
    DIRECTION INPUT ;
    USE SIGNAL ;
    PORT
      LAYER M5 ;
        RECT  57.6 0 57.624 0.192 ;
    END
  END i_x[268]
  PIN i_x[269]
    DIRECTION INPUT ;
    USE SIGNAL ;
    PORT
      LAYER M5 ;
        RECT  57.792 0 57.816 0.192 ;
    END
  END i_x[269]
  PIN i_x[26]
    DIRECTION INPUT ;
    USE SIGNAL ;
    PORT
      LAYER M5 ;
        RECT  11.136 0 11.16 0.192 ;
    END
  END i_x[26]
  PIN i_x[270]
    DIRECTION INPUT ;
    USE SIGNAL ;
    PORT
      LAYER M5 ;
        RECT  57.984 0 58.008 0.192 ;
    END
  END i_x[270]
  PIN i_x[271]
    DIRECTION INPUT ;
    USE SIGNAL ;
    PORT
      LAYER M5 ;
        RECT  58.176 0 58.2 0.192 ;
    END
  END i_x[271]
  PIN i_x[272]
    DIRECTION INPUT ;
    USE SIGNAL ;
    PORT
      LAYER M5 ;
        RECT  58.368 0 58.392 0.192 ;
    END
  END i_x[272]
  PIN i_x[273]
    DIRECTION INPUT ;
    USE SIGNAL ;
    PORT
      LAYER M5 ;
        RECT  58.56 0 58.584 0.192 ;
    END
  END i_x[273]
  PIN i_x[274]
    DIRECTION INPUT ;
    USE SIGNAL ;
    PORT
      LAYER M5 ;
        RECT  58.752 0 58.776 0.192 ;
    END
  END i_x[274]
  PIN i_x[275]
    DIRECTION INPUT ;
    USE SIGNAL ;
    PORT
      LAYER M5 ;
        RECT  58.944 0 58.968 0.192 ;
    END
  END i_x[275]
  PIN i_x[276]
    DIRECTION INPUT ;
    USE SIGNAL ;
    PORT
      LAYER M5 ;
        RECT  59.136 0 59.16 0.192 ;
    END
  END i_x[276]
  PIN i_x[277]
    DIRECTION INPUT ;
    USE SIGNAL ;
    PORT
      LAYER M5 ;
        RECT  59.328 0 59.352 0.192 ;
    END
  END i_x[277]
  PIN i_x[278]
    DIRECTION INPUT ;
    USE SIGNAL ;
    PORT
      LAYER M5 ;
        RECT  59.52 0 59.544 0.192 ;
    END
  END i_x[278]
  PIN i_x[279]
    DIRECTION INPUT ;
    USE SIGNAL ;
    PORT
      LAYER M5 ;
        RECT  59.712 0 59.736 0.192 ;
    END
  END i_x[279]
  PIN i_x[27]
    DIRECTION INPUT ;
    USE SIGNAL ;
    PORT
      LAYER M5 ;
        RECT  11.328 0 11.352 0.192 ;
    END
  END i_x[27]
  PIN i_x[280]
    DIRECTION INPUT ;
    USE SIGNAL ;
    PORT
      LAYER M5 ;
        RECT  59.904 0 59.928 0.192 ;
    END
  END i_x[280]
  PIN i_x[281]
    DIRECTION INPUT ;
    USE SIGNAL ;
    PORT
      LAYER M5 ;
        RECT  60.096 0 60.12 0.192 ;
    END
  END i_x[281]
  PIN i_x[282]
    DIRECTION INPUT ;
    USE SIGNAL ;
    PORT
      LAYER M5 ;
        RECT  60.288 0 60.312 0.192 ;
    END
  END i_x[282]
  PIN i_x[283]
    DIRECTION INPUT ;
    USE SIGNAL ;
    PORT
      LAYER M5 ;
        RECT  60.48 0 60.504 0.192 ;
    END
  END i_x[283]
  PIN i_x[284]
    DIRECTION INPUT ;
    USE SIGNAL ;
    PORT
      LAYER M5 ;
        RECT  60.672 0 60.696 0.192 ;
    END
  END i_x[284]
  PIN i_x[285]
    DIRECTION INPUT ;
    USE SIGNAL ;
    PORT
      LAYER M5 ;
        RECT  60.864 0 60.888 0.192 ;
    END
  END i_x[285]
  PIN i_x[286]
    DIRECTION INPUT ;
    USE SIGNAL ;
    PORT
      LAYER M5 ;
        RECT  61.056 0 61.08 0.192 ;
    END
  END i_x[286]
  PIN i_x[287]
    DIRECTION INPUT ;
    USE SIGNAL ;
    PORT
      LAYER M5 ;
        RECT  61.248 0 61.272 0.192 ;
    END
  END i_x[287]
  PIN i_x[288]
    DIRECTION INPUT ;
    USE SIGNAL ;
    PORT
      LAYER M5 ;
        RECT  61.44 0 61.464 0.192 ;
    END
  END i_x[288]
  PIN i_x[289]
    DIRECTION INPUT ;
    USE SIGNAL ;
    PORT
      LAYER M5 ;
        RECT  61.632 0 61.656 0.192 ;
    END
  END i_x[289]
  PIN i_x[28]
    DIRECTION INPUT ;
    USE SIGNAL ;
    PORT
      LAYER M5 ;
        RECT  11.52 0 11.544 0.192 ;
    END
  END i_x[28]
  PIN i_x[290]
    DIRECTION INPUT ;
    USE SIGNAL ;
    PORT
      LAYER M5 ;
        RECT  61.824 0 61.848 0.192 ;
    END
  END i_x[290]
  PIN i_x[291]
    DIRECTION INPUT ;
    USE SIGNAL ;
    PORT
      LAYER M5 ;
        RECT  62.016 0 62.04 0.192 ;
    END
  END i_x[291]
  PIN i_x[292]
    DIRECTION INPUT ;
    USE SIGNAL ;
    PORT
      LAYER M5 ;
        RECT  62.208 0 62.232 0.192 ;
    END
  END i_x[292]
  PIN i_x[293]
    DIRECTION INPUT ;
    USE SIGNAL ;
    PORT
      LAYER M5 ;
        RECT  62.4 0 62.424 0.192 ;
    END
  END i_x[293]
  PIN i_x[294]
    DIRECTION INPUT ;
    USE SIGNAL ;
    PORT
      LAYER M5 ;
        RECT  62.592 0 62.616 0.192 ;
    END
  END i_x[294]
  PIN i_x[295]
    DIRECTION INPUT ;
    USE SIGNAL ;
    PORT
      LAYER M5 ;
        RECT  62.784 0 62.808 0.192 ;
    END
  END i_x[295]
  PIN i_x[296]
    DIRECTION INPUT ;
    USE SIGNAL ;
    PORT
      LAYER M5 ;
        RECT  62.976 0 63 0.192 ;
    END
  END i_x[296]
  PIN i_x[297]
    DIRECTION INPUT ;
    USE SIGNAL ;
    PORT
      LAYER M5 ;
        RECT  63.168 0 63.192 0.192 ;
    END
  END i_x[297]
  PIN i_x[298]
    DIRECTION INPUT ;
    USE SIGNAL ;
    PORT
      LAYER M5 ;
        RECT  63.36 0 63.384 0.192 ;
    END
  END i_x[298]
  PIN i_x[299]
    DIRECTION INPUT ;
    USE SIGNAL ;
    PORT
      LAYER M5 ;
        RECT  63.552 0 63.576 0.192 ;
    END
  END i_x[299]
  PIN i_x[29]
    DIRECTION INPUT ;
    USE SIGNAL ;
    PORT
      LAYER M5 ;
        RECT  11.712 0 11.736 0.192 ;
    END
  END i_x[29]
  PIN i_x[2]
    DIRECTION INPUT ;
    USE SIGNAL ;
    PORT
      LAYER M5 ;
        RECT  6.528 0 6.552 0.192 ;
    END
  END i_x[2]
  PIN i_x[300]
    DIRECTION INPUT ;
    USE SIGNAL ;
    PORT
      LAYER M5 ;
        RECT  63.744 0 63.768 0.192 ;
    END
  END i_x[300]
  PIN i_x[301]
    DIRECTION INPUT ;
    USE SIGNAL ;
    PORT
      LAYER M5 ;
        RECT  63.936 0 63.96 0.192 ;
    END
  END i_x[301]
  PIN i_x[302]
    DIRECTION INPUT ;
    USE SIGNAL ;
    PORT
      LAYER M5 ;
        RECT  64.128 0 64.152 0.192 ;
    END
  END i_x[302]
  PIN i_x[303]
    DIRECTION INPUT ;
    USE SIGNAL ;
    PORT
      LAYER M5 ;
        RECT  64.32 0 64.344 0.192 ;
    END
  END i_x[303]
  PIN i_x[304]
    DIRECTION INPUT ;
    USE SIGNAL ;
    PORT
      LAYER M5 ;
        RECT  64.512 0 64.536 0.192 ;
    END
  END i_x[304]
  PIN i_x[305]
    DIRECTION INPUT ;
    USE SIGNAL ;
    PORT
      LAYER M5 ;
        RECT  64.704 0 64.728 0.192 ;
    END
  END i_x[305]
  PIN i_x[306]
    DIRECTION INPUT ;
    USE SIGNAL ;
    PORT
      LAYER M5 ;
        RECT  64.896 0 64.92 0.192 ;
    END
  END i_x[306]
  PIN i_x[307]
    DIRECTION INPUT ;
    USE SIGNAL ;
    PORT
      LAYER M5 ;
        RECT  65.088 0 65.112 0.192 ;
    END
  END i_x[307]
  PIN i_x[308]
    DIRECTION INPUT ;
    USE SIGNAL ;
    PORT
      LAYER M5 ;
        RECT  65.28 0 65.304 0.192 ;
    END
  END i_x[308]
  PIN i_x[309]
    DIRECTION INPUT ;
    USE SIGNAL ;
    PORT
      LAYER M5 ;
        RECT  65.472 0 65.496 0.192 ;
    END
  END i_x[309]
  PIN i_x[30]
    DIRECTION INPUT ;
    USE SIGNAL ;
    PORT
      LAYER M5 ;
        RECT  11.904 0 11.928 0.192 ;
    END
  END i_x[30]
  PIN i_x[310]
    DIRECTION INPUT ;
    USE SIGNAL ;
    PORT
      LAYER M5 ;
        RECT  65.664 0 65.688 0.192 ;
    END
  END i_x[310]
  PIN i_x[311]
    DIRECTION INPUT ;
    USE SIGNAL ;
    PORT
      LAYER M5 ;
        RECT  65.856 0 65.88 0.192 ;
    END
  END i_x[311]
  PIN i_x[312]
    DIRECTION INPUT ;
    USE SIGNAL ;
    PORT
      LAYER M5 ;
        RECT  66.048 0 66.072 0.192 ;
    END
  END i_x[312]
  PIN i_x[313]
    DIRECTION INPUT ;
    USE SIGNAL ;
    PORT
      LAYER M5 ;
        RECT  66.24 0 66.264 0.192 ;
    END
  END i_x[313]
  PIN i_x[314]
    DIRECTION INPUT ;
    USE SIGNAL ;
    PORT
      LAYER M5 ;
        RECT  66.432 0 66.456 0.192 ;
    END
  END i_x[314]
  PIN i_x[315]
    DIRECTION INPUT ;
    USE SIGNAL ;
    PORT
      LAYER M5 ;
        RECT  66.624 0 66.648 0.192 ;
    END
  END i_x[315]
  PIN i_x[316]
    DIRECTION INPUT ;
    USE SIGNAL ;
    PORT
      LAYER M5 ;
        RECT  66.816 0 66.84 0.192 ;
    END
  END i_x[316]
  PIN i_x[317]
    DIRECTION INPUT ;
    USE SIGNAL ;
    PORT
      LAYER M5 ;
        RECT  67.008 0 67.032 0.192 ;
    END
  END i_x[317]
  PIN i_x[318]
    DIRECTION INPUT ;
    USE SIGNAL ;
    PORT
      LAYER M5 ;
        RECT  67.2 0 67.224 0.192 ;
    END
  END i_x[318]
  PIN i_x[319]
    DIRECTION INPUT ;
    USE SIGNAL ;
    PORT
      LAYER M5 ;
        RECT  67.392 0 67.416 0.192 ;
    END
  END i_x[319]
  PIN i_x[31]
    DIRECTION INPUT ;
    USE SIGNAL ;
    PORT
      LAYER M5 ;
        RECT  12.096 0 12.12 0.192 ;
    END
  END i_x[31]
  PIN i_x[320]
    DIRECTION INPUT ;
    USE SIGNAL ;
    PORT
      LAYER M5 ;
        RECT  67.584 0 67.608 0.192 ;
    END
  END i_x[320]
  PIN i_x[321]
    DIRECTION INPUT ;
    USE SIGNAL ;
    PORT
      LAYER M5 ;
        RECT  67.776 0 67.8 0.192 ;
    END
  END i_x[321]
  PIN i_x[322]
    DIRECTION INPUT ;
    USE SIGNAL ;
    PORT
      LAYER M5 ;
        RECT  67.968 0 67.992 0.192 ;
    END
  END i_x[322]
  PIN i_x[323]
    DIRECTION INPUT ;
    USE SIGNAL ;
    PORT
      LAYER M5 ;
        RECT  68.16 0 68.184 0.192 ;
    END
  END i_x[323]
  PIN i_x[324]
    DIRECTION INPUT ;
    USE SIGNAL ;
    PORT
      LAYER M5 ;
        RECT  68.352 0 68.376 0.192 ;
    END
  END i_x[324]
  PIN i_x[325]
    DIRECTION INPUT ;
    USE SIGNAL ;
    PORT
      LAYER M5 ;
        RECT  68.544 0 68.568 0.192 ;
    END
  END i_x[325]
  PIN i_x[326]
    DIRECTION INPUT ;
    USE SIGNAL ;
    PORT
      LAYER M5 ;
        RECT  68.736 0 68.76 0.192 ;
    END
  END i_x[326]
  PIN i_x[327]
    DIRECTION INPUT ;
    USE SIGNAL ;
    PORT
      LAYER M5 ;
        RECT  68.928 0 68.952 0.192 ;
    END
  END i_x[327]
  PIN i_x[328]
    DIRECTION INPUT ;
    USE SIGNAL ;
    PORT
      LAYER M5 ;
        RECT  69.12 0 69.144 0.192 ;
    END
  END i_x[328]
  PIN i_x[329]
    DIRECTION INPUT ;
    USE SIGNAL ;
    PORT
      LAYER M5 ;
        RECT  69.312 0 69.336 0.192 ;
    END
  END i_x[329]
  PIN i_x[32]
    DIRECTION INPUT ;
    USE SIGNAL ;
    PORT
      LAYER M5 ;
        RECT  12.288 0 12.312 0.192 ;
    END
  END i_x[32]
  PIN i_x[330]
    DIRECTION INPUT ;
    USE SIGNAL ;
    PORT
      LAYER M5 ;
        RECT  69.504 0 69.528 0.192 ;
    END
  END i_x[330]
  PIN i_x[331]
    DIRECTION INPUT ;
    USE SIGNAL ;
    PORT
      LAYER M5 ;
        RECT  69.696 0 69.72 0.192 ;
    END
  END i_x[331]
  PIN i_x[332]
    DIRECTION INPUT ;
    USE SIGNAL ;
    PORT
      LAYER M5 ;
        RECT  69.888 0 69.912 0.192 ;
    END
  END i_x[332]
  PIN i_x[333]
    DIRECTION INPUT ;
    USE SIGNAL ;
    PORT
      LAYER M5 ;
        RECT  70.08 0 70.104 0.192 ;
    END
  END i_x[333]
  PIN i_x[334]
    DIRECTION INPUT ;
    USE SIGNAL ;
    PORT
      LAYER M5 ;
        RECT  70.272 0 70.296 0.192 ;
    END
  END i_x[334]
  PIN i_x[335]
    DIRECTION INPUT ;
    USE SIGNAL ;
    PORT
      LAYER M5 ;
        RECT  70.464 0 70.488 0.192 ;
    END
  END i_x[335]
  PIN i_x[336]
    DIRECTION INPUT ;
    USE SIGNAL ;
    PORT
      LAYER M5 ;
        RECT  70.656 0 70.68 0.192 ;
    END
  END i_x[336]
  PIN i_x[337]
    DIRECTION INPUT ;
    USE SIGNAL ;
    PORT
      LAYER M5 ;
        RECT  70.848 0 70.872 0.192 ;
    END
  END i_x[337]
  PIN i_x[338]
    DIRECTION INPUT ;
    USE SIGNAL ;
    PORT
      LAYER M5 ;
        RECT  71.04 0 71.064 0.192 ;
    END
  END i_x[338]
  PIN i_x[339]
    DIRECTION INPUT ;
    USE SIGNAL ;
    PORT
      LAYER M5 ;
        RECT  71.232 0 71.256 0.192 ;
    END
  END i_x[339]
  PIN i_x[33]
    DIRECTION INPUT ;
    USE SIGNAL ;
    PORT
      LAYER M5 ;
        RECT  12.48 0 12.504 0.192 ;
    END
  END i_x[33]
  PIN i_x[340]
    DIRECTION INPUT ;
    USE SIGNAL ;
    PORT
      LAYER M5 ;
        RECT  71.424 0 71.448 0.192 ;
    END
  END i_x[340]
  PIN i_x[341]
    DIRECTION INPUT ;
    USE SIGNAL ;
    PORT
      LAYER M5 ;
        RECT  71.616 0 71.64 0.192 ;
    END
  END i_x[341]
  PIN i_x[342]
    DIRECTION INPUT ;
    USE SIGNAL ;
    PORT
      LAYER M5 ;
        RECT  71.808 0 71.832 0.192 ;
    END
  END i_x[342]
  PIN i_x[343]
    DIRECTION INPUT ;
    USE SIGNAL ;
    PORT
      LAYER M5 ;
        RECT  72 0 72.024 0.192 ;
    END
  END i_x[343]
  PIN i_x[344]
    DIRECTION INPUT ;
    USE SIGNAL ;
    PORT
      LAYER M5 ;
        RECT  72.192 0 72.216 0.192 ;
    END
  END i_x[344]
  PIN i_x[345]
    DIRECTION INPUT ;
    USE SIGNAL ;
    PORT
      LAYER M5 ;
        RECT  72.384 0 72.408 0.192 ;
    END
  END i_x[345]
  PIN i_x[346]
    DIRECTION INPUT ;
    USE SIGNAL ;
    PORT
      LAYER M5 ;
        RECT  72.576 0 72.6 0.192 ;
    END
  END i_x[346]
  PIN i_x[347]
    DIRECTION INPUT ;
    USE SIGNAL ;
    PORT
      LAYER M5 ;
        RECT  72.768 0 72.792 0.192 ;
    END
  END i_x[347]
  PIN i_x[348]
    DIRECTION INPUT ;
    USE SIGNAL ;
    PORT
      LAYER M5 ;
        RECT  72.96 0 72.984 0.192 ;
    END
  END i_x[348]
  PIN i_x[349]
    DIRECTION INPUT ;
    USE SIGNAL ;
    PORT
      LAYER M5 ;
        RECT  73.152 0 73.176 0.192 ;
    END
  END i_x[349]
  PIN i_x[34]
    DIRECTION INPUT ;
    USE SIGNAL ;
    PORT
      LAYER M5 ;
        RECT  12.672 0 12.696 0.192 ;
    END
  END i_x[34]
  PIN i_x[350]
    DIRECTION INPUT ;
    USE SIGNAL ;
    PORT
      LAYER M5 ;
        RECT  73.344 0 73.368 0.192 ;
    END
  END i_x[350]
  PIN i_x[351]
    DIRECTION INPUT ;
    USE SIGNAL ;
    PORT
      LAYER M5 ;
        RECT  73.536 0 73.56 0.192 ;
    END
  END i_x[351]
  PIN i_x[352]
    DIRECTION INPUT ;
    USE SIGNAL ;
    PORT
      LAYER M5 ;
        RECT  73.728 0 73.752 0.192 ;
    END
  END i_x[352]
  PIN i_x[353]
    DIRECTION INPUT ;
    USE SIGNAL ;
    PORT
      LAYER M5 ;
        RECT  73.92 0 73.944 0.192 ;
    END
  END i_x[353]
  PIN i_x[354]
    DIRECTION INPUT ;
    USE SIGNAL ;
    PORT
      LAYER M5 ;
        RECT  74.112 0 74.136 0.192 ;
    END
  END i_x[354]
  PIN i_x[355]
    DIRECTION INPUT ;
    USE SIGNAL ;
    PORT
      LAYER M5 ;
        RECT  74.304 0 74.328 0.192 ;
    END
  END i_x[355]
  PIN i_x[356]
    DIRECTION INPUT ;
    USE SIGNAL ;
    PORT
      LAYER M5 ;
        RECT  74.496 0 74.52 0.192 ;
    END
  END i_x[356]
  PIN i_x[357]
    DIRECTION INPUT ;
    USE SIGNAL ;
    PORT
      LAYER M5 ;
        RECT  74.688 0 74.712 0.192 ;
    END
  END i_x[357]
  PIN i_x[358]
    DIRECTION INPUT ;
    USE SIGNAL ;
    PORT
      LAYER M5 ;
        RECT  74.88 0 74.904 0.192 ;
    END
  END i_x[358]
  PIN i_x[359]
    DIRECTION INPUT ;
    USE SIGNAL ;
    PORT
      LAYER M5 ;
        RECT  75.072 0 75.096 0.192 ;
    END
  END i_x[359]
  PIN i_x[35]
    DIRECTION INPUT ;
    USE SIGNAL ;
    PORT
      LAYER M5 ;
        RECT  12.864 0 12.888 0.192 ;
    END
  END i_x[35]
  PIN i_x[360]
    DIRECTION INPUT ;
    USE SIGNAL ;
    PORT
      LAYER M5 ;
        RECT  75.264 0 75.288 0.192 ;
    END
  END i_x[360]
  PIN i_x[361]
    DIRECTION INPUT ;
    USE SIGNAL ;
    PORT
      LAYER M5 ;
        RECT  75.456 0 75.48 0.192 ;
    END
  END i_x[361]
  PIN i_x[362]
    DIRECTION INPUT ;
    USE SIGNAL ;
    PORT
      LAYER M5 ;
        RECT  75.648 0 75.672 0.192 ;
    END
  END i_x[362]
  PIN i_x[363]
    DIRECTION INPUT ;
    USE SIGNAL ;
    PORT
      LAYER M5 ;
        RECT  75.84 0 75.864 0.192 ;
    END
  END i_x[363]
  PIN i_x[364]
    DIRECTION INPUT ;
    USE SIGNAL ;
    PORT
      LAYER M5 ;
        RECT  76.032 0 76.056 0.192 ;
    END
  END i_x[364]
  PIN i_x[365]
    DIRECTION INPUT ;
    USE SIGNAL ;
    PORT
      LAYER M5 ;
        RECT  76.224 0 76.248 0.192 ;
    END
  END i_x[365]
  PIN i_x[366]
    DIRECTION INPUT ;
    USE SIGNAL ;
    PORT
      LAYER M5 ;
        RECT  76.416 0 76.44 0.192 ;
    END
  END i_x[366]
  PIN i_x[367]
    DIRECTION INPUT ;
    USE SIGNAL ;
    PORT
      LAYER M5 ;
        RECT  76.608 0 76.632 0.192 ;
    END
  END i_x[367]
  PIN i_x[368]
    DIRECTION INPUT ;
    USE SIGNAL ;
    PORT
      LAYER M5 ;
        RECT  76.8 0 76.824 0.192 ;
    END
  END i_x[368]
  PIN i_x[369]
    DIRECTION INPUT ;
    USE SIGNAL ;
    PORT
      LAYER M5 ;
        RECT  76.992 0 77.016 0.192 ;
    END
  END i_x[369]
  PIN i_x[36]
    DIRECTION INPUT ;
    USE SIGNAL ;
    PORT
      LAYER M5 ;
        RECT  13.056 0 13.08 0.192 ;
    END
  END i_x[36]
  PIN i_x[370]
    DIRECTION INPUT ;
    USE SIGNAL ;
    PORT
      LAYER M5 ;
        RECT  77.184 0 77.208 0.192 ;
    END
  END i_x[370]
  PIN i_x[371]
    DIRECTION INPUT ;
    USE SIGNAL ;
    PORT
      LAYER M5 ;
        RECT  77.376 0 77.4 0.192 ;
    END
  END i_x[371]
  PIN i_x[372]
    DIRECTION INPUT ;
    USE SIGNAL ;
    PORT
      LAYER M5 ;
        RECT  77.568 0 77.592 0.192 ;
    END
  END i_x[372]
  PIN i_x[373]
    DIRECTION INPUT ;
    USE SIGNAL ;
    PORT
      LAYER M5 ;
        RECT  77.76 0 77.784 0.192 ;
    END
  END i_x[373]
  PIN i_x[374]
    DIRECTION INPUT ;
    USE SIGNAL ;
    PORT
      LAYER M5 ;
        RECT  77.952 0 77.976 0.192 ;
    END
  END i_x[374]
  PIN i_x[375]
    DIRECTION INPUT ;
    USE SIGNAL ;
    PORT
      LAYER M5 ;
        RECT  78.144 0 78.168 0.192 ;
    END
  END i_x[375]
  PIN i_x[376]
    DIRECTION INPUT ;
    USE SIGNAL ;
    PORT
      LAYER M5 ;
        RECT  78.336 0 78.36 0.192 ;
    END
  END i_x[376]
  PIN i_x[377]
    DIRECTION INPUT ;
    USE SIGNAL ;
    PORT
      LAYER M5 ;
        RECT  78.528 0 78.552 0.192 ;
    END
  END i_x[377]
  PIN i_x[378]
    DIRECTION INPUT ;
    USE SIGNAL ;
    PORT
      LAYER M5 ;
        RECT  78.72 0 78.744 0.192 ;
    END
  END i_x[378]
  PIN i_x[379]
    DIRECTION INPUT ;
    USE SIGNAL ;
    PORT
      LAYER M5 ;
        RECT  78.912 0 78.936 0.192 ;
    END
  END i_x[379]
  PIN i_x[37]
    DIRECTION INPUT ;
    USE SIGNAL ;
    PORT
      LAYER M5 ;
        RECT  13.248 0 13.272 0.192 ;
    END
  END i_x[37]
  PIN i_x[380]
    DIRECTION INPUT ;
    USE SIGNAL ;
    PORT
      LAYER M5 ;
        RECT  79.104 0 79.128 0.192 ;
    END
  END i_x[380]
  PIN i_x[381]
    DIRECTION INPUT ;
    USE SIGNAL ;
    PORT
      LAYER M5 ;
        RECT  79.296 0 79.32 0.192 ;
    END
  END i_x[381]
  PIN i_x[382]
    DIRECTION INPUT ;
    USE SIGNAL ;
    PORT
      LAYER M5 ;
        RECT  79.488 0 79.512 0.192 ;
    END
  END i_x[382]
  PIN i_x[383]
    DIRECTION INPUT ;
    USE SIGNAL ;
    PORT
      LAYER M5 ;
        RECT  79.68 0 79.704 0.192 ;
    END
  END i_x[383]
  PIN i_x[384]
    DIRECTION INPUT ;
    USE SIGNAL ;
    PORT
      LAYER M5 ;
        RECT  79.872 0 79.896 0.192 ;
    END
  END i_x[384]
  PIN i_x[385]
    DIRECTION INPUT ;
    USE SIGNAL ;
    PORT
      LAYER M5 ;
        RECT  80.064 0 80.088 0.192 ;
    END
  END i_x[385]
  PIN i_x[386]
    DIRECTION INPUT ;
    USE SIGNAL ;
    PORT
      LAYER M5 ;
        RECT  80.256 0 80.28 0.192 ;
    END
  END i_x[386]
  PIN i_x[387]
    DIRECTION INPUT ;
    USE SIGNAL ;
    PORT
      LAYER M5 ;
        RECT  80.448 0 80.472 0.192 ;
    END
  END i_x[387]
  PIN i_x[388]
    DIRECTION INPUT ;
    USE SIGNAL ;
    PORT
      LAYER M5 ;
        RECT  80.64 0 80.664 0.192 ;
    END
  END i_x[388]
  PIN i_x[389]
    DIRECTION INPUT ;
    USE SIGNAL ;
    PORT
      LAYER M5 ;
        RECT  80.832 0 80.856 0.192 ;
    END
  END i_x[389]
  PIN i_x[38]
    DIRECTION INPUT ;
    USE SIGNAL ;
    PORT
      LAYER M5 ;
        RECT  13.44 0 13.464 0.192 ;
    END
  END i_x[38]
  PIN i_x[390]
    DIRECTION INPUT ;
    USE SIGNAL ;
    PORT
      LAYER M5 ;
        RECT  81.024 0 81.048 0.192 ;
    END
  END i_x[390]
  PIN i_x[391]
    DIRECTION INPUT ;
    USE SIGNAL ;
    PORT
      LAYER M5 ;
        RECT  81.216 0 81.24 0.192 ;
    END
  END i_x[391]
  PIN i_x[392]
    DIRECTION INPUT ;
    USE SIGNAL ;
    PORT
      LAYER M5 ;
        RECT  81.408 0 81.432 0.192 ;
    END
  END i_x[392]
  PIN i_x[393]
    DIRECTION INPUT ;
    USE SIGNAL ;
    PORT
      LAYER M5 ;
        RECT  81.6 0 81.624 0.192 ;
    END
  END i_x[393]
  PIN i_x[394]
    DIRECTION INPUT ;
    USE SIGNAL ;
    PORT
      LAYER M5 ;
        RECT  81.792 0 81.816 0.192 ;
    END
  END i_x[394]
  PIN i_x[395]
    DIRECTION INPUT ;
    USE SIGNAL ;
    PORT
      LAYER M5 ;
        RECT  81.984 0 82.008 0.192 ;
    END
  END i_x[395]
  PIN i_x[396]
    DIRECTION INPUT ;
    USE SIGNAL ;
    PORT
      LAYER M5 ;
        RECT  82.176 0 82.2 0.192 ;
    END
  END i_x[396]
  PIN i_x[397]
    DIRECTION INPUT ;
    USE SIGNAL ;
    PORT
      LAYER M5 ;
        RECT  82.368 0 82.392 0.192 ;
    END
  END i_x[397]
  PIN i_x[398]
    DIRECTION INPUT ;
    USE SIGNAL ;
    PORT
      LAYER M5 ;
        RECT  82.56 0 82.584 0.192 ;
    END
  END i_x[398]
  PIN i_x[399]
    DIRECTION INPUT ;
    USE SIGNAL ;
    PORT
      LAYER M5 ;
        RECT  82.752 0 82.776 0.192 ;
    END
  END i_x[399]
  PIN i_x[39]
    DIRECTION INPUT ;
    USE SIGNAL ;
    PORT
      LAYER M5 ;
        RECT  13.632 0 13.656 0.192 ;
    END
  END i_x[39]
  PIN i_x[3]
    DIRECTION INPUT ;
    USE SIGNAL ;
    PORT
      LAYER M5 ;
        RECT  6.72 0 6.744 0.192 ;
    END
  END i_x[3]
  PIN i_x[400]
    DIRECTION INPUT ;
    USE SIGNAL ;
    PORT
      LAYER M5 ;
        RECT  82.944 0 82.968 0.192 ;
    END
  END i_x[400]
  PIN i_x[401]
    DIRECTION INPUT ;
    USE SIGNAL ;
    PORT
      LAYER M5 ;
        RECT  83.136 0 83.16 0.192 ;
    END
  END i_x[401]
  PIN i_x[402]
    DIRECTION INPUT ;
    USE SIGNAL ;
    PORT
      LAYER M5 ;
        RECT  83.328 0 83.352 0.192 ;
    END
  END i_x[402]
  PIN i_x[403]
    DIRECTION INPUT ;
    USE SIGNAL ;
    PORT
      LAYER M5 ;
        RECT  83.52 0 83.544 0.192 ;
    END
  END i_x[403]
  PIN i_x[404]
    DIRECTION INPUT ;
    USE SIGNAL ;
    PORT
      LAYER M5 ;
        RECT  83.712 0 83.736 0.192 ;
    END
  END i_x[404]
  PIN i_x[405]
    DIRECTION INPUT ;
    USE SIGNAL ;
    PORT
      LAYER M5 ;
        RECT  83.904 0 83.928 0.192 ;
    END
  END i_x[405]
  PIN i_x[406]
    DIRECTION INPUT ;
    USE SIGNAL ;
    PORT
      LAYER M5 ;
        RECT  84.096 0 84.12 0.192 ;
    END
  END i_x[406]
  PIN i_x[407]
    DIRECTION INPUT ;
    USE SIGNAL ;
    PORT
      LAYER M5 ;
        RECT  84.288 0 84.312 0.192 ;
    END
  END i_x[407]
  PIN i_x[408]
    DIRECTION INPUT ;
    USE SIGNAL ;
    PORT
      LAYER M5 ;
        RECT  84.48 0 84.504 0.192 ;
    END
  END i_x[408]
  PIN i_x[409]
    DIRECTION INPUT ;
    USE SIGNAL ;
    PORT
      LAYER M5 ;
        RECT  84.672 0 84.696 0.192 ;
    END
  END i_x[409]
  PIN i_x[40]
    DIRECTION INPUT ;
    USE SIGNAL ;
    PORT
      LAYER M5 ;
        RECT  13.824 0 13.848 0.192 ;
    END
  END i_x[40]
  PIN i_x[410]
    DIRECTION INPUT ;
    USE SIGNAL ;
    PORT
      LAYER M5 ;
        RECT  84.864 0 84.888 0.192 ;
    END
  END i_x[410]
  PIN i_x[411]
    DIRECTION INPUT ;
    USE SIGNAL ;
    PORT
      LAYER M5 ;
        RECT  85.056 0 85.08 0.192 ;
    END
  END i_x[411]
  PIN i_x[412]
    DIRECTION INPUT ;
    USE SIGNAL ;
    PORT
      LAYER M5 ;
        RECT  85.248 0 85.272 0.192 ;
    END
  END i_x[412]
  PIN i_x[413]
    DIRECTION INPUT ;
    USE SIGNAL ;
    PORT
      LAYER M5 ;
        RECT  85.44 0 85.464 0.192 ;
    END
  END i_x[413]
  PIN i_x[414]
    DIRECTION INPUT ;
    USE SIGNAL ;
    PORT
      LAYER M5 ;
        RECT  85.632 0 85.656 0.192 ;
    END
  END i_x[414]
  PIN i_x[415]
    DIRECTION INPUT ;
    USE SIGNAL ;
    PORT
      LAYER M5 ;
        RECT  85.824 0 85.848 0.192 ;
    END
  END i_x[415]
  PIN i_x[416]
    DIRECTION INPUT ;
    USE SIGNAL ;
    PORT
      LAYER M5 ;
        RECT  86.016 0 86.04 0.192 ;
    END
  END i_x[416]
  PIN i_x[417]
    DIRECTION INPUT ;
    USE SIGNAL ;
    PORT
      LAYER M5 ;
        RECT  86.208 0 86.232 0.192 ;
    END
  END i_x[417]
  PIN i_x[418]
    DIRECTION INPUT ;
    USE SIGNAL ;
    PORT
      LAYER M5 ;
        RECT  86.4 0 86.424 0.192 ;
    END
  END i_x[418]
  PIN i_x[419]
    DIRECTION INPUT ;
    USE SIGNAL ;
    PORT
      LAYER M5 ;
        RECT  86.592 0 86.616 0.192 ;
    END
  END i_x[419]
  PIN i_x[41]
    DIRECTION INPUT ;
    USE SIGNAL ;
    PORT
      LAYER M5 ;
        RECT  14.016 0 14.04 0.192 ;
    END
  END i_x[41]
  PIN i_x[420]
    DIRECTION INPUT ;
    USE SIGNAL ;
    PORT
      LAYER M5 ;
        RECT  86.784 0 86.808 0.192 ;
    END
  END i_x[420]
  PIN i_x[421]
    DIRECTION INPUT ;
    USE SIGNAL ;
    PORT
      LAYER M5 ;
        RECT  86.976 0 87 0.192 ;
    END
  END i_x[421]
  PIN i_x[422]
    DIRECTION INPUT ;
    USE SIGNAL ;
    PORT
      LAYER M5 ;
        RECT  87.168 0 87.192 0.192 ;
    END
  END i_x[422]
  PIN i_x[423]
    DIRECTION INPUT ;
    USE SIGNAL ;
    PORT
      LAYER M5 ;
        RECT  87.36 0 87.384 0.192 ;
    END
  END i_x[423]
  PIN i_x[424]
    DIRECTION INPUT ;
    USE SIGNAL ;
    PORT
      LAYER M5 ;
        RECT  87.552 0 87.576 0.192 ;
    END
  END i_x[424]
  PIN i_x[425]
    DIRECTION INPUT ;
    USE SIGNAL ;
    PORT
      LAYER M5 ;
        RECT  87.744 0 87.768 0.192 ;
    END
  END i_x[425]
  PIN i_x[426]
    DIRECTION INPUT ;
    USE SIGNAL ;
    PORT
      LAYER M5 ;
        RECT  87.936 0 87.96 0.192 ;
    END
  END i_x[426]
  PIN i_x[427]
    DIRECTION INPUT ;
    USE SIGNAL ;
    PORT
      LAYER M5 ;
        RECT  88.128 0 88.152 0.192 ;
    END
  END i_x[427]
  PIN i_x[428]
    DIRECTION INPUT ;
    USE SIGNAL ;
    PORT
      LAYER M5 ;
        RECT  88.32 0 88.344 0.192 ;
    END
  END i_x[428]
  PIN i_x[429]
    DIRECTION INPUT ;
    USE SIGNAL ;
    PORT
      LAYER M5 ;
        RECT  88.512 0 88.536 0.192 ;
    END
  END i_x[429]
  PIN i_x[42]
    DIRECTION INPUT ;
    USE SIGNAL ;
    PORT
      LAYER M5 ;
        RECT  14.208 0 14.232 0.192 ;
    END
  END i_x[42]
  PIN i_x[430]
    DIRECTION INPUT ;
    USE SIGNAL ;
    PORT
      LAYER M5 ;
        RECT  88.704 0 88.728 0.192 ;
    END
  END i_x[430]
  PIN i_x[431]
    DIRECTION INPUT ;
    USE SIGNAL ;
    PORT
      LAYER M5 ;
        RECT  88.896 0 88.92 0.192 ;
    END
  END i_x[431]
  PIN i_x[432]
    DIRECTION INPUT ;
    USE SIGNAL ;
    PORT
      LAYER M5 ;
        RECT  89.088 0 89.112 0.192 ;
    END
  END i_x[432]
  PIN i_x[433]
    DIRECTION INPUT ;
    USE SIGNAL ;
    PORT
      LAYER M5 ;
        RECT  89.28 0 89.304 0.192 ;
    END
  END i_x[433]
  PIN i_x[434]
    DIRECTION INPUT ;
    USE SIGNAL ;
    PORT
      LAYER M5 ;
        RECT  89.472 0 89.496 0.192 ;
    END
  END i_x[434]
  PIN i_x[435]
    DIRECTION INPUT ;
    USE SIGNAL ;
    PORT
      LAYER M5 ;
        RECT  89.664 0 89.688 0.192 ;
    END
  END i_x[435]
  PIN i_x[436]
    DIRECTION INPUT ;
    USE SIGNAL ;
    PORT
      LAYER M5 ;
        RECT  89.856 0 89.88 0.192 ;
    END
  END i_x[436]
  PIN i_x[437]
    DIRECTION INPUT ;
    USE SIGNAL ;
    PORT
      LAYER M5 ;
        RECT  90.048 0 90.072 0.192 ;
    END
  END i_x[437]
  PIN i_x[438]
    DIRECTION INPUT ;
    USE SIGNAL ;
    PORT
      LAYER M5 ;
        RECT  90.24 0 90.264 0.192 ;
    END
  END i_x[438]
  PIN i_x[439]
    DIRECTION INPUT ;
    USE SIGNAL ;
    PORT
      LAYER M5 ;
        RECT  90.432 0 90.456 0.192 ;
    END
  END i_x[439]
  PIN i_x[43]
    DIRECTION INPUT ;
    USE SIGNAL ;
    PORT
      LAYER M5 ;
        RECT  14.4 0 14.424 0.192 ;
    END
  END i_x[43]
  PIN i_x[440]
    DIRECTION INPUT ;
    USE SIGNAL ;
    PORT
      LAYER M5 ;
        RECT  90.624 0 90.648 0.192 ;
    END
  END i_x[440]
  PIN i_x[441]
    DIRECTION INPUT ;
    USE SIGNAL ;
    PORT
      LAYER M5 ;
        RECT  90.816 0 90.84 0.192 ;
    END
  END i_x[441]
  PIN i_x[442]
    DIRECTION INPUT ;
    USE SIGNAL ;
    PORT
      LAYER M5 ;
        RECT  91.008 0 91.032 0.192 ;
    END
  END i_x[442]
  PIN i_x[443]
    DIRECTION INPUT ;
    USE SIGNAL ;
    PORT
      LAYER M5 ;
        RECT  91.2 0 91.224 0.192 ;
    END
  END i_x[443]
  PIN i_x[444]
    DIRECTION INPUT ;
    USE SIGNAL ;
    PORT
      LAYER M5 ;
        RECT  91.392 0 91.416 0.192 ;
    END
  END i_x[444]
  PIN i_x[445]
    DIRECTION INPUT ;
    USE SIGNAL ;
    PORT
      LAYER M5 ;
        RECT  91.584 0 91.608 0.192 ;
    END
  END i_x[445]
  PIN i_x[446]
    DIRECTION INPUT ;
    USE SIGNAL ;
    PORT
      LAYER M5 ;
        RECT  91.776 0 91.8 0.192 ;
    END
  END i_x[446]
  PIN i_x[447]
    DIRECTION INPUT ;
    USE SIGNAL ;
    PORT
      LAYER M5 ;
        RECT  91.968 0 91.992 0.192 ;
    END
  END i_x[447]
  PIN i_x[448]
    DIRECTION INPUT ;
    USE SIGNAL ;
    PORT
      LAYER M5 ;
        RECT  92.16 0 92.184 0.192 ;
    END
  END i_x[448]
  PIN i_x[449]
    DIRECTION INPUT ;
    USE SIGNAL ;
    PORT
      LAYER M5 ;
        RECT  92.352 0 92.376 0.192 ;
    END
  END i_x[449]
  PIN i_x[44]
    DIRECTION INPUT ;
    USE SIGNAL ;
    PORT
      LAYER M5 ;
        RECT  14.592 0 14.616 0.192 ;
    END
  END i_x[44]
  PIN i_x[450]
    DIRECTION INPUT ;
    USE SIGNAL ;
    PORT
      LAYER M5 ;
        RECT  92.544 0 92.568 0.192 ;
    END
  END i_x[450]
  PIN i_x[451]
    DIRECTION INPUT ;
    USE SIGNAL ;
    PORT
      LAYER M5 ;
        RECT  92.736 0 92.76 0.192 ;
    END
  END i_x[451]
  PIN i_x[452]
    DIRECTION INPUT ;
    USE SIGNAL ;
    PORT
      LAYER M5 ;
        RECT  92.928 0 92.952 0.192 ;
    END
  END i_x[452]
  PIN i_x[453]
    DIRECTION INPUT ;
    USE SIGNAL ;
    PORT
      LAYER M5 ;
        RECT  93.12 0 93.144 0.192 ;
    END
  END i_x[453]
  PIN i_x[454]
    DIRECTION INPUT ;
    USE SIGNAL ;
    PORT
      LAYER M5 ;
        RECT  93.312 0 93.336 0.192 ;
    END
  END i_x[454]
  PIN i_x[455]
    DIRECTION INPUT ;
    USE SIGNAL ;
    PORT
      LAYER M5 ;
        RECT  93.504 0 93.528 0.192 ;
    END
  END i_x[455]
  PIN i_x[456]
    DIRECTION INPUT ;
    USE SIGNAL ;
    PORT
      LAYER M5 ;
        RECT  93.696 0 93.72 0.192 ;
    END
  END i_x[456]
  PIN i_x[457]
    DIRECTION INPUT ;
    USE SIGNAL ;
    PORT
      LAYER M5 ;
        RECT  93.888 0 93.912 0.192 ;
    END
  END i_x[457]
  PIN i_x[458]
    DIRECTION INPUT ;
    USE SIGNAL ;
    PORT
      LAYER M5 ;
        RECT  94.08 0 94.104 0.192 ;
    END
  END i_x[458]
  PIN i_x[459]
    DIRECTION INPUT ;
    USE SIGNAL ;
    PORT
      LAYER M5 ;
        RECT  94.272 0 94.296 0.192 ;
    END
  END i_x[459]
  PIN i_x[45]
    DIRECTION INPUT ;
    USE SIGNAL ;
    PORT
      LAYER M5 ;
        RECT  14.784 0 14.808 0.192 ;
    END
  END i_x[45]
  PIN i_x[460]
    DIRECTION INPUT ;
    USE SIGNAL ;
    PORT
      LAYER M5 ;
        RECT  94.464 0 94.488 0.192 ;
    END
  END i_x[460]
  PIN i_x[461]
    DIRECTION INPUT ;
    USE SIGNAL ;
    PORT
      LAYER M5 ;
        RECT  94.656 0 94.68 0.192 ;
    END
  END i_x[461]
  PIN i_x[462]
    DIRECTION INPUT ;
    USE SIGNAL ;
    PORT
      LAYER M5 ;
        RECT  94.848 0 94.872 0.192 ;
    END
  END i_x[462]
  PIN i_x[463]
    DIRECTION INPUT ;
    USE SIGNAL ;
    PORT
      LAYER M5 ;
        RECT  95.04 0 95.064 0.192 ;
    END
  END i_x[463]
  PIN i_x[464]
    DIRECTION INPUT ;
    USE SIGNAL ;
    PORT
      LAYER M5 ;
        RECT  95.232 0 95.256 0.192 ;
    END
  END i_x[464]
  PIN i_x[465]
    DIRECTION INPUT ;
    USE SIGNAL ;
    PORT
      LAYER M5 ;
        RECT  95.424 0 95.448 0.192 ;
    END
  END i_x[465]
  PIN i_x[466]
    DIRECTION INPUT ;
    USE SIGNAL ;
    PORT
      LAYER M5 ;
        RECT  95.616 0 95.64 0.192 ;
    END
  END i_x[466]
  PIN i_x[467]
    DIRECTION INPUT ;
    USE SIGNAL ;
    PORT
      LAYER M5 ;
        RECT  95.808 0 95.832 0.192 ;
    END
  END i_x[467]
  PIN i_x[468]
    DIRECTION INPUT ;
    USE SIGNAL ;
    PORT
      LAYER M5 ;
        RECT  96 0 96.024 0.192 ;
    END
  END i_x[468]
  PIN i_x[469]
    DIRECTION INPUT ;
    USE SIGNAL ;
    PORT
      LAYER M5 ;
        RECT  96.192 0 96.216 0.192 ;
    END
  END i_x[469]
  PIN i_x[46]
    DIRECTION INPUT ;
    USE SIGNAL ;
    PORT
      LAYER M5 ;
        RECT  14.976 0 15 0.192 ;
    END
  END i_x[46]
  PIN i_x[470]
    DIRECTION INPUT ;
    USE SIGNAL ;
    PORT
      LAYER M5 ;
        RECT  96.384 0 96.408 0.192 ;
    END
  END i_x[470]
  PIN i_x[471]
    DIRECTION INPUT ;
    USE SIGNAL ;
    PORT
      LAYER M5 ;
        RECT  96.576 0 96.6 0.192 ;
    END
  END i_x[471]
  PIN i_x[472]
    DIRECTION INPUT ;
    USE SIGNAL ;
    PORT
      LAYER M5 ;
        RECT  96.768 0 96.792 0.192 ;
    END
  END i_x[472]
  PIN i_x[473]
    DIRECTION INPUT ;
    USE SIGNAL ;
    PORT
      LAYER M5 ;
        RECT  96.96 0 96.984 0.192 ;
    END
  END i_x[473]
  PIN i_x[474]
    DIRECTION INPUT ;
    USE SIGNAL ;
    PORT
      LAYER M5 ;
        RECT  97.152 0 97.176 0.192 ;
    END
  END i_x[474]
  PIN i_x[475]
    DIRECTION INPUT ;
    USE SIGNAL ;
    PORT
      LAYER M5 ;
        RECT  97.344 0 97.368 0.192 ;
    END
  END i_x[475]
  PIN i_x[476]
    DIRECTION INPUT ;
    USE SIGNAL ;
    PORT
      LAYER M5 ;
        RECT  97.536 0 97.56 0.192 ;
    END
  END i_x[476]
  PIN i_x[477]
    DIRECTION INPUT ;
    USE SIGNAL ;
    PORT
      LAYER M5 ;
        RECT  97.728 0 97.752 0.192 ;
    END
  END i_x[477]
  PIN i_x[478]
    DIRECTION INPUT ;
    USE SIGNAL ;
    PORT
      LAYER M5 ;
        RECT  97.92 0 97.944 0.192 ;
    END
  END i_x[478]
  PIN i_x[479]
    DIRECTION INPUT ;
    USE SIGNAL ;
    PORT
      LAYER M5 ;
        RECT  98.112 0 98.136 0.192 ;
    END
  END i_x[479]
  PIN i_x[47]
    DIRECTION INPUT ;
    USE SIGNAL ;
    PORT
      LAYER M5 ;
        RECT  15.168 0 15.192 0.192 ;
    END
  END i_x[47]
  PIN i_x[480]
    DIRECTION INPUT ;
    USE SIGNAL ;
    PORT
      LAYER M5 ;
        RECT  98.304 0 98.328 0.192 ;
    END
  END i_x[480]
  PIN i_x[481]
    DIRECTION INPUT ;
    USE SIGNAL ;
    PORT
      LAYER M5 ;
        RECT  98.496 0 98.52 0.192 ;
    END
  END i_x[481]
  PIN i_x[482]
    DIRECTION INPUT ;
    USE SIGNAL ;
    PORT
      LAYER M5 ;
        RECT  98.688 0 98.712 0.192 ;
    END
  END i_x[482]
  PIN i_x[483]
    DIRECTION INPUT ;
    USE SIGNAL ;
    PORT
      LAYER M5 ;
        RECT  98.88 0 98.904 0.192 ;
    END
  END i_x[483]
  PIN i_x[484]
    DIRECTION INPUT ;
    USE SIGNAL ;
    PORT
      LAYER M5 ;
        RECT  99.072 0 99.096 0.192 ;
    END
  END i_x[484]
  PIN i_x[485]
    DIRECTION INPUT ;
    USE SIGNAL ;
    PORT
      LAYER M5 ;
        RECT  99.264 0 99.288 0.192 ;
    END
  END i_x[485]
  PIN i_x[486]
    DIRECTION INPUT ;
    USE SIGNAL ;
    PORT
      LAYER M5 ;
        RECT  99.456 0 99.48 0.192 ;
    END
  END i_x[486]
  PIN i_x[487]
    DIRECTION INPUT ;
    USE SIGNAL ;
    PORT
      LAYER M5 ;
        RECT  99.648 0 99.672 0.192 ;
    END
  END i_x[487]
  PIN i_x[488]
    DIRECTION INPUT ;
    USE SIGNAL ;
    PORT
      LAYER M5 ;
        RECT  99.84 0 99.864 0.192 ;
    END
  END i_x[488]
  PIN i_x[489]
    DIRECTION INPUT ;
    USE SIGNAL ;
    PORT
      LAYER M5 ;
        RECT  100.032 0 100.056 0.192 ;
    END
  END i_x[489]
  PIN i_x[48]
    DIRECTION INPUT ;
    USE SIGNAL ;
    PORT
      LAYER M5 ;
        RECT  15.36 0 15.384 0.192 ;
    END
  END i_x[48]
  PIN i_x[490]
    DIRECTION INPUT ;
    USE SIGNAL ;
    PORT
      LAYER M5 ;
        RECT  100.224 0 100.248 0.192 ;
    END
  END i_x[490]
  PIN i_x[491]
    DIRECTION INPUT ;
    USE SIGNAL ;
    PORT
      LAYER M5 ;
        RECT  100.416 0 100.44 0.192 ;
    END
  END i_x[491]
  PIN i_x[492]
    DIRECTION INPUT ;
    USE SIGNAL ;
    PORT
      LAYER M5 ;
        RECT  100.608 0 100.632 0.192 ;
    END
  END i_x[492]
  PIN i_x[493]
    DIRECTION INPUT ;
    USE SIGNAL ;
    PORT
      LAYER M5 ;
        RECT  100.8 0 100.824 0.192 ;
    END
  END i_x[493]
  PIN i_x[494]
    DIRECTION INPUT ;
    USE SIGNAL ;
    PORT
      LAYER M5 ;
        RECT  100.992 0 101.016 0.192 ;
    END
  END i_x[494]
  PIN i_x[495]
    DIRECTION INPUT ;
    USE SIGNAL ;
    PORT
      LAYER M5 ;
        RECT  101.184 0 101.208 0.192 ;
    END
  END i_x[495]
  PIN i_x[496]
    DIRECTION INPUT ;
    USE SIGNAL ;
    PORT
      LAYER M5 ;
        RECT  101.376 0 101.4 0.192 ;
    END
  END i_x[496]
  PIN i_x[497]
    DIRECTION INPUT ;
    USE SIGNAL ;
    PORT
      LAYER M5 ;
        RECT  101.568 0 101.592 0.192 ;
    END
  END i_x[497]
  PIN i_x[498]
    DIRECTION INPUT ;
    USE SIGNAL ;
    PORT
      LAYER M5 ;
        RECT  101.76 0 101.784 0.192 ;
    END
  END i_x[498]
  PIN i_x[499]
    DIRECTION INPUT ;
    USE SIGNAL ;
    PORT
      LAYER M5 ;
        RECT  101.952 0 101.976 0.192 ;
    END
  END i_x[499]
  PIN i_x[49]
    DIRECTION INPUT ;
    USE SIGNAL ;
    PORT
      LAYER M5 ;
        RECT  15.552 0 15.576 0.192 ;
    END
  END i_x[49]
  PIN i_x[4]
    DIRECTION INPUT ;
    USE SIGNAL ;
    PORT
      LAYER M5 ;
        RECT  6.912 0 6.936 0.192 ;
    END
  END i_x[4]
  PIN i_x[500]
    DIRECTION INPUT ;
    USE SIGNAL ;
    PORT
      LAYER M5 ;
        RECT  102.144 0 102.168 0.192 ;
    END
  END i_x[500]
  PIN i_x[501]
    DIRECTION INPUT ;
    USE SIGNAL ;
    PORT
      LAYER M5 ;
        RECT  102.336 0 102.36 0.192 ;
    END
  END i_x[501]
  PIN i_x[502]
    DIRECTION INPUT ;
    USE SIGNAL ;
    PORT
      LAYER M5 ;
        RECT  102.528 0 102.552 0.192 ;
    END
  END i_x[502]
  PIN i_x[503]
    DIRECTION INPUT ;
    USE SIGNAL ;
    PORT
      LAYER M5 ;
        RECT  102.72 0 102.744 0.192 ;
    END
  END i_x[503]
  PIN i_x[504]
    DIRECTION INPUT ;
    USE SIGNAL ;
    PORT
      LAYER M5 ;
        RECT  102.912 0 102.936 0.192 ;
    END
  END i_x[504]
  PIN i_x[505]
    DIRECTION INPUT ;
    USE SIGNAL ;
    PORT
      LAYER M5 ;
        RECT  103.104 0 103.128 0.192 ;
    END
  END i_x[505]
  PIN i_x[506]
    DIRECTION INPUT ;
    USE SIGNAL ;
    PORT
      LAYER M5 ;
        RECT  103.296 0 103.32 0.192 ;
    END
  END i_x[506]
  PIN i_x[507]
    DIRECTION INPUT ;
    USE SIGNAL ;
    PORT
      LAYER M5 ;
        RECT  103.488 0 103.512 0.192 ;
    END
  END i_x[507]
  PIN i_x[508]
    DIRECTION INPUT ;
    USE SIGNAL ;
    PORT
      LAYER M5 ;
        RECT  103.68 0 103.704 0.192 ;
    END
  END i_x[508]
  PIN i_x[509]
    DIRECTION INPUT ;
    USE SIGNAL ;
    PORT
      LAYER M5 ;
        RECT  103.872 0 103.896 0.192 ;
    END
  END i_x[509]
  PIN i_x[50]
    DIRECTION INPUT ;
    USE SIGNAL ;
    PORT
      LAYER M5 ;
        RECT  15.744 0 15.768 0.192 ;
    END
  END i_x[50]
  PIN i_x[510]
    DIRECTION INPUT ;
    USE SIGNAL ;
    PORT
      LAYER M5 ;
        RECT  104.064 0 104.088 0.192 ;
    END
  END i_x[510]
  PIN i_x[511]
    DIRECTION INPUT ;
    USE SIGNAL ;
    PORT
      LAYER M5 ;
        RECT  104.256 0 104.28 0.192 ;
    END
  END i_x[511]
  PIN i_x[512]
    DIRECTION INPUT ;
    USE SIGNAL ;
    PORT
      LAYER M5 ;
        RECT  104.448 0 104.472 0.192 ;
    END
  END i_x[512]
  PIN i_x[513]
    DIRECTION INPUT ;
    USE SIGNAL ;
    PORT
      LAYER M5 ;
        RECT  104.64 0 104.664 0.192 ;
    END
  END i_x[513]
  PIN i_x[514]
    DIRECTION INPUT ;
    USE SIGNAL ;
    PORT
      LAYER M5 ;
        RECT  104.832 0 104.856 0.192 ;
    END
  END i_x[514]
  PIN i_x[515]
    DIRECTION INPUT ;
    USE SIGNAL ;
    PORT
      LAYER M5 ;
        RECT  105.024 0 105.048 0.192 ;
    END
  END i_x[515]
  PIN i_x[516]
    DIRECTION INPUT ;
    USE SIGNAL ;
    PORT
      LAYER M5 ;
        RECT  105.216 0 105.24 0.192 ;
    END
  END i_x[516]
  PIN i_x[517]
    DIRECTION INPUT ;
    USE SIGNAL ;
    PORT
      LAYER M5 ;
        RECT  105.408 0 105.432 0.192 ;
    END
  END i_x[517]
  PIN i_x[518]
    DIRECTION INPUT ;
    USE SIGNAL ;
    PORT
      LAYER M5 ;
        RECT  105.6 0 105.624 0.192 ;
    END
  END i_x[518]
  PIN i_x[519]
    DIRECTION INPUT ;
    USE SIGNAL ;
    PORT
      LAYER M5 ;
        RECT  105.792 0 105.816 0.192 ;
    END
  END i_x[519]
  PIN i_x[51]
    DIRECTION INPUT ;
    USE SIGNAL ;
    PORT
      LAYER M5 ;
        RECT  15.936 0 15.96 0.192 ;
    END
  END i_x[51]
  PIN i_x[520]
    DIRECTION INPUT ;
    USE SIGNAL ;
    PORT
      LAYER M5 ;
        RECT  105.984 0 106.008 0.192 ;
    END
  END i_x[520]
  PIN i_x[521]
    DIRECTION INPUT ;
    USE SIGNAL ;
    PORT
      LAYER M5 ;
        RECT  106.176 0 106.2 0.192 ;
    END
  END i_x[521]
  PIN i_x[522]
    DIRECTION INPUT ;
    USE SIGNAL ;
    PORT
      LAYER M5 ;
        RECT  106.368 0 106.392 0.192 ;
    END
  END i_x[522]
  PIN i_x[523]
    DIRECTION INPUT ;
    USE SIGNAL ;
    PORT
      LAYER M5 ;
        RECT  106.56 0 106.584 0.192 ;
    END
  END i_x[523]
  PIN i_x[524]
    DIRECTION INPUT ;
    USE SIGNAL ;
    PORT
      LAYER M5 ;
        RECT  106.752 0 106.776 0.192 ;
    END
  END i_x[524]
  PIN i_x[525]
    DIRECTION INPUT ;
    USE SIGNAL ;
    PORT
      LAYER M5 ;
        RECT  106.944 0 106.968 0.192 ;
    END
  END i_x[525]
  PIN i_x[526]
    DIRECTION INPUT ;
    USE SIGNAL ;
    PORT
      LAYER M5 ;
        RECT  107.136 0 107.16 0.192 ;
    END
  END i_x[526]
  PIN i_x[527]
    DIRECTION INPUT ;
    USE SIGNAL ;
    PORT
      LAYER M5 ;
        RECT  107.328 0 107.352 0.192 ;
    END
  END i_x[527]
  PIN i_x[528]
    DIRECTION INPUT ;
    USE SIGNAL ;
    PORT
      LAYER M5 ;
        RECT  107.52 0 107.544 0.192 ;
    END
  END i_x[528]
  PIN i_x[529]
    DIRECTION INPUT ;
    USE SIGNAL ;
    PORT
      LAYER M5 ;
        RECT  107.712 0 107.736 0.192 ;
    END
  END i_x[529]
  PIN i_x[52]
    DIRECTION INPUT ;
    USE SIGNAL ;
    PORT
      LAYER M5 ;
        RECT  16.128 0 16.152 0.192 ;
    END
  END i_x[52]
  PIN i_x[530]
    DIRECTION INPUT ;
    USE SIGNAL ;
    PORT
      LAYER M5 ;
        RECT  107.904 0 107.928 0.192 ;
    END
  END i_x[530]
  PIN i_x[531]
    DIRECTION INPUT ;
    USE SIGNAL ;
    PORT
      LAYER M5 ;
        RECT  108.096 0 108.12 0.192 ;
    END
  END i_x[531]
  PIN i_x[53]
    DIRECTION INPUT ;
    USE SIGNAL ;
    PORT
      LAYER M5 ;
        RECT  16.32 0 16.344 0.192 ;
    END
  END i_x[53]
  PIN i_x[54]
    DIRECTION INPUT ;
    USE SIGNAL ;
    PORT
      LAYER M5 ;
        RECT  16.512 0 16.536 0.192 ;
    END
  END i_x[54]
  PIN i_x[55]
    DIRECTION INPUT ;
    USE SIGNAL ;
    PORT
      LAYER M5 ;
        RECT  16.704 0 16.728 0.192 ;
    END
  END i_x[55]
  PIN i_x[56]
    DIRECTION INPUT ;
    USE SIGNAL ;
    PORT
      LAYER M5 ;
        RECT  16.896 0 16.92 0.192 ;
    END
  END i_x[56]
  PIN i_x[57]
    DIRECTION INPUT ;
    USE SIGNAL ;
    PORT
      LAYER M5 ;
        RECT  17.088 0 17.112 0.192 ;
    END
  END i_x[57]
  PIN i_x[58]
    DIRECTION INPUT ;
    USE SIGNAL ;
    PORT
      LAYER M5 ;
        RECT  17.28 0 17.304 0.192 ;
    END
  END i_x[58]
  PIN i_x[59]
    DIRECTION INPUT ;
    USE SIGNAL ;
    PORT
      LAYER M5 ;
        RECT  17.472 0 17.496 0.192 ;
    END
  END i_x[59]
  PIN i_x[5]
    DIRECTION INPUT ;
    USE SIGNAL ;
    PORT
      LAYER M5 ;
        RECT  7.104 0 7.128 0.192 ;
    END
  END i_x[5]
  PIN i_x[60]
    DIRECTION INPUT ;
    USE SIGNAL ;
    PORT
      LAYER M5 ;
        RECT  17.664 0 17.688 0.192 ;
    END
  END i_x[60]
  PIN i_x[61]
    DIRECTION INPUT ;
    USE SIGNAL ;
    PORT
      LAYER M5 ;
        RECT  17.856 0 17.88 0.192 ;
    END
  END i_x[61]
  PIN i_x[62]
    DIRECTION INPUT ;
    USE SIGNAL ;
    PORT
      LAYER M5 ;
        RECT  18.048 0 18.072 0.192 ;
    END
  END i_x[62]
  PIN i_x[63]
    DIRECTION INPUT ;
    USE SIGNAL ;
    PORT
      LAYER M5 ;
        RECT  18.24 0 18.264 0.192 ;
    END
  END i_x[63]
  PIN i_x[64]
    DIRECTION INPUT ;
    USE SIGNAL ;
    PORT
      LAYER M5 ;
        RECT  18.432 0 18.456 0.192 ;
    END
  END i_x[64]
  PIN i_x[65]
    DIRECTION INPUT ;
    USE SIGNAL ;
    PORT
      LAYER M5 ;
        RECT  18.624 0 18.648 0.192 ;
    END
  END i_x[65]
  PIN i_x[66]
    DIRECTION INPUT ;
    USE SIGNAL ;
    PORT
      LAYER M5 ;
        RECT  18.816 0 18.84 0.192 ;
    END
  END i_x[66]
  PIN i_x[67]
    DIRECTION INPUT ;
    USE SIGNAL ;
    PORT
      LAYER M5 ;
        RECT  19.008 0 19.032 0.192 ;
    END
  END i_x[67]
  PIN i_x[68]
    DIRECTION INPUT ;
    USE SIGNAL ;
    PORT
      LAYER M5 ;
        RECT  19.2 0 19.224 0.192 ;
    END
  END i_x[68]
  PIN i_x[69]
    DIRECTION INPUT ;
    USE SIGNAL ;
    PORT
      LAYER M5 ;
        RECT  19.392 0 19.416 0.192 ;
    END
  END i_x[69]
  PIN i_x[6]
    DIRECTION INPUT ;
    USE SIGNAL ;
    PORT
      LAYER M5 ;
        RECT  7.296 0 7.32 0.192 ;
    END
  END i_x[6]
  PIN i_x[70]
    DIRECTION INPUT ;
    USE SIGNAL ;
    PORT
      LAYER M5 ;
        RECT  19.584 0 19.608 0.192 ;
    END
  END i_x[70]
  PIN i_x[71]
    DIRECTION INPUT ;
    USE SIGNAL ;
    PORT
      LAYER M5 ;
        RECT  19.776 0 19.8 0.192 ;
    END
  END i_x[71]
  PIN i_x[72]
    DIRECTION INPUT ;
    USE SIGNAL ;
    PORT
      LAYER M5 ;
        RECT  19.968 0 19.992 0.192 ;
    END
  END i_x[72]
  PIN i_x[73]
    DIRECTION INPUT ;
    USE SIGNAL ;
    PORT
      LAYER M5 ;
        RECT  20.16 0 20.184 0.192 ;
    END
  END i_x[73]
  PIN i_x[74]
    DIRECTION INPUT ;
    USE SIGNAL ;
    PORT
      LAYER M5 ;
        RECT  20.352 0 20.376 0.192 ;
    END
  END i_x[74]
  PIN i_x[75]
    DIRECTION INPUT ;
    USE SIGNAL ;
    PORT
      LAYER M5 ;
        RECT  20.544 0 20.568 0.192 ;
    END
  END i_x[75]
  PIN i_x[76]
    DIRECTION INPUT ;
    USE SIGNAL ;
    PORT
      LAYER M5 ;
        RECT  20.736 0 20.76 0.192 ;
    END
  END i_x[76]
  PIN i_x[77]
    DIRECTION INPUT ;
    USE SIGNAL ;
    PORT
      LAYER M5 ;
        RECT  20.928 0 20.952 0.192 ;
    END
  END i_x[77]
  PIN i_x[78]
    DIRECTION INPUT ;
    USE SIGNAL ;
    PORT
      LAYER M5 ;
        RECT  21.12 0 21.144 0.192 ;
    END
  END i_x[78]
  PIN i_x[79]
    DIRECTION INPUT ;
    USE SIGNAL ;
    PORT
      LAYER M5 ;
        RECT  21.312 0 21.336 0.192 ;
    END
  END i_x[79]
  PIN i_x[7]
    DIRECTION INPUT ;
    USE SIGNAL ;
    PORT
      LAYER M5 ;
        RECT  7.488 0 7.512 0.192 ;
    END
  END i_x[7]
  PIN i_x[80]
    DIRECTION INPUT ;
    USE SIGNAL ;
    PORT
      LAYER M5 ;
        RECT  21.504 0 21.528 0.192 ;
    END
  END i_x[80]
  PIN i_x[81]
    DIRECTION INPUT ;
    USE SIGNAL ;
    PORT
      LAYER M5 ;
        RECT  21.696 0 21.72 0.192 ;
    END
  END i_x[81]
  PIN i_x[82]
    DIRECTION INPUT ;
    USE SIGNAL ;
    PORT
      LAYER M5 ;
        RECT  21.888 0 21.912 0.192 ;
    END
  END i_x[82]
  PIN i_x[83]
    DIRECTION INPUT ;
    USE SIGNAL ;
    PORT
      LAYER M5 ;
        RECT  22.08 0 22.104 0.192 ;
    END
  END i_x[83]
  PIN i_x[84]
    DIRECTION INPUT ;
    USE SIGNAL ;
    PORT
      LAYER M5 ;
        RECT  22.272 0 22.296 0.192 ;
    END
  END i_x[84]
  PIN i_x[85]
    DIRECTION INPUT ;
    USE SIGNAL ;
    PORT
      LAYER M5 ;
        RECT  22.464 0 22.488 0.192 ;
    END
  END i_x[85]
  PIN i_x[86]
    DIRECTION INPUT ;
    USE SIGNAL ;
    PORT
      LAYER M5 ;
        RECT  22.656 0 22.68 0.192 ;
    END
  END i_x[86]
  PIN i_x[87]
    DIRECTION INPUT ;
    USE SIGNAL ;
    PORT
      LAYER M5 ;
        RECT  22.848 0 22.872 0.192 ;
    END
  END i_x[87]
  PIN i_x[88]
    DIRECTION INPUT ;
    USE SIGNAL ;
    PORT
      LAYER M5 ;
        RECT  23.04 0 23.064 0.192 ;
    END
  END i_x[88]
  PIN i_x[89]
    DIRECTION INPUT ;
    USE SIGNAL ;
    PORT
      LAYER M5 ;
        RECT  23.232 0 23.256 0.192 ;
    END
  END i_x[89]
  PIN i_x[8]
    DIRECTION INPUT ;
    USE SIGNAL ;
    PORT
      LAYER M5 ;
        RECT  7.68 0 7.704 0.192 ;
    END
  END i_x[8]
  PIN i_x[90]
    DIRECTION INPUT ;
    USE SIGNAL ;
    PORT
      LAYER M5 ;
        RECT  23.424 0 23.448 0.192 ;
    END
  END i_x[90]
  PIN i_x[91]
    DIRECTION INPUT ;
    USE SIGNAL ;
    PORT
      LAYER M5 ;
        RECT  23.616 0 23.64 0.192 ;
    END
  END i_x[91]
  PIN i_x[92]
    DIRECTION INPUT ;
    USE SIGNAL ;
    PORT
      LAYER M5 ;
        RECT  23.808 0 23.832 0.192 ;
    END
  END i_x[92]
  PIN i_x[93]
    DIRECTION INPUT ;
    USE SIGNAL ;
    PORT
      LAYER M5 ;
        RECT  24 0 24.024 0.192 ;
    END
  END i_x[93]
  PIN i_x[94]
    DIRECTION INPUT ;
    USE SIGNAL ;
    PORT
      LAYER M5 ;
        RECT  24.192 0 24.216 0.192 ;
    END
  END i_x[94]
  PIN i_x[95]
    DIRECTION INPUT ;
    USE SIGNAL ;
    PORT
      LAYER M5 ;
        RECT  24.384 0 24.408 0.192 ;
    END
  END i_x[95]
  PIN i_x[96]
    DIRECTION INPUT ;
    USE SIGNAL ;
    PORT
      LAYER M5 ;
        RECT  24.576 0 24.6 0.192 ;
    END
  END i_x[96]
  PIN i_x[97]
    DIRECTION INPUT ;
    USE SIGNAL ;
    PORT
      LAYER M5 ;
        RECT  24.768 0 24.792 0.192 ;
    END
  END i_x[97]
  PIN i_x[98]
    DIRECTION INPUT ;
    USE SIGNAL ;
    PORT
      LAYER M5 ;
        RECT  24.96 0 24.984 0.192 ;
    END
  END i_x[98]
  PIN i_x[99]
    DIRECTION INPUT ;
    USE SIGNAL ;
    PORT
      LAYER M5 ;
        RECT  25.152 0 25.176 0.192 ;
    END
  END i_x[99]
  PIN i_x[9]
    DIRECTION INPUT ;
    USE SIGNAL ;
    PORT
      LAYER M5 ;
        RECT  7.872 0 7.896 0.192 ;
    END
  END i_x[9]
  PIN otag[0]
    DIRECTION OUTPUT ;
    USE SIGNAL ;
    PORT
      LAYER M5 ;
        RECT  26.496 142.368 26.52 142.56 ;
    END
  END otag[0]
  PIN otag[10]
    DIRECTION OUTPUT ;
    USE SIGNAL ;
    PORT
      LAYER M5 ;
        RECT  28.416 142.368 28.44 142.56 ;
    END
  END otag[10]
  PIN otag[11]
    DIRECTION OUTPUT ;
    USE SIGNAL ;
    PORT
      LAYER M5 ;
        RECT  28.608 142.368 28.632 142.56 ;
    END
  END otag[11]
  PIN otag[12]
    DIRECTION OUTPUT ;
    USE SIGNAL ;
    PORT
      LAYER M5 ;
        RECT  28.8 142.368 28.824 142.56 ;
    END
  END otag[12]
  PIN otag[13]
    DIRECTION OUTPUT ;
    USE SIGNAL ;
    PORT
      LAYER M5 ;
        RECT  28.992 142.368 29.016 142.56 ;
    END
  END otag[13]
  PIN otag[14]
    DIRECTION OUTPUT ;
    USE SIGNAL ;
    PORT
      LAYER M5 ;
        RECT  29.184 142.368 29.208 142.56 ;
    END
  END otag[14]
  PIN otag[15]
    DIRECTION OUTPUT ;
    USE SIGNAL ;
    PORT
      LAYER M5 ;
        RECT  29.376 142.368 29.4 142.56 ;
    END
  END otag[15]
  PIN otag[1]
    DIRECTION OUTPUT ;
    USE SIGNAL ;
    PORT
      LAYER M5 ;
        RECT  26.688 142.368 26.712 142.56 ;
    END
  END otag[1]
  PIN otag[2]
    DIRECTION OUTPUT ;
    USE SIGNAL ;
    PORT
      LAYER M5 ;
        RECT  26.88 142.368 26.904 142.56 ;
    END
  END otag[2]
  PIN otag[3]
    DIRECTION OUTPUT ;
    USE SIGNAL ;
    PORT
      LAYER M5 ;
        RECT  27.072 142.368 27.096 142.56 ;
    END
  END otag[3]
  PIN otag[4]
    DIRECTION OUTPUT ;
    USE SIGNAL ;
    PORT
      LAYER M5 ;
        RECT  27.264 142.368 27.288 142.56 ;
    END
  END otag[4]
  PIN otag[5]
    DIRECTION OUTPUT ;
    USE SIGNAL ;
    PORT
      LAYER M5 ;
        RECT  27.456 142.368 27.48 142.56 ;
    END
  END otag[5]
  PIN otag[6]
    DIRECTION OUTPUT ;
    USE SIGNAL ;
    PORT
      LAYER M5 ;
        RECT  27.648 142.368 27.672 142.56 ;
    END
  END otag[6]
  PIN otag[7]
    DIRECTION OUTPUT ;
    USE SIGNAL ;
    PORT
      LAYER M5 ;
        RECT  27.84 142.368 27.864 142.56 ;
    END
  END otag[7]
  PIN otag[8]
    DIRECTION OUTPUT ;
    USE SIGNAL ;
    PORT
      LAYER M5 ;
        RECT  28.032 142.368 28.056 142.56 ;
    END
  END otag[8]
  PIN otag[9]
    DIRECTION OUTPUT ;
    USE SIGNAL ;
    PORT
      LAYER M5 ;
        RECT  28.224 142.368 28.248 142.56 ;
    END
  END otag[9]
  PIN ov
    DIRECTION OUTPUT ;
    USE SIGNAL ;
    PORT
      LAYER M5 ;
        RECT  19.968 142.368 19.992 142.56 ;
    END
  END ov
  PIN rst_a
    DIRECTION INPUT ;
    USE SIGNAL ;
    PORT
      LAYER M5 ;
        RECT  29.76 142.368 29.784 142.56 ;
    END
  END rst_a
  PIN y[0]
    DIRECTION OUTPUT ;
    USE SIGNAL ;
    PORT
      LAYER M5 ;
        RECT  20.352 142.368 20.376 142.56 ;
    END
  END y[0]
  PIN y[10]
    DIRECTION OUTPUT ;
    USE SIGNAL ;
    PORT
      LAYER M5 ;
        RECT  22.272 142.368 22.296 142.56 ;
    END
  END y[10]
  PIN y[11]
    DIRECTION OUTPUT ;
    USE SIGNAL ;
    PORT
      LAYER M5 ;
        RECT  22.464 142.368 22.488 142.56 ;
    END
  END y[11]
  PIN y[12]
    DIRECTION OUTPUT ;
    USE SIGNAL ;
    PORT
      LAYER M5 ;
        RECT  22.656 142.368 22.68 142.56 ;
    END
  END y[12]
  PIN y[13]
    DIRECTION OUTPUT ;
    USE SIGNAL ;
    PORT
      LAYER M5 ;
        RECT  22.848 142.368 22.872 142.56 ;
    END
  END y[13]
  PIN y[14]
    DIRECTION OUTPUT ;
    USE SIGNAL ;
    PORT
      LAYER M5 ;
        RECT  23.04 142.368 23.064 142.56 ;
    END
  END y[14]
  PIN y[15]
    DIRECTION OUTPUT ;
    USE SIGNAL ;
    PORT
      LAYER M5 ;
        RECT  23.232 142.368 23.256 142.56 ;
    END
  END y[15]
  PIN y[16]
    DIRECTION OUTPUT ;
    USE SIGNAL ;
    PORT
      LAYER M5 ;
        RECT  23.424 142.368 23.448 142.56 ;
    END
  END y[16]
  PIN y[17]
    DIRECTION OUTPUT ;
    USE SIGNAL ;
    PORT
      LAYER M5 ;
        RECT  23.616 142.368 23.64 142.56 ;
    END
  END y[17]
  PIN y[18]
    DIRECTION OUTPUT ;
    USE SIGNAL ;
    PORT
      LAYER M5 ;
        RECT  23.808 142.368 23.832 142.56 ;
    END
  END y[18]
  PIN y[19]
    DIRECTION OUTPUT ;
    USE SIGNAL ;
    PORT
      LAYER M5 ;
        RECT  24 142.368 24.024 142.56 ;
    END
  END y[19]
  PIN y[1]
    DIRECTION OUTPUT ;
    USE SIGNAL ;
    PORT
      LAYER M5 ;
        RECT  20.544 142.368 20.568 142.56 ;
    END
  END y[1]
  PIN y[20]
    DIRECTION OUTPUT ;
    USE SIGNAL ;
    PORT
      LAYER M5 ;
        RECT  24.192 142.368 24.216 142.56 ;
    END
  END y[20]
  PIN y[21]
    DIRECTION OUTPUT ;
    USE SIGNAL ;
    PORT
      LAYER M5 ;
        RECT  24.384 142.368 24.408 142.56 ;
    END
  END y[21]
  PIN y[22]
    DIRECTION OUTPUT ;
    USE SIGNAL ;
    PORT
      LAYER M5 ;
        RECT  24.576 142.368 24.6 142.56 ;
    END
  END y[22]
  PIN y[23]
    DIRECTION OUTPUT ;
    USE SIGNAL ;
    PORT
      LAYER M5 ;
        RECT  24.768 142.368 24.792 142.56 ;
    END
  END y[23]
  PIN y[24]
    DIRECTION OUTPUT ;
    USE SIGNAL ;
    PORT
      LAYER M5 ;
        RECT  24.96 142.368 24.984 142.56 ;
    END
  END y[24]
  PIN y[25]
    DIRECTION OUTPUT ;
    USE SIGNAL ;
    PORT
      LAYER M5 ;
        RECT  25.152 142.368 25.176 142.56 ;
    END
  END y[25]
  PIN y[26]
    DIRECTION OUTPUT ;
    USE SIGNAL ;
    PORT
      LAYER M5 ;
        RECT  25.344 142.368 25.368 142.56 ;
    END
  END y[26]
  PIN y[27]
    DIRECTION OUTPUT ;
    USE SIGNAL ;
    PORT
      LAYER M5 ;
        RECT  25.536 142.368 25.56 142.56 ;
    END
  END y[27]
  PIN y[28]
    DIRECTION OUTPUT ;
    USE SIGNAL ;
    PORT
      LAYER M5 ;
        RECT  25.728 142.368 25.752 142.56 ;
    END
  END y[28]
  PIN y[29]
    DIRECTION OUTPUT ;
    USE SIGNAL ;
    PORT
      LAYER M5 ;
        RECT  25.92 142.368 25.944 142.56 ;
    END
  END y[29]
  PIN y[2]
    DIRECTION OUTPUT ;
    USE SIGNAL ;
    PORT
      LAYER M5 ;
        RECT  20.736 142.368 20.76 142.56 ;
    END
  END y[2]
  PIN y[30]
    DIRECTION OUTPUT ;
    USE SIGNAL ;
    PORT
      LAYER M5 ;
        RECT  26.112 142.368 26.136 142.56 ;
    END
  END y[30]
  PIN y[31]
    DIRECTION OUTPUT ;
    USE SIGNAL ;
    PORT
      LAYER M5 ;
        RECT  26.304 142.368 26.328 142.56 ;
    END
  END y[31]
  PIN y[3]
    DIRECTION OUTPUT ;
    USE SIGNAL ;
    PORT
      LAYER M5 ;
        RECT  20.928 142.368 20.952 142.56 ;
    END
  END y[3]
  PIN y[4]
    DIRECTION OUTPUT ;
    USE SIGNAL ;
    PORT
      LAYER M5 ;
        RECT  21.12 142.368 21.144 142.56 ;
    END
  END y[4]
  PIN y[5]
    DIRECTION OUTPUT ;
    USE SIGNAL ;
    PORT
      LAYER M5 ;
        RECT  21.312 142.368 21.336 142.56 ;
    END
  END y[5]
  PIN y[6]
    DIRECTION OUTPUT ;
    USE SIGNAL ;
    PORT
      LAYER M5 ;
        RECT  21.504 142.368 21.528 142.56 ;
    END
  END y[6]
  PIN y[7]
    DIRECTION OUTPUT ;
    USE SIGNAL ;
    PORT
      LAYER M5 ;
        RECT  21.696 142.368 21.72 142.56 ;
    END
  END y[7]
  PIN y[8]
    DIRECTION OUTPUT ;
    USE SIGNAL ;
    PORT
      LAYER M5 ;
        RECT  21.888 142.368 21.912 142.56 ;
    END
  END y[8]
  PIN y[9]
    DIRECTION OUTPUT ;
    USE SIGNAL ;
    PORT
      LAYER M5 ;
        RECT  22.08 142.368 22.104 142.56 ;
    END
  END y[9]
  PIN VDD
    DIRECTION INOUT ;
    USE POWER ;
    PORT
      LAYER M6 ;
        RECT  0.468 132.92 111.852 133.208 ;
        RECT  0.468 122.12 111.852 122.408 ;
        RECT  0.468 111.32 111.852 111.608 ;
        RECT  0.468 100.52 111.852 100.808 ;
        RECT  0.468 89.72 111.852 90.008 ;
        RECT  0.468 78.92 111.852 79.208 ;
        RECT  0.468 68.12 111.852 68.408 ;
        RECT  0.468 57.32 111.852 57.608 ;
        RECT  0.468 46.52 111.852 46.808 ;
        RECT  0.468 35.72 111.852 36.008 ;
        RECT  0.468 24.92 111.852 25.208 ;
        RECT  0.468 14.12 111.852 14.408 ;
        RECT  0.468 3.32 111.852 3.608 ;
        RECT  0.468 142.164 111.852 142.452 ;
        RECT  0.468 0.108 111.852 0.396 ;
    END
  END VDD
  PIN VSS
    DIRECTION INOUT ;
    USE GROUND ;
    PORT
      LAYER M6 ;
        RECT  0.468 132.536 111.852 132.824 ;
        RECT  0.468 121.736 111.852 122.024 ;
        RECT  0.468 110.936 111.852 111.224 ;
        RECT  0.468 100.136 111.852 100.424 ;
        RECT  0.468 89.336 111.852 89.624 ;
        RECT  0.468 78.536 111.852 78.824 ;
        RECT  0.468 67.736 111.852 68.024 ;
        RECT  0.468 56.936 111.852 57.224 ;
        RECT  0.468 46.136 111.852 46.424 ;
        RECT  0.468 35.336 111.852 35.624 ;
        RECT  0.468 24.536 111.852 24.824 ;
        RECT  0.468 13.736 111.852 14.024 ;
        RECT  0.468 2.936 111.852 3.224 ;
        RECT  0.66 141.78 111.66 142.068 ;
        RECT  0.66 0.492 111.66 0.78 ;
    END
  END VSS
  OBS
    LAYER RVTN ;
     RECT  0.468 0 111.852 142.56 ;
    LAYER RVTP ;
     RECT  0.468 0 111.852 142.56 ;
    LAYER M1 ;
     RECT  0.468 0 111.852 142.56 ;
    LAYER M2 ;
     RECT  0.468 0 111.852 142.56 ;
    LAYER M3 ;
     RECT  0.468 0 111.852 142.56 ;
    LAYER M4 ;
     RECT  0.468 0 111.852 142.56 ;
    LAYER M5 ;
     RECT  0.468 0 111.852 142.56 ;
    LAYER M6 ;
     RECT  0.468 0 111.852 142.56 ;
  END
END ot_hbm_accel_smh_bdc
END LIBRARY
